# Placeholder macro written by tools/chip_assembly/macros.py
# kind: link; half of the 112G SerDes strip (die assembly 1.0 x 18.0 mm) at 1/4: the package-pair collective lanes, or the stage-hop lanes
VERSION 5.7 ;
BUSBITCHARS "[]" ;
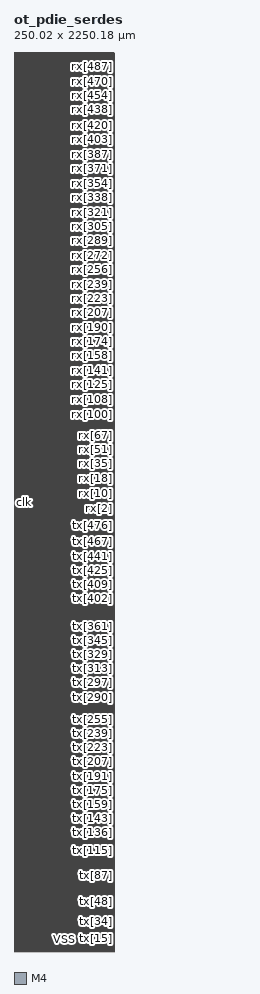
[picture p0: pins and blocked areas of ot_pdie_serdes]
MACRO ot_pdie_serdes
  FOREIGN ot_pdie_serdes 0 0 ;
  SYMMETRY X Y R90 ;
  SIZE 250.020 BY 2250.180 ;
  CLASS BLOCK ;
  PIN clk
    DIRECTION INPUT ;
    USE SIGNAL ;
    SHAPE ABUTMENT ;
    PORT
      LAYER M4 ;
      RECT 0.000 1125.072 0.192 1125.096 ;
    END
  END clk
  PIN tx[0]
    DIRECTION INPUT ;
    USE SIGNAL ;
    SHAPE ABUTMENT ;
    PORT
      LAYER M4 ;
      RECT 249.828 0.528 250.020 0.552 ;
    END
  END tx[0]
  PIN tx[1]
    DIRECTION INPUT ;
    USE SIGNAL ;
    SHAPE ABUTMENT ;
    PORT
      LAYER M4 ;
      RECT 249.828 2.688 250.020 2.712 ;
    END
  END tx[1]
  PIN tx[2]
    DIRECTION INPUT ;
    USE SIGNAL ;
    SHAPE ABUTMENT ;
    PORT
      LAYER M4 ;
      RECT 249.828 4.896 250.020 4.920 ;
    END
  END tx[2]
  PIN tx[3]
    DIRECTION INPUT ;
    USE SIGNAL ;
    SHAPE ABUTMENT ;
    PORT
      LAYER M4 ;
      RECT 249.828 7.104 250.020 7.128 ;
    END
  END tx[3]
  PIN tx[4]
    DIRECTION INPUT ;
    USE SIGNAL ;
    SHAPE ABUTMENT ;
    PORT
      LAYER M4 ;
      RECT 249.828 9.312 250.020 9.336 ;
    END
  END tx[4]
  PIN tx[5]
    DIRECTION INPUT ;
    USE SIGNAL ;
    SHAPE ABUTMENT ;
    PORT
      LAYER M4 ;
      RECT 249.828 11.472 250.020 11.496 ;
    END
  END tx[5]
  PIN tx[6]
    DIRECTION INPUT ;
    USE SIGNAL ;
    SHAPE ABUTMENT ;
    PORT
      LAYER M4 ;
      RECT 249.828 13.680 250.020 13.704 ;
    END
  END tx[6]
  PIN tx[7]
    DIRECTION INPUT ;
    USE SIGNAL ;
    SHAPE ABUTMENT ;
    PORT
      LAYER M4 ;
      RECT 249.828 15.888 250.020 15.912 ;
    END
  END tx[7]
  PIN tx[8]
    DIRECTION INPUT ;
    USE SIGNAL ;
    SHAPE ABUTMENT ;
    PORT
      LAYER M4 ;
      RECT 249.828 18.096 250.020 18.120 ;
    END
  END tx[8]
  PIN tx[9]
    DIRECTION INPUT ;
    USE SIGNAL ;
    SHAPE ABUTMENT ;
    PORT
      LAYER M4 ;
      RECT 249.828 20.256 250.020 20.280 ;
    END
  END tx[9]
  PIN tx[10]
    DIRECTION INPUT ;
    USE SIGNAL ;
    SHAPE ABUTMENT ;
    PORT
      LAYER M4 ;
      RECT 249.828 22.464 250.020 22.488 ;
    END
  END tx[10]
  PIN tx[11]
    DIRECTION INPUT ;
    USE SIGNAL ;
    SHAPE ABUTMENT ;
    PORT
      LAYER M4 ;
      RECT 249.828 24.672 250.020 24.696 ;
    END
  END tx[11]
  PIN tx[12]
    DIRECTION INPUT ;
    USE SIGNAL ;
    SHAPE ABUTMENT ;
    PORT
      LAYER M4 ;
      RECT 249.828 26.880 250.020 26.904 ;
    END
  END tx[12]
  PIN tx[13]
    DIRECTION INPUT ;
    USE SIGNAL ;
    SHAPE ABUTMENT ;
    PORT
      LAYER M4 ;
      RECT 249.828 29.040 250.020 29.064 ;
    END
  END tx[13]
  PIN tx[14]
    DIRECTION INPUT ;
    USE SIGNAL ;
    SHAPE ABUTMENT ;
    PORT
      LAYER M4 ;
      RECT 249.828 31.248 250.020 31.272 ;
    END
  END tx[14]
  PIN tx[15]
    DIRECTION INPUT ;
    USE SIGNAL ;
    SHAPE ABUTMENT ;
    PORT
      LAYER M4 ;
      RECT 249.828 33.456 250.020 33.480 ;
    END
  END tx[15]
  PIN tx[16]
    DIRECTION INPUT ;
    USE SIGNAL ;
    SHAPE ABUTMENT ;
    PORT
      LAYER M4 ;
      RECT 249.828 35.664 250.020 35.688 ;
    END
  END tx[16]
  PIN tx[17]
    DIRECTION INPUT ;
    USE SIGNAL ;
    SHAPE ABUTMENT ;
    PORT
      LAYER M4 ;
      RECT 249.828 37.824 250.020 37.848 ;
    END
  END tx[17]
  PIN tx[18]
    DIRECTION INPUT ;
    USE SIGNAL ;
    SHAPE ABUTMENT ;
    PORT
      LAYER M4 ;
      RECT 249.828 40.032 250.020 40.056 ;
    END
  END tx[18]
  PIN tx[19]
    DIRECTION INPUT ;
    USE SIGNAL ;
    SHAPE ABUTMENT ;
    PORT
      LAYER M4 ;
      RECT 249.828 42.240 250.020 42.264 ;
    END
  END tx[19]
  PIN tx[20]
    DIRECTION INPUT ;
    USE SIGNAL ;
    SHAPE ABUTMENT ;
    PORT
      LAYER M4 ;
      RECT 249.828 44.448 250.020 44.472 ;
    END
  END tx[20]
  PIN tx[21]
    DIRECTION INPUT ;
    USE SIGNAL ;
    SHAPE ABUTMENT ;
    PORT
      LAYER M4 ;
      RECT 249.828 46.608 250.020 46.632 ;
    END
  END tx[21]
  PIN tx[22]
    DIRECTION INPUT ;
    USE SIGNAL ;
    SHAPE ABUTMENT ;
    PORT
      LAYER M4 ;
      RECT 249.828 48.816 250.020 48.840 ;
    END
  END tx[22]
  PIN tx[23]
    DIRECTION INPUT ;
    USE SIGNAL ;
    SHAPE ABUTMENT ;
    PORT
      LAYER M4 ;
      RECT 249.828 51.024 250.020 51.048 ;
    END
  END tx[23]
  PIN tx[24]
    DIRECTION INPUT ;
    USE SIGNAL ;
    SHAPE ABUTMENT ;
    PORT
      LAYER M4 ;
      RECT 249.828 53.232 250.020 53.256 ;
    END
  END tx[24]
  PIN tx[25]
    DIRECTION INPUT ;
    USE SIGNAL ;
    SHAPE ABUTMENT ;
    PORT
      LAYER M4 ;
      RECT 249.828 55.392 250.020 55.416 ;
    END
  END tx[25]
  PIN tx[26]
    DIRECTION INPUT ;
    USE SIGNAL ;
    SHAPE ABUTMENT ;
    PORT
      LAYER M4 ;
      RECT 249.828 57.600 250.020 57.624 ;
    END
  END tx[26]
  PIN tx[27]
    DIRECTION INPUT ;
    USE SIGNAL ;
    SHAPE ABUTMENT ;
    PORT
      LAYER M4 ;
      RECT 249.828 59.808 250.020 59.832 ;
    END
  END tx[27]
  PIN tx[28]
    DIRECTION INPUT ;
    USE SIGNAL ;
    SHAPE ABUTMENT ;
    PORT
      LAYER M4 ;
      RECT 249.828 62.016 250.020 62.040 ;
    END
  END tx[28]
  PIN tx[29]
    DIRECTION INPUT ;
    USE SIGNAL ;
    SHAPE ABUTMENT ;
    PORT
      LAYER M4 ;
      RECT 249.828 64.224 250.020 64.248 ;
    END
  END tx[29]
  PIN tx[30]
    DIRECTION INPUT ;
    USE SIGNAL ;
    SHAPE ABUTMENT ;
    PORT
      LAYER M4 ;
      RECT 249.828 66.384 250.020 66.408 ;
    END
  END tx[30]
  PIN tx[31]
    DIRECTION INPUT ;
    USE SIGNAL ;
    SHAPE ABUTMENT ;
    PORT
      LAYER M4 ;
      RECT 249.828 68.592 250.020 68.616 ;
    END
  END tx[31]
  PIN tx[32]
    DIRECTION INPUT ;
    USE SIGNAL ;
    SHAPE ABUTMENT ;
    PORT
      LAYER M4 ;
      RECT 249.828 70.800 250.020 70.824 ;
    END
  END tx[32]
  PIN tx[33]
    DIRECTION INPUT ;
    USE SIGNAL ;
    SHAPE ABUTMENT ;
    PORT
      LAYER M4 ;
      RECT 249.828 73.008 250.020 73.032 ;
    END
  END tx[33]
  PIN tx[34]
    DIRECTION INPUT ;
    USE SIGNAL ;
    SHAPE ABUTMENT ;
    PORT
      LAYER M4 ;
      RECT 249.828 75.168 250.020 75.192 ;
    END
  END tx[34]
  PIN tx[35]
    DIRECTION INPUT ;
    USE SIGNAL ;
    SHAPE ABUTMENT ;
    PORT
      LAYER M4 ;
      RECT 249.828 77.376 250.020 77.400 ;
    END
  END tx[35]
  PIN tx[36]
    DIRECTION INPUT ;
    USE SIGNAL ;
    SHAPE ABUTMENT ;
    PORT
      LAYER M4 ;
      RECT 249.828 79.584 250.020 79.608 ;
    END
  END tx[36]
  PIN tx[37]
    DIRECTION INPUT ;
    USE SIGNAL ;
    SHAPE ABUTMENT ;
    PORT
      LAYER M4 ;
      RECT 249.828 81.792 250.020 81.816 ;
    END
  END tx[37]
  PIN tx[38]
    DIRECTION INPUT ;
    USE SIGNAL ;
    SHAPE ABUTMENT ;
    PORT
      LAYER M4 ;
      RECT 249.828 83.952 250.020 83.976 ;
    END
  END tx[38]
  PIN tx[39]
    DIRECTION INPUT ;
    USE SIGNAL ;
    SHAPE ABUTMENT ;
    PORT
      LAYER M4 ;
      RECT 249.828 86.160 250.020 86.184 ;
    END
  END tx[39]
  PIN tx[40]
    DIRECTION INPUT ;
    USE SIGNAL ;
    SHAPE ABUTMENT ;
    PORT
      LAYER M4 ;
      RECT 249.828 88.368 250.020 88.392 ;
    END
  END tx[40]
  PIN tx[41]
    DIRECTION INPUT ;
    USE SIGNAL ;
    SHAPE ABUTMENT ;
    PORT
      LAYER M4 ;
      RECT 249.828 90.576 250.020 90.600 ;
    END
  END tx[41]
  PIN tx[42]
    DIRECTION INPUT ;
    USE SIGNAL ;
    SHAPE ABUTMENT ;
    PORT
      LAYER M4 ;
      RECT 249.828 92.736 250.020 92.760 ;
    END
  END tx[42]
  PIN tx[43]
    DIRECTION INPUT ;
    USE SIGNAL ;
    SHAPE ABUTMENT ;
    PORT
      LAYER M4 ;
      RECT 249.828 94.944 250.020 94.968 ;
    END
  END tx[43]
  PIN tx[44]
    DIRECTION INPUT ;
    USE SIGNAL ;
    SHAPE ABUTMENT ;
    PORT
      LAYER M4 ;
      RECT 249.828 97.152 250.020 97.176 ;
    END
  END tx[44]
  PIN tx[45]
    DIRECTION INPUT ;
    USE SIGNAL ;
    SHAPE ABUTMENT ;
    PORT
      LAYER M4 ;
      RECT 249.828 99.360 250.020 99.384 ;
    END
  END tx[45]
  PIN tx[46]
    DIRECTION INPUT ;
    USE SIGNAL ;
    SHAPE ABUTMENT ;
    PORT
      LAYER M4 ;
      RECT 249.828 101.520 250.020 101.544 ;
    END
  END tx[46]
  PIN tx[47]
    DIRECTION INPUT ;
    USE SIGNAL ;
    SHAPE ABUTMENT ;
    PORT
      LAYER M4 ;
      RECT 249.828 103.728 250.020 103.752 ;
    END
  END tx[47]
  PIN tx[48]
    DIRECTION INPUT ;
    USE SIGNAL ;
    SHAPE ABUTMENT ;
    PORT
      LAYER M4 ;
      RECT 249.828 105.936 250.020 105.960 ;
    END
  END tx[48]
  PIN tx[49]
    DIRECTION INPUT ;
    USE SIGNAL ;
    SHAPE ABUTMENT ;
    PORT
      LAYER M4 ;
      RECT 249.828 108.144 250.020 108.168 ;
    END
  END tx[49]
  PIN tx[50]
    DIRECTION INPUT ;
    USE SIGNAL ;
    SHAPE ABUTMENT ;
    PORT
      LAYER M4 ;
      RECT 249.828 110.304 250.020 110.328 ;
    END
  END tx[50]
  PIN tx[51]
    DIRECTION INPUT ;
    USE SIGNAL ;
    SHAPE ABUTMENT ;
    PORT
      LAYER M4 ;
      RECT 249.828 112.512 250.020 112.536 ;
    END
  END tx[51]
  PIN tx[52]
    DIRECTION INPUT ;
    USE SIGNAL ;
    SHAPE ABUTMENT ;
    PORT
      LAYER M4 ;
      RECT 249.828 114.720 250.020 114.744 ;
    END
  END tx[52]
  PIN tx[53]
    DIRECTION INPUT ;
    USE SIGNAL ;
    SHAPE ABUTMENT ;
    PORT
      LAYER M4 ;
      RECT 249.828 116.928 250.020 116.952 ;
    END
  END tx[53]
  PIN tx[54]
    DIRECTION INPUT ;
    USE SIGNAL ;
    SHAPE ABUTMENT ;
    PORT
      LAYER M4 ;
      RECT 249.828 119.088 250.020 119.112 ;
    END
  END tx[54]
  PIN tx[55]
    DIRECTION INPUT ;
    USE SIGNAL ;
    SHAPE ABUTMENT ;
    PORT
      LAYER M4 ;
      RECT 249.828 121.296 250.020 121.320 ;
    END
  END tx[55]
  PIN tx[56]
    DIRECTION INPUT ;
    USE SIGNAL ;
    SHAPE ABUTMENT ;
    PORT
      LAYER M4 ;
      RECT 249.828 123.504 250.020 123.528 ;
    END
  END tx[56]
  PIN tx[57]
    DIRECTION INPUT ;
    USE SIGNAL ;
    SHAPE ABUTMENT ;
    PORT
      LAYER M4 ;
      RECT 249.828 125.712 250.020 125.736 ;
    END
  END tx[57]
  PIN tx[58]
    DIRECTION INPUT ;
    USE SIGNAL ;
    SHAPE ABUTMENT ;
    PORT
      LAYER M4 ;
      RECT 249.828 127.920 250.020 127.944 ;
    END
  END tx[58]
  PIN tx[59]
    DIRECTION INPUT ;
    USE SIGNAL ;
    SHAPE ABUTMENT ;
    PORT
      LAYER M4 ;
      RECT 249.828 130.080 250.020 130.104 ;
    END
  END tx[59]
  PIN tx[60]
    DIRECTION INPUT ;
    USE SIGNAL ;
    SHAPE ABUTMENT ;
    PORT
      LAYER M4 ;
      RECT 249.828 132.288 250.020 132.312 ;
    END
  END tx[60]
  PIN tx[61]
    DIRECTION INPUT ;
    USE SIGNAL ;
    SHAPE ABUTMENT ;
    PORT
      LAYER M4 ;
      RECT 249.828 134.496 250.020 134.520 ;
    END
  END tx[61]
  PIN tx[62]
    DIRECTION INPUT ;
    USE SIGNAL ;
    SHAPE ABUTMENT ;
    PORT
      LAYER M4 ;
      RECT 249.828 136.704 250.020 136.728 ;
    END
  END tx[62]
  PIN tx[63]
    DIRECTION INPUT ;
    USE SIGNAL ;
    SHAPE ABUTMENT ;
    PORT
      LAYER M4 ;
      RECT 249.828 138.864 250.020 138.888 ;
    END
  END tx[63]
  PIN tx[64]
    DIRECTION INPUT ;
    USE SIGNAL ;
    SHAPE ABUTMENT ;
    PORT
      LAYER M4 ;
      RECT 249.828 141.072 250.020 141.096 ;
    END
  END tx[64]
  PIN tx[65]
    DIRECTION INPUT ;
    USE SIGNAL ;
    SHAPE ABUTMENT ;
    PORT
      LAYER M4 ;
      RECT 249.828 143.280 250.020 143.304 ;
    END
  END tx[65]
  PIN tx[66]
    DIRECTION INPUT ;
    USE SIGNAL ;
    SHAPE ABUTMENT ;
    PORT
      LAYER M4 ;
      RECT 249.828 145.488 250.020 145.512 ;
    END
  END tx[66]
  PIN tx[67]
    DIRECTION INPUT ;
    USE SIGNAL ;
    SHAPE ABUTMENT ;
    PORT
      LAYER M4 ;
      RECT 249.828 147.648 250.020 147.672 ;
    END
  END tx[67]
  PIN tx[68]
    DIRECTION INPUT ;
    USE SIGNAL ;
    SHAPE ABUTMENT ;
    PORT
      LAYER M4 ;
      RECT 249.828 149.856 250.020 149.880 ;
    END
  END tx[68]
  PIN tx[69]
    DIRECTION INPUT ;
    USE SIGNAL ;
    SHAPE ABUTMENT ;
    PORT
      LAYER M4 ;
      RECT 249.828 152.064 250.020 152.088 ;
    END
  END tx[69]
  PIN tx[70]
    DIRECTION INPUT ;
    USE SIGNAL ;
    SHAPE ABUTMENT ;
    PORT
      LAYER M4 ;
      RECT 249.828 154.272 250.020 154.296 ;
    END
  END tx[70]
  PIN tx[71]
    DIRECTION INPUT ;
    USE SIGNAL ;
    SHAPE ABUTMENT ;
    PORT
      LAYER M4 ;
      RECT 249.828 156.432 250.020 156.456 ;
    END
  END tx[71]
  PIN tx[72]
    DIRECTION INPUT ;
    USE SIGNAL ;
    SHAPE ABUTMENT ;
    PORT
      LAYER M4 ;
      RECT 249.828 158.640 250.020 158.664 ;
    END
  END tx[72]
  PIN tx[73]
    DIRECTION INPUT ;
    USE SIGNAL ;
    SHAPE ABUTMENT ;
    PORT
      LAYER M4 ;
      RECT 249.828 160.848 250.020 160.872 ;
    END
  END tx[73]
  PIN tx[74]
    DIRECTION INPUT ;
    USE SIGNAL ;
    SHAPE ABUTMENT ;
    PORT
      LAYER M4 ;
      RECT 249.828 163.056 250.020 163.080 ;
    END
  END tx[74]
  PIN tx[75]
    DIRECTION INPUT ;
    USE SIGNAL ;
    SHAPE ABUTMENT ;
    PORT
      LAYER M4 ;
      RECT 249.828 165.216 250.020 165.240 ;
    END
  END tx[75]
  PIN tx[76]
    DIRECTION INPUT ;
    USE SIGNAL ;
    SHAPE ABUTMENT ;
    PORT
      LAYER M4 ;
      RECT 249.828 167.424 250.020 167.448 ;
    END
  END tx[76]
  PIN tx[77]
    DIRECTION INPUT ;
    USE SIGNAL ;
    SHAPE ABUTMENT ;
    PORT
      LAYER M4 ;
      RECT 249.828 169.632 250.020 169.656 ;
    END
  END tx[77]
  PIN tx[78]
    DIRECTION INPUT ;
    USE SIGNAL ;
    SHAPE ABUTMENT ;
    PORT
      LAYER M4 ;
      RECT 249.828 171.840 250.020 171.864 ;
    END
  END tx[78]
  PIN tx[79]
    DIRECTION INPUT ;
    USE SIGNAL ;
    SHAPE ABUTMENT ;
    PORT
      LAYER M4 ;
      RECT 249.828 174.000 250.020 174.024 ;
    END
  END tx[79]
  PIN tx[80]
    DIRECTION INPUT ;
    USE SIGNAL ;
    SHAPE ABUTMENT ;
    PORT
      LAYER M4 ;
      RECT 249.828 176.208 250.020 176.232 ;
    END
  END tx[80]
  PIN tx[81]
    DIRECTION INPUT ;
    USE SIGNAL ;
    SHAPE ABUTMENT ;
    PORT
      LAYER M4 ;
      RECT 249.828 178.416 250.020 178.440 ;
    END
  END tx[81]
  PIN tx[82]
    DIRECTION INPUT ;
    USE SIGNAL ;
    SHAPE ABUTMENT ;
    PORT
      LAYER M4 ;
      RECT 249.828 180.624 250.020 180.648 ;
    END
  END tx[82]
  PIN tx[83]
    DIRECTION INPUT ;
    USE SIGNAL ;
    SHAPE ABUTMENT ;
    PORT
      LAYER M4 ;
      RECT 249.828 182.784 250.020 182.808 ;
    END
  END tx[83]
  PIN tx[84]
    DIRECTION INPUT ;
    USE SIGNAL ;
    SHAPE ABUTMENT ;
    PORT
      LAYER M4 ;
      RECT 249.828 184.992 250.020 185.016 ;
    END
  END tx[84]
  PIN tx[85]
    DIRECTION INPUT ;
    USE SIGNAL ;
    SHAPE ABUTMENT ;
    PORT
      LAYER M4 ;
      RECT 249.828 187.200 250.020 187.224 ;
    END
  END tx[85]
  PIN tx[86]
    DIRECTION INPUT ;
    USE SIGNAL ;
    SHAPE ABUTMENT ;
    PORT
      LAYER M4 ;
      RECT 249.828 189.408 250.020 189.432 ;
    END
  END tx[86]
  PIN tx[87]
    DIRECTION INPUT ;
    USE SIGNAL ;
    SHAPE ABUTMENT ;
    PORT
      LAYER M4 ;
      RECT 249.828 191.616 250.020 191.640 ;
    END
  END tx[87]
  PIN tx[88]
    DIRECTION INPUT ;
    USE SIGNAL ;
    SHAPE ABUTMENT ;
    PORT
      LAYER M4 ;
      RECT 249.828 193.776 250.020 193.800 ;
    END
  END tx[88]
  PIN tx[89]
    DIRECTION INPUT ;
    USE SIGNAL ;
    SHAPE ABUTMENT ;
    PORT
      LAYER M4 ;
      RECT 249.828 195.984 250.020 196.008 ;
    END
  END tx[89]
  PIN tx[90]
    DIRECTION INPUT ;
    USE SIGNAL ;
    SHAPE ABUTMENT ;
    PORT
      LAYER M4 ;
      RECT 249.828 198.192 250.020 198.216 ;
    END
  END tx[90]
  PIN tx[91]
    DIRECTION INPUT ;
    USE SIGNAL ;
    SHAPE ABUTMENT ;
    PORT
      LAYER M4 ;
      RECT 249.828 200.400 250.020 200.424 ;
    END
  END tx[91]
  PIN tx[92]
    DIRECTION INPUT ;
    USE SIGNAL ;
    SHAPE ABUTMENT ;
    PORT
      LAYER M4 ;
      RECT 249.828 202.560 250.020 202.584 ;
    END
  END tx[92]
  PIN tx[93]
    DIRECTION INPUT ;
    USE SIGNAL ;
    SHAPE ABUTMENT ;
    PORT
      LAYER M4 ;
      RECT 249.828 204.768 250.020 204.792 ;
    END
  END tx[93]
  PIN tx[94]
    DIRECTION INPUT ;
    USE SIGNAL ;
    SHAPE ABUTMENT ;
    PORT
      LAYER M4 ;
      RECT 249.828 206.976 250.020 207.000 ;
    END
  END tx[94]
  PIN tx[95]
    DIRECTION INPUT ;
    USE SIGNAL ;
    SHAPE ABUTMENT ;
    PORT
      LAYER M4 ;
      RECT 249.828 209.184 250.020 209.208 ;
    END
  END tx[95]
  PIN tx[96]
    DIRECTION INPUT ;
    USE SIGNAL ;
    SHAPE ABUTMENT ;
    PORT
      LAYER M4 ;
      RECT 249.828 211.344 250.020 211.368 ;
    END
  END tx[96]
  PIN tx[97]
    DIRECTION INPUT ;
    USE SIGNAL ;
    SHAPE ABUTMENT ;
    PORT
      LAYER M4 ;
      RECT 249.828 213.552 250.020 213.576 ;
    END
  END tx[97]
  PIN tx[98]
    DIRECTION INPUT ;
    USE SIGNAL ;
    SHAPE ABUTMENT ;
    PORT
      LAYER M4 ;
      RECT 249.828 215.760 250.020 215.784 ;
    END
  END tx[98]
  PIN tx[99]
    DIRECTION INPUT ;
    USE SIGNAL ;
    SHAPE ABUTMENT ;
    PORT
      LAYER M4 ;
      RECT 249.828 217.968 250.020 217.992 ;
    END
  END tx[99]
  PIN tx[100]
    DIRECTION INPUT ;
    USE SIGNAL ;
    SHAPE ABUTMENT ;
    PORT
      LAYER M4 ;
      RECT 249.828 220.128 250.020 220.152 ;
    END
  END tx[100]
  PIN tx[101]
    DIRECTION INPUT ;
    USE SIGNAL ;
    SHAPE ABUTMENT ;
    PORT
      LAYER M4 ;
      RECT 249.828 222.336 250.020 222.360 ;
    END
  END tx[101]
  PIN tx[102]
    DIRECTION INPUT ;
    USE SIGNAL ;
    SHAPE ABUTMENT ;
    PORT
      LAYER M4 ;
      RECT 249.828 224.544 250.020 224.568 ;
    END
  END tx[102]
  PIN tx[103]
    DIRECTION INPUT ;
    USE SIGNAL ;
    SHAPE ABUTMENT ;
    PORT
      LAYER M4 ;
      RECT 249.828 226.752 250.020 226.776 ;
    END
  END tx[103]
  PIN tx[104]
    DIRECTION INPUT ;
    USE SIGNAL ;
    SHAPE ABUTMENT ;
    PORT
      LAYER M4 ;
      RECT 249.828 228.912 250.020 228.936 ;
    END
  END tx[104]
  PIN tx[105]
    DIRECTION INPUT ;
    USE SIGNAL ;
    SHAPE ABUTMENT ;
    PORT
      LAYER M4 ;
      RECT 249.828 231.120 250.020 231.144 ;
    END
  END tx[105]
  PIN tx[106]
    DIRECTION INPUT ;
    USE SIGNAL ;
    SHAPE ABUTMENT ;
    PORT
      LAYER M4 ;
      RECT 249.828 233.328 250.020 233.352 ;
    END
  END tx[106]
  PIN tx[107]
    DIRECTION INPUT ;
    USE SIGNAL ;
    SHAPE ABUTMENT ;
    PORT
      LAYER M4 ;
      RECT 249.828 235.536 250.020 235.560 ;
    END
  END tx[107]
  PIN tx[108]
    DIRECTION INPUT ;
    USE SIGNAL ;
    SHAPE ABUTMENT ;
    PORT
      LAYER M4 ;
      RECT 249.828 237.696 250.020 237.720 ;
    END
  END tx[108]
  PIN tx[109]
    DIRECTION INPUT ;
    USE SIGNAL ;
    SHAPE ABUTMENT ;
    PORT
      LAYER M4 ;
      RECT 249.828 239.904 250.020 239.928 ;
    END
  END tx[109]
  PIN tx[110]
    DIRECTION INPUT ;
    USE SIGNAL ;
    SHAPE ABUTMENT ;
    PORT
      LAYER M4 ;
      RECT 249.828 242.112 250.020 242.136 ;
    END
  END tx[110]
  PIN tx[111]
    DIRECTION INPUT ;
    USE SIGNAL ;
    SHAPE ABUTMENT ;
    PORT
      LAYER M4 ;
      RECT 249.828 244.320 250.020 244.344 ;
    END
  END tx[111]
  PIN tx[112]
    DIRECTION INPUT ;
    USE SIGNAL ;
    SHAPE ABUTMENT ;
    PORT
      LAYER M4 ;
      RECT 249.828 246.480 250.020 246.504 ;
    END
  END tx[112]
  PIN tx[113]
    DIRECTION INPUT ;
    USE SIGNAL ;
    SHAPE ABUTMENT ;
    PORT
      LAYER M4 ;
      RECT 249.828 248.688 250.020 248.712 ;
    END
  END tx[113]
  PIN tx[114]
    DIRECTION INPUT ;
    USE SIGNAL ;
    SHAPE ABUTMENT ;
    PORT
      LAYER M4 ;
      RECT 249.828 250.896 250.020 250.920 ;
    END
  END tx[114]
  PIN tx[115]
    DIRECTION INPUT ;
    USE SIGNAL ;
    SHAPE ABUTMENT ;
    PORT
      LAYER M4 ;
      RECT 249.828 253.104 250.020 253.128 ;
    END
  END tx[115]
  PIN tx[116]
    DIRECTION INPUT ;
    USE SIGNAL ;
    SHAPE ABUTMENT ;
    PORT
      LAYER M4 ;
      RECT 249.828 255.312 250.020 255.336 ;
    END
  END tx[116]
  PIN tx[117]
    DIRECTION INPUT ;
    USE SIGNAL ;
    SHAPE ABUTMENT ;
    PORT
      LAYER M4 ;
      RECT 249.828 257.472 250.020 257.496 ;
    END
  END tx[117]
  PIN tx[118]
    DIRECTION INPUT ;
    USE SIGNAL ;
    SHAPE ABUTMENT ;
    PORT
      LAYER M4 ;
      RECT 249.828 259.680 250.020 259.704 ;
    END
  END tx[118]
  PIN tx[119]
    DIRECTION INPUT ;
    USE SIGNAL ;
    SHAPE ABUTMENT ;
    PORT
      LAYER M4 ;
      RECT 249.828 261.888 250.020 261.912 ;
    END
  END tx[119]
  PIN tx[120]
    DIRECTION INPUT ;
    USE SIGNAL ;
    SHAPE ABUTMENT ;
    PORT
      LAYER M4 ;
      RECT 249.828 264.096 250.020 264.120 ;
    END
  END tx[120]
  PIN tx[121]
    DIRECTION INPUT ;
    USE SIGNAL ;
    SHAPE ABUTMENT ;
    PORT
      LAYER M4 ;
      RECT 249.828 266.256 250.020 266.280 ;
    END
  END tx[121]
  PIN tx[122]
    DIRECTION INPUT ;
    USE SIGNAL ;
    SHAPE ABUTMENT ;
    PORT
      LAYER M4 ;
      RECT 249.828 268.464 250.020 268.488 ;
    END
  END tx[122]
  PIN tx[123]
    DIRECTION INPUT ;
    USE SIGNAL ;
    SHAPE ABUTMENT ;
    PORT
      LAYER M4 ;
      RECT 249.828 270.672 250.020 270.696 ;
    END
  END tx[123]
  PIN tx[124]
    DIRECTION INPUT ;
    USE SIGNAL ;
    SHAPE ABUTMENT ;
    PORT
      LAYER M4 ;
      RECT 249.828 272.880 250.020 272.904 ;
    END
  END tx[124]
  PIN tx[125]
    DIRECTION INPUT ;
    USE SIGNAL ;
    SHAPE ABUTMENT ;
    PORT
      LAYER M4 ;
      RECT 249.828 275.040 250.020 275.064 ;
    END
  END tx[125]
  PIN tx[126]
    DIRECTION INPUT ;
    USE SIGNAL ;
    SHAPE ABUTMENT ;
    PORT
      LAYER M4 ;
      RECT 249.828 277.248 250.020 277.272 ;
    END
  END tx[126]
  PIN tx[127]
    DIRECTION INPUT ;
    USE SIGNAL ;
    SHAPE ABUTMENT ;
    PORT
      LAYER M4 ;
      RECT 249.828 279.456 250.020 279.480 ;
    END
  END tx[127]
  PIN tx[128]
    DIRECTION INPUT ;
    USE SIGNAL ;
    SHAPE ABUTMENT ;
    PORT
      LAYER M4 ;
      RECT 249.828 281.664 250.020 281.688 ;
    END
  END tx[128]
  PIN tx[129]
    DIRECTION INPUT ;
    USE SIGNAL ;
    SHAPE ABUTMENT ;
    PORT
      LAYER M4 ;
      RECT 249.828 283.824 250.020 283.848 ;
    END
  END tx[129]
  PIN tx[130]
    DIRECTION INPUT ;
    USE SIGNAL ;
    SHAPE ABUTMENT ;
    PORT
      LAYER M4 ;
      RECT 249.828 286.032 250.020 286.056 ;
    END
  END tx[130]
  PIN tx[131]
    DIRECTION INPUT ;
    USE SIGNAL ;
    SHAPE ABUTMENT ;
    PORT
      LAYER M4 ;
      RECT 249.828 288.240 250.020 288.264 ;
    END
  END tx[131]
  PIN tx[132]
    DIRECTION INPUT ;
    USE SIGNAL ;
    SHAPE ABUTMENT ;
    PORT
      LAYER M4 ;
      RECT 249.828 290.448 250.020 290.472 ;
    END
  END tx[132]
  PIN tx[133]
    DIRECTION INPUT ;
    USE SIGNAL ;
    SHAPE ABUTMENT ;
    PORT
      LAYER M4 ;
      RECT 249.828 292.608 250.020 292.632 ;
    END
  END tx[133]
  PIN tx[134]
    DIRECTION INPUT ;
    USE SIGNAL ;
    SHAPE ABUTMENT ;
    PORT
      LAYER M4 ;
      RECT 249.828 294.816 250.020 294.840 ;
    END
  END tx[134]
  PIN tx[135]
    DIRECTION INPUT ;
    USE SIGNAL ;
    SHAPE ABUTMENT ;
    PORT
      LAYER M4 ;
      RECT 249.828 297.024 250.020 297.048 ;
    END
  END tx[135]
  PIN tx[136]
    DIRECTION INPUT ;
    USE SIGNAL ;
    SHAPE ABUTMENT ;
    PORT
      LAYER M4 ;
      RECT 249.828 299.232 250.020 299.256 ;
    END
  END tx[136]
  PIN tx[137]
    DIRECTION INPUT ;
    USE SIGNAL ;
    SHAPE ABUTMENT ;
    PORT
      LAYER M4 ;
      RECT 249.828 301.392 250.020 301.416 ;
    END
  END tx[137]
  PIN tx[138]
    DIRECTION INPUT ;
    USE SIGNAL ;
    SHAPE ABUTMENT ;
    PORT
      LAYER M4 ;
      RECT 249.828 303.600 250.020 303.624 ;
    END
  END tx[138]
  PIN tx[139]
    DIRECTION INPUT ;
    USE SIGNAL ;
    SHAPE ABUTMENT ;
    PORT
      LAYER M4 ;
      RECT 249.828 305.808 250.020 305.832 ;
    END
  END tx[139]
  PIN tx[140]
    DIRECTION INPUT ;
    USE SIGNAL ;
    SHAPE ABUTMENT ;
    PORT
      LAYER M4 ;
      RECT 249.828 308.016 250.020 308.040 ;
    END
  END tx[140]
  PIN tx[141]
    DIRECTION INPUT ;
    USE SIGNAL ;
    SHAPE ABUTMENT ;
    PORT
      LAYER M4 ;
      RECT 249.828 310.176 250.020 310.200 ;
    END
  END tx[141]
  PIN tx[142]
    DIRECTION INPUT ;
    USE SIGNAL ;
    SHAPE ABUTMENT ;
    PORT
      LAYER M4 ;
      RECT 249.828 312.384 250.020 312.408 ;
    END
  END tx[142]
  PIN tx[143]
    DIRECTION INPUT ;
    USE SIGNAL ;
    SHAPE ABUTMENT ;
    PORT
      LAYER M4 ;
      RECT 249.828 314.592 250.020 314.616 ;
    END
  END tx[143]
  PIN tx[144]
    DIRECTION INPUT ;
    USE SIGNAL ;
    SHAPE ABUTMENT ;
    PORT
      LAYER M4 ;
      RECT 249.828 316.800 250.020 316.824 ;
    END
  END tx[144]
  PIN tx[145]
    DIRECTION INPUT ;
    USE SIGNAL ;
    SHAPE ABUTMENT ;
    PORT
      LAYER M4 ;
      RECT 249.828 319.008 250.020 319.032 ;
    END
  END tx[145]
  PIN tx[146]
    DIRECTION INPUT ;
    USE SIGNAL ;
    SHAPE ABUTMENT ;
    PORT
      LAYER M4 ;
      RECT 249.828 321.168 250.020 321.192 ;
    END
  END tx[146]
  PIN tx[147]
    DIRECTION INPUT ;
    USE SIGNAL ;
    SHAPE ABUTMENT ;
    PORT
      LAYER M4 ;
      RECT 249.828 323.376 250.020 323.400 ;
    END
  END tx[147]
  PIN tx[148]
    DIRECTION INPUT ;
    USE SIGNAL ;
    SHAPE ABUTMENT ;
    PORT
      LAYER M4 ;
      RECT 249.828 325.584 250.020 325.608 ;
    END
  END tx[148]
  PIN tx[149]
    DIRECTION INPUT ;
    USE SIGNAL ;
    SHAPE ABUTMENT ;
    PORT
      LAYER M4 ;
      RECT 249.828 327.792 250.020 327.816 ;
    END
  END tx[149]
  PIN tx[150]
    DIRECTION INPUT ;
    USE SIGNAL ;
    SHAPE ABUTMENT ;
    PORT
      LAYER M4 ;
      RECT 249.828 329.952 250.020 329.976 ;
    END
  END tx[150]
  PIN tx[151]
    DIRECTION INPUT ;
    USE SIGNAL ;
    SHAPE ABUTMENT ;
    PORT
      LAYER M4 ;
      RECT 249.828 332.160 250.020 332.184 ;
    END
  END tx[151]
  PIN tx[152]
    DIRECTION INPUT ;
    USE SIGNAL ;
    SHAPE ABUTMENT ;
    PORT
      LAYER M4 ;
      RECT 249.828 334.368 250.020 334.392 ;
    END
  END tx[152]
  PIN tx[153]
    DIRECTION INPUT ;
    USE SIGNAL ;
    SHAPE ABUTMENT ;
    PORT
      LAYER M4 ;
      RECT 249.828 336.576 250.020 336.600 ;
    END
  END tx[153]
  PIN tx[154]
    DIRECTION INPUT ;
    USE SIGNAL ;
    SHAPE ABUTMENT ;
    PORT
      LAYER M4 ;
      RECT 249.828 338.736 250.020 338.760 ;
    END
  END tx[154]
  PIN tx[155]
    DIRECTION INPUT ;
    USE SIGNAL ;
    SHAPE ABUTMENT ;
    PORT
      LAYER M4 ;
      RECT 249.828 340.944 250.020 340.968 ;
    END
  END tx[155]
  PIN tx[156]
    DIRECTION INPUT ;
    USE SIGNAL ;
    SHAPE ABUTMENT ;
    PORT
      LAYER M4 ;
      RECT 249.828 343.152 250.020 343.176 ;
    END
  END tx[156]
  PIN tx[157]
    DIRECTION INPUT ;
    USE SIGNAL ;
    SHAPE ABUTMENT ;
    PORT
      LAYER M4 ;
      RECT 249.828 345.360 250.020 345.384 ;
    END
  END tx[157]
  PIN tx[158]
    DIRECTION INPUT ;
    USE SIGNAL ;
    SHAPE ABUTMENT ;
    PORT
      LAYER M4 ;
      RECT 249.828 347.520 250.020 347.544 ;
    END
  END tx[158]
  PIN tx[159]
    DIRECTION INPUT ;
    USE SIGNAL ;
    SHAPE ABUTMENT ;
    PORT
      LAYER M4 ;
      RECT 249.828 349.728 250.020 349.752 ;
    END
  END tx[159]
  PIN tx[160]
    DIRECTION INPUT ;
    USE SIGNAL ;
    SHAPE ABUTMENT ;
    PORT
      LAYER M4 ;
      RECT 249.828 351.936 250.020 351.960 ;
    END
  END tx[160]
  PIN tx[161]
    DIRECTION INPUT ;
    USE SIGNAL ;
    SHAPE ABUTMENT ;
    PORT
      LAYER M4 ;
      RECT 249.828 354.144 250.020 354.168 ;
    END
  END tx[161]
  PIN tx[162]
    DIRECTION INPUT ;
    USE SIGNAL ;
    SHAPE ABUTMENT ;
    PORT
      LAYER M4 ;
      RECT 249.828 356.304 250.020 356.328 ;
    END
  END tx[162]
  PIN tx[163]
    DIRECTION INPUT ;
    USE SIGNAL ;
    SHAPE ABUTMENT ;
    PORT
      LAYER M4 ;
      RECT 249.828 358.512 250.020 358.536 ;
    END
  END tx[163]
  PIN tx[164]
    DIRECTION INPUT ;
    USE SIGNAL ;
    SHAPE ABUTMENT ;
    PORT
      LAYER M4 ;
      RECT 249.828 360.720 250.020 360.744 ;
    END
  END tx[164]
  PIN tx[165]
    DIRECTION INPUT ;
    USE SIGNAL ;
    SHAPE ABUTMENT ;
    PORT
      LAYER M4 ;
      RECT 249.828 362.928 250.020 362.952 ;
    END
  END tx[165]
  PIN tx[166]
    DIRECTION INPUT ;
    USE SIGNAL ;
    SHAPE ABUTMENT ;
    PORT
      LAYER M4 ;
      RECT 249.828 365.088 250.020 365.112 ;
    END
  END tx[166]
  PIN tx[167]
    DIRECTION INPUT ;
    USE SIGNAL ;
    SHAPE ABUTMENT ;
    PORT
      LAYER M4 ;
      RECT 249.828 367.296 250.020 367.320 ;
    END
  END tx[167]
  PIN tx[168]
    DIRECTION INPUT ;
    USE SIGNAL ;
    SHAPE ABUTMENT ;
    PORT
      LAYER M4 ;
      RECT 249.828 369.504 250.020 369.528 ;
    END
  END tx[168]
  PIN tx[169]
    DIRECTION INPUT ;
    USE SIGNAL ;
    SHAPE ABUTMENT ;
    PORT
      LAYER M4 ;
      RECT 249.828 371.712 250.020 371.736 ;
    END
  END tx[169]
  PIN tx[170]
    DIRECTION INPUT ;
    USE SIGNAL ;
    SHAPE ABUTMENT ;
    PORT
      LAYER M4 ;
      RECT 249.828 373.872 250.020 373.896 ;
    END
  END tx[170]
  PIN tx[171]
    DIRECTION INPUT ;
    USE SIGNAL ;
    SHAPE ABUTMENT ;
    PORT
      LAYER M4 ;
      RECT 249.828 376.080 250.020 376.104 ;
    END
  END tx[171]
  PIN tx[172]
    DIRECTION INPUT ;
    USE SIGNAL ;
    SHAPE ABUTMENT ;
    PORT
      LAYER M4 ;
      RECT 249.828 378.288 250.020 378.312 ;
    END
  END tx[172]
  PIN tx[173]
    DIRECTION INPUT ;
    USE SIGNAL ;
    SHAPE ABUTMENT ;
    PORT
      LAYER M4 ;
      RECT 249.828 380.496 250.020 380.520 ;
    END
  END tx[173]
  PIN tx[174]
    DIRECTION INPUT ;
    USE SIGNAL ;
    SHAPE ABUTMENT ;
    PORT
      LAYER M4 ;
      RECT 249.828 382.704 250.020 382.728 ;
    END
  END tx[174]
  PIN tx[175]
    DIRECTION INPUT ;
    USE SIGNAL ;
    SHAPE ABUTMENT ;
    PORT
      LAYER M4 ;
      RECT 249.828 384.864 250.020 384.888 ;
    END
  END tx[175]
  PIN tx[176]
    DIRECTION INPUT ;
    USE SIGNAL ;
    SHAPE ABUTMENT ;
    PORT
      LAYER M4 ;
      RECT 249.828 387.072 250.020 387.096 ;
    END
  END tx[176]
  PIN tx[177]
    DIRECTION INPUT ;
    USE SIGNAL ;
    SHAPE ABUTMENT ;
    PORT
      LAYER M4 ;
      RECT 249.828 389.280 250.020 389.304 ;
    END
  END tx[177]
  PIN tx[178]
    DIRECTION INPUT ;
    USE SIGNAL ;
    SHAPE ABUTMENT ;
    PORT
      LAYER M4 ;
      RECT 249.828 391.488 250.020 391.512 ;
    END
  END tx[178]
  PIN tx[179]
    DIRECTION INPUT ;
    USE SIGNAL ;
    SHAPE ABUTMENT ;
    PORT
      LAYER M4 ;
      RECT 249.828 393.648 250.020 393.672 ;
    END
  END tx[179]
  PIN tx[180]
    DIRECTION INPUT ;
    USE SIGNAL ;
    SHAPE ABUTMENT ;
    PORT
      LAYER M4 ;
      RECT 249.828 395.856 250.020 395.880 ;
    END
  END tx[180]
  PIN tx[181]
    DIRECTION INPUT ;
    USE SIGNAL ;
    SHAPE ABUTMENT ;
    PORT
      LAYER M4 ;
      RECT 249.828 398.064 250.020 398.088 ;
    END
  END tx[181]
  PIN tx[182]
    DIRECTION INPUT ;
    USE SIGNAL ;
    SHAPE ABUTMENT ;
    PORT
      LAYER M4 ;
      RECT 249.828 400.272 250.020 400.296 ;
    END
  END tx[182]
  PIN tx[183]
    DIRECTION INPUT ;
    USE SIGNAL ;
    SHAPE ABUTMENT ;
    PORT
      LAYER M4 ;
      RECT 249.828 402.432 250.020 402.456 ;
    END
  END tx[183]
  PIN tx[184]
    DIRECTION INPUT ;
    USE SIGNAL ;
    SHAPE ABUTMENT ;
    PORT
      LAYER M4 ;
      RECT 249.828 404.640 250.020 404.664 ;
    END
  END tx[184]
  PIN tx[185]
    DIRECTION INPUT ;
    USE SIGNAL ;
    SHAPE ABUTMENT ;
    PORT
      LAYER M4 ;
      RECT 249.828 406.848 250.020 406.872 ;
    END
  END tx[185]
  PIN tx[186]
    DIRECTION INPUT ;
    USE SIGNAL ;
    SHAPE ABUTMENT ;
    PORT
      LAYER M4 ;
      RECT 249.828 409.056 250.020 409.080 ;
    END
  END tx[186]
  PIN tx[187]
    DIRECTION INPUT ;
    USE SIGNAL ;
    SHAPE ABUTMENT ;
    PORT
      LAYER M4 ;
      RECT 249.828 411.216 250.020 411.240 ;
    END
  END tx[187]
  PIN tx[188]
    DIRECTION INPUT ;
    USE SIGNAL ;
    SHAPE ABUTMENT ;
    PORT
      LAYER M4 ;
      RECT 249.828 413.424 250.020 413.448 ;
    END
  END tx[188]
  PIN tx[189]
    DIRECTION INPUT ;
    USE SIGNAL ;
    SHAPE ABUTMENT ;
    PORT
      LAYER M4 ;
      RECT 249.828 415.632 250.020 415.656 ;
    END
  END tx[189]
  PIN tx[190]
    DIRECTION INPUT ;
    USE SIGNAL ;
    SHAPE ABUTMENT ;
    PORT
      LAYER M4 ;
      RECT 249.828 417.840 250.020 417.864 ;
    END
  END tx[190]
  PIN tx[191]
    DIRECTION INPUT ;
    USE SIGNAL ;
    SHAPE ABUTMENT ;
    PORT
      LAYER M4 ;
      RECT 249.828 420.000 250.020 420.024 ;
    END
  END tx[191]
  PIN tx[192]
    DIRECTION INPUT ;
    USE SIGNAL ;
    SHAPE ABUTMENT ;
    PORT
      LAYER M4 ;
      RECT 249.828 422.208 250.020 422.232 ;
    END
  END tx[192]
  PIN tx[193]
    DIRECTION INPUT ;
    USE SIGNAL ;
    SHAPE ABUTMENT ;
    PORT
      LAYER M4 ;
      RECT 249.828 424.416 250.020 424.440 ;
    END
  END tx[193]
  PIN tx[194]
    DIRECTION INPUT ;
    USE SIGNAL ;
    SHAPE ABUTMENT ;
    PORT
      LAYER M4 ;
      RECT 249.828 426.624 250.020 426.648 ;
    END
  END tx[194]
  PIN tx[195]
    DIRECTION INPUT ;
    USE SIGNAL ;
    SHAPE ABUTMENT ;
    PORT
      LAYER M4 ;
      RECT 249.828 428.784 250.020 428.808 ;
    END
  END tx[195]
  PIN tx[196]
    DIRECTION INPUT ;
    USE SIGNAL ;
    SHAPE ABUTMENT ;
    PORT
      LAYER M4 ;
      RECT 249.828 430.992 250.020 431.016 ;
    END
  END tx[196]
  PIN tx[197]
    DIRECTION INPUT ;
    USE SIGNAL ;
    SHAPE ABUTMENT ;
    PORT
      LAYER M4 ;
      RECT 249.828 433.200 250.020 433.224 ;
    END
  END tx[197]
  PIN tx[198]
    DIRECTION INPUT ;
    USE SIGNAL ;
    SHAPE ABUTMENT ;
    PORT
      LAYER M4 ;
      RECT 249.828 435.408 250.020 435.432 ;
    END
  END tx[198]
  PIN tx[199]
    DIRECTION INPUT ;
    USE SIGNAL ;
    SHAPE ABUTMENT ;
    PORT
      LAYER M4 ;
      RECT 249.828 437.568 250.020 437.592 ;
    END
  END tx[199]
  PIN tx[200]
    DIRECTION INPUT ;
    USE SIGNAL ;
    SHAPE ABUTMENT ;
    PORT
      LAYER M4 ;
      RECT 249.828 439.776 250.020 439.800 ;
    END
  END tx[200]
  PIN tx[201]
    DIRECTION INPUT ;
    USE SIGNAL ;
    SHAPE ABUTMENT ;
    PORT
      LAYER M4 ;
      RECT 249.828 441.984 250.020 442.008 ;
    END
  END tx[201]
  PIN tx[202]
    DIRECTION INPUT ;
    USE SIGNAL ;
    SHAPE ABUTMENT ;
    PORT
      LAYER M4 ;
      RECT 249.828 444.192 250.020 444.216 ;
    END
  END tx[202]
  PIN tx[203]
    DIRECTION INPUT ;
    USE SIGNAL ;
    SHAPE ABUTMENT ;
    PORT
      LAYER M4 ;
      RECT 249.828 446.400 250.020 446.424 ;
    END
  END tx[203]
  PIN tx[204]
    DIRECTION INPUT ;
    USE SIGNAL ;
    SHAPE ABUTMENT ;
    PORT
      LAYER M4 ;
      RECT 249.828 448.560 250.020 448.584 ;
    END
  END tx[204]
  PIN tx[205]
    DIRECTION INPUT ;
    USE SIGNAL ;
    SHAPE ABUTMENT ;
    PORT
      LAYER M4 ;
      RECT 249.828 450.768 250.020 450.792 ;
    END
  END tx[205]
  PIN tx[206]
    DIRECTION INPUT ;
    USE SIGNAL ;
    SHAPE ABUTMENT ;
    PORT
      LAYER M4 ;
      RECT 249.828 452.976 250.020 453.000 ;
    END
  END tx[206]
  PIN tx[207]
    DIRECTION INPUT ;
    USE SIGNAL ;
    SHAPE ABUTMENT ;
    PORT
      LAYER M4 ;
      RECT 249.828 455.184 250.020 455.208 ;
    END
  END tx[207]
  PIN tx[208]
    DIRECTION INPUT ;
    USE SIGNAL ;
    SHAPE ABUTMENT ;
    PORT
      LAYER M4 ;
      RECT 249.828 457.344 250.020 457.368 ;
    END
  END tx[208]
  PIN tx[209]
    DIRECTION INPUT ;
    USE SIGNAL ;
    SHAPE ABUTMENT ;
    PORT
      LAYER M4 ;
      RECT 249.828 459.552 250.020 459.576 ;
    END
  END tx[209]
  PIN tx[210]
    DIRECTION INPUT ;
    USE SIGNAL ;
    SHAPE ABUTMENT ;
    PORT
      LAYER M4 ;
      RECT 249.828 461.760 250.020 461.784 ;
    END
  END tx[210]
  PIN tx[211]
    DIRECTION INPUT ;
    USE SIGNAL ;
    SHAPE ABUTMENT ;
    PORT
      LAYER M4 ;
      RECT 249.828 463.968 250.020 463.992 ;
    END
  END tx[211]
  PIN tx[212]
    DIRECTION INPUT ;
    USE SIGNAL ;
    SHAPE ABUTMENT ;
    PORT
      LAYER M4 ;
      RECT 249.828 466.128 250.020 466.152 ;
    END
  END tx[212]
  PIN tx[213]
    DIRECTION INPUT ;
    USE SIGNAL ;
    SHAPE ABUTMENT ;
    PORT
      LAYER M4 ;
      RECT 249.828 468.336 250.020 468.360 ;
    END
  END tx[213]
  PIN tx[214]
    DIRECTION INPUT ;
    USE SIGNAL ;
    SHAPE ABUTMENT ;
    PORT
      LAYER M4 ;
      RECT 249.828 470.544 250.020 470.568 ;
    END
  END tx[214]
  PIN tx[215]
    DIRECTION INPUT ;
    USE SIGNAL ;
    SHAPE ABUTMENT ;
    PORT
      LAYER M4 ;
      RECT 249.828 472.752 250.020 472.776 ;
    END
  END tx[215]
  PIN tx[216]
    DIRECTION INPUT ;
    USE SIGNAL ;
    SHAPE ABUTMENT ;
    PORT
      LAYER M4 ;
      RECT 249.828 474.912 250.020 474.936 ;
    END
  END tx[216]
  PIN tx[217]
    DIRECTION INPUT ;
    USE SIGNAL ;
    SHAPE ABUTMENT ;
    PORT
      LAYER M4 ;
      RECT 249.828 477.120 250.020 477.144 ;
    END
  END tx[217]
  PIN tx[218]
    DIRECTION INPUT ;
    USE SIGNAL ;
    SHAPE ABUTMENT ;
    PORT
      LAYER M4 ;
      RECT 249.828 479.328 250.020 479.352 ;
    END
  END tx[218]
  PIN tx[219]
    DIRECTION INPUT ;
    USE SIGNAL ;
    SHAPE ABUTMENT ;
    PORT
      LAYER M4 ;
      RECT 249.828 481.536 250.020 481.560 ;
    END
  END tx[219]
  PIN tx[220]
    DIRECTION INPUT ;
    USE SIGNAL ;
    SHAPE ABUTMENT ;
    PORT
      LAYER M4 ;
      RECT 249.828 483.696 250.020 483.720 ;
    END
  END tx[220]
  PIN tx[221]
    DIRECTION INPUT ;
    USE SIGNAL ;
    SHAPE ABUTMENT ;
    PORT
      LAYER M4 ;
      RECT 249.828 485.904 250.020 485.928 ;
    END
  END tx[221]
  PIN tx[222]
    DIRECTION INPUT ;
    USE SIGNAL ;
    SHAPE ABUTMENT ;
    PORT
      LAYER M4 ;
      RECT 249.828 488.112 250.020 488.136 ;
    END
  END tx[222]
  PIN tx[223]
    DIRECTION INPUT ;
    USE SIGNAL ;
    SHAPE ABUTMENT ;
    PORT
      LAYER M4 ;
      RECT 249.828 490.320 250.020 490.344 ;
    END
  END tx[223]
  PIN tx[224]
    DIRECTION INPUT ;
    USE SIGNAL ;
    SHAPE ABUTMENT ;
    PORT
      LAYER M4 ;
      RECT 249.828 492.480 250.020 492.504 ;
    END
  END tx[224]
  PIN tx[225]
    DIRECTION INPUT ;
    USE SIGNAL ;
    SHAPE ABUTMENT ;
    PORT
      LAYER M4 ;
      RECT 249.828 494.688 250.020 494.712 ;
    END
  END tx[225]
  PIN tx[226]
    DIRECTION INPUT ;
    USE SIGNAL ;
    SHAPE ABUTMENT ;
    PORT
      LAYER M4 ;
      RECT 249.828 496.896 250.020 496.920 ;
    END
  END tx[226]
  PIN tx[227]
    DIRECTION INPUT ;
    USE SIGNAL ;
    SHAPE ABUTMENT ;
    PORT
      LAYER M4 ;
      RECT 249.828 499.104 250.020 499.128 ;
    END
  END tx[227]
  PIN tx[228]
    DIRECTION INPUT ;
    USE SIGNAL ;
    SHAPE ABUTMENT ;
    PORT
      LAYER M4 ;
      RECT 249.828 501.312 250.020 501.336 ;
    END
  END tx[228]
  PIN tx[229]
    DIRECTION INPUT ;
    USE SIGNAL ;
    SHAPE ABUTMENT ;
    PORT
      LAYER M4 ;
      RECT 249.828 503.472 250.020 503.496 ;
    END
  END tx[229]
  PIN tx[230]
    DIRECTION INPUT ;
    USE SIGNAL ;
    SHAPE ABUTMENT ;
    PORT
      LAYER M4 ;
      RECT 249.828 505.680 250.020 505.704 ;
    END
  END tx[230]
  PIN tx[231]
    DIRECTION INPUT ;
    USE SIGNAL ;
    SHAPE ABUTMENT ;
    PORT
      LAYER M4 ;
      RECT 249.828 507.888 250.020 507.912 ;
    END
  END tx[231]
  PIN tx[232]
    DIRECTION INPUT ;
    USE SIGNAL ;
    SHAPE ABUTMENT ;
    PORT
      LAYER M4 ;
      RECT 249.828 510.096 250.020 510.120 ;
    END
  END tx[232]
  PIN tx[233]
    DIRECTION INPUT ;
    USE SIGNAL ;
    SHAPE ABUTMENT ;
    PORT
      LAYER M4 ;
      RECT 249.828 512.256 250.020 512.280 ;
    END
  END tx[233]
  PIN tx[234]
    DIRECTION INPUT ;
    USE SIGNAL ;
    SHAPE ABUTMENT ;
    PORT
      LAYER M4 ;
      RECT 249.828 514.464 250.020 514.488 ;
    END
  END tx[234]
  PIN tx[235]
    DIRECTION INPUT ;
    USE SIGNAL ;
    SHAPE ABUTMENT ;
    PORT
      LAYER M4 ;
      RECT 249.828 516.672 250.020 516.696 ;
    END
  END tx[235]
  PIN tx[236]
    DIRECTION INPUT ;
    USE SIGNAL ;
    SHAPE ABUTMENT ;
    PORT
      LAYER M4 ;
      RECT 249.828 518.880 250.020 518.904 ;
    END
  END tx[236]
  PIN tx[237]
    DIRECTION INPUT ;
    USE SIGNAL ;
    SHAPE ABUTMENT ;
    PORT
      LAYER M4 ;
      RECT 249.828 521.040 250.020 521.064 ;
    END
  END tx[237]
  PIN tx[238]
    DIRECTION INPUT ;
    USE SIGNAL ;
    SHAPE ABUTMENT ;
    PORT
      LAYER M4 ;
      RECT 249.828 523.248 250.020 523.272 ;
    END
  END tx[238]
  PIN tx[239]
    DIRECTION INPUT ;
    USE SIGNAL ;
    SHAPE ABUTMENT ;
    PORT
      LAYER M4 ;
      RECT 249.828 525.456 250.020 525.480 ;
    END
  END tx[239]
  PIN tx[240]
    DIRECTION INPUT ;
    USE SIGNAL ;
    SHAPE ABUTMENT ;
    PORT
      LAYER M4 ;
      RECT 249.828 527.664 250.020 527.688 ;
    END
  END tx[240]
  PIN tx[241]
    DIRECTION INPUT ;
    USE SIGNAL ;
    SHAPE ABUTMENT ;
    PORT
      LAYER M4 ;
      RECT 249.828 529.824 250.020 529.848 ;
    END
  END tx[241]
  PIN tx[242]
    DIRECTION INPUT ;
    USE SIGNAL ;
    SHAPE ABUTMENT ;
    PORT
      LAYER M4 ;
      RECT 249.828 532.032 250.020 532.056 ;
    END
  END tx[242]
  PIN tx[243]
    DIRECTION INPUT ;
    USE SIGNAL ;
    SHAPE ABUTMENT ;
    PORT
      LAYER M4 ;
      RECT 249.828 534.240 250.020 534.264 ;
    END
  END tx[243]
  PIN tx[244]
    DIRECTION INPUT ;
    USE SIGNAL ;
    SHAPE ABUTMENT ;
    PORT
      LAYER M4 ;
      RECT 249.828 536.448 250.020 536.472 ;
    END
  END tx[244]
  PIN tx[245]
    DIRECTION INPUT ;
    USE SIGNAL ;
    SHAPE ABUTMENT ;
    PORT
      LAYER M4 ;
      RECT 249.828 538.608 250.020 538.632 ;
    END
  END tx[245]
  PIN tx[246]
    DIRECTION INPUT ;
    USE SIGNAL ;
    SHAPE ABUTMENT ;
    PORT
      LAYER M4 ;
      RECT 249.828 540.816 250.020 540.840 ;
    END
  END tx[246]
  PIN tx[247]
    DIRECTION INPUT ;
    USE SIGNAL ;
    SHAPE ABUTMENT ;
    PORT
      LAYER M4 ;
      RECT 249.828 543.024 250.020 543.048 ;
    END
  END tx[247]
  PIN tx[248]
    DIRECTION INPUT ;
    USE SIGNAL ;
    SHAPE ABUTMENT ;
    PORT
      LAYER M4 ;
      RECT 249.828 545.232 250.020 545.256 ;
    END
  END tx[248]
  PIN tx[249]
    DIRECTION INPUT ;
    USE SIGNAL ;
    SHAPE ABUTMENT ;
    PORT
      LAYER M4 ;
      RECT 249.828 547.392 250.020 547.416 ;
    END
  END tx[249]
  PIN tx[250]
    DIRECTION INPUT ;
    USE SIGNAL ;
    SHAPE ABUTMENT ;
    PORT
      LAYER M4 ;
      RECT 249.828 549.600 250.020 549.624 ;
    END
  END tx[250]
  PIN tx[251]
    DIRECTION INPUT ;
    USE SIGNAL ;
    SHAPE ABUTMENT ;
    PORT
      LAYER M4 ;
      RECT 249.828 551.808 250.020 551.832 ;
    END
  END tx[251]
  PIN tx[252]
    DIRECTION INPUT ;
    USE SIGNAL ;
    SHAPE ABUTMENT ;
    PORT
      LAYER M4 ;
      RECT 249.828 554.016 250.020 554.040 ;
    END
  END tx[252]
  PIN tx[253]
    DIRECTION INPUT ;
    USE SIGNAL ;
    SHAPE ABUTMENT ;
    PORT
      LAYER M4 ;
      RECT 249.828 556.176 250.020 556.200 ;
    END
  END tx[253]
  PIN tx[254]
    DIRECTION INPUT ;
    USE SIGNAL ;
    SHAPE ABUTMENT ;
    PORT
      LAYER M4 ;
      RECT 249.828 558.384 250.020 558.408 ;
    END
  END tx[254]
  PIN tx[255]
    DIRECTION INPUT ;
    USE SIGNAL ;
    SHAPE ABUTMENT ;
    PORT
      LAYER M4 ;
      RECT 249.828 560.592 250.020 560.616 ;
    END
  END tx[255]
  PIN tx[256]
    DIRECTION INPUT ;
    USE SIGNAL ;
    SHAPE ABUTMENT ;
    PORT
      LAYER M4 ;
      RECT 249.828 562.800 250.020 562.824 ;
    END
  END tx[256]
  PIN tx[257]
    DIRECTION INPUT ;
    USE SIGNAL ;
    SHAPE ABUTMENT ;
    PORT
      LAYER M4 ;
      RECT 249.828 565.008 250.020 565.032 ;
    END
  END tx[257]
  PIN tx[258]
    DIRECTION INPUT ;
    USE SIGNAL ;
    SHAPE ABUTMENT ;
    PORT
      LAYER M4 ;
      RECT 249.828 567.168 250.020 567.192 ;
    END
  END tx[258]
  PIN tx[259]
    DIRECTION INPUT ;
    USE SIGNAL ;
    SHAPE ABUTMENT ;
    PORT
      LAYER M4 ;
      RECT 249.828 569.376 250.020 569.400 ;
    END
  END tx[259]
  PIN tx[260]
    DIRECTION INPUT ;
    USE SIGNAL ;
    SHAPE ABUTMENT ;
    PORT
      LAYER M4 ;
      RECT 249.828 571.584 250.020 571.608 ;
    END
  END tx[260]
  PIN tx[261]
    DIRECTION INPUT ;
    USE SIGNAL ;
    SHAPE ABUTMENT ;
    PORT
      LAYER M4 ;
      RECT 249.828 573.792 250.020 573.816 ;
    END
  END tx[261]
  PIN tx[262]
    DIRECTION INPUT ;
    USE SIGNAL ;
    SHAPE ABUTMENT ;
    PORT
      LAYER M4 ;
      RECT 249.828 575.952 250.020 575.976 ;
    END
  END tx[262]
  PIN tx[263]
    DIRECTION INPUT ;
    USE SIGNAL ;
    SHAPE ABUTMENT ;
    PORT
      LAYER M4 ;
      RECT 249.828 578.160 250.020 578.184 ;
    END
  END tx[263]
  PIN tx[264]
    DIRECTION INPUT ;
    USE SIGNAL ;
    SHAPE ABUTMENT ;
    PORT
      LAYER M4 ;
      RECT 249.828 580.368 250.020 580.392 ;
    END
  END tx[264]
  PIN tx[265]
    DIRECTION INPUT ;
    USE SIGNAL ;
    SHAPE ABUTMENT ;
    PORT
      LAYER M4 ;
      RECT 249.828 582.576 250.020 582.600 ;
    END
  END tx[265]
  PIN tx[266]
    DIRECTION INPUT ;
    USE SIGNAL ;
    SHAPE ABUTMENT ;
    PORT
      LAYER M4 ;
      RECT 249.828 584.736 250.020 584.760 ;
    END
  END tx[266]
  PIN tx[267]
    DIRECTION INPUT ;
    USE SIGNAL ;
    SHAPE ABUTMENT ;
    PORT
      LAYER M4 ;
      RECT 249.828 586.944 250.020 586.968 ;
    END
  END tx[267]
  PIN tx[268]
    DIRECTION INPUT ;
    USE SIGNAL ;
    SHAPE ABUTMENT ;
    PORT
      LAYER M4 ;
      RECT 249.828 589.152 250.020 589.176 ;
    END
  END tx[268]
  PIN tx[269]
    DIRECTION INPUT ;
    USE SIGNAL ;
    SHAPE ABUTMENT ;
    PORT
      LAYER M4 ;
      RECT 249.828 591.360 250.020 591.384 ;
    END
  END tx[269]
  PIN tx[270]
    DIRECTION INPUT ;
    USE SIGNAL ;
    SHAPE ABUTMENT ;
    PORT
      LAYER M4 ;
      RECT 249.828 593.520 250.020 593.544 ;
    END
  END tx[270]
  PIN tx[271]
    DIRECTION INPUT ;
    USE SIGNAL ;
    SHAPE ABUTMENT ;
    PORT
      LAYER M4 ;
      RECT 249.828 595.728 250.020 595.752 ;
    END
  END tx[271]
  PIN tx[272]
    DIRECTION INPUT ;
    USE SIGNAL ;
    SHAPE ABUTMENT ;
    PORT
      LAYER M4 ;
      RECT 249.828 597.936 250.020 597.960 ;
    END
  END tx[272]
  PIN tx[273]
    DIRECTION INPUT ;
    USE SIGNAL ;
    SHAPE ABUTMENT ;
    PORT
      LAYER M4 ;
      RECT 249.828 600.144 250.020 600.168 ;
    END
  END tx[273]
  PIN tx[274]
    DIRECTION INPUT ;
    USE SIGNAL ;
    SHAPE ABUTMENT ;
    PORT
      LAYER M4 ;
      RECT 249.828 602.304 250.020 602.328 ;
    END
  END tx[274]
  PIN tx[275]
    DIRECTION INPUT ;
    USE SIGNAL ;
    SHAPE ABUTMENT ;
    PORT
      LAYER M4 ;
      RECT 249.828 604.512 250.020 604.536 ;
    END
  END tx[275]
  PIN tx[276]
    DIRECTION INPUT ;
    USE SIGNAL ;
    SHAPE ABUTMENT ;
    PORT
      LAYER M4 ;
      RECT 249.828 606.720 250.020 606.744 ;
    END
  END tx[276]
  PIN tx[277]
    DIRECTION INPUT ;
    USE SIGNAL ;
    SHAPE ABUTMENT ;
    PORT
      LAYER M4 ;
      RECT 249.828 608.928 250.020 608.952 ;
    END
  END tx[277]
  PIN tx[278]
    DIRECTION INPUT ;
    USE SIGNAL ;
    SHAPE ABUTMENT ;
    PORT
      LAYER M4 ;
      RECT 249.828 611.088 250.020 611.112 ;
    END
  END tx[278]
  PIN tx[279]
    DIRECTION INPUT ;
    USE SIGNAL ;
    SHAPE ABUTMENT ;
    PORT
      LAYER M4 ;
      RECT 249.828 613.296 250.020 613.320 ;
    END
  END tx[279]
  PIN tx[280]
    DIRECTION INPUT ;
    USE SIGNAL ;
    SHAPE ABUTMENT ;
    PORT
      LAYER M4 ;
      RECT 249.828 615.504 250.020 615.528 ;
    END
  END tx[280]
  PIN tx[281]
    DIRECTION INPUT ;
    USE SIGNAL ;
    SHAPE ABUTMENT ;
    PORT
      LAYER M4 ;
      RECT 249.828 617.712 250.020 617.736 ;
    END
  END tx[281]
  PIN tx[282]
    DIRECTION INPUT ;
    USE SIGNAL ;
    SHAPE ABUTMENT ;
    PORT
      LAYER M4 ;
      RECT 249.828 619.872 250.020 619.896 ;
    END
  END tx[282]
  PIN tx[283]
    DIRECTION INPUT ;
    USE SIGNAL ;
    SHAPE ABUTMENT ;
    PORT
      LAYER M4 ;
      RECT 249.828 622.080 250.020 622.104 ;
    END
  END tx[283]
  PIN tx[284]
    DIRECTION INPUT ;
    USE SIGNAL ;
    SHAPE ABUTMENT ;
    PORT
      LAYER M4 ;
      RECT 249.828 624.288 250.020 624.312 ;
    END
  END tx[284]
  PIN tx[285]
    DIRECTION INPUT ;
    USE SIGNAL ;
    SHAPE ABUTMENT ;
    PORT
      LAYER M4 ;
      RECT 249.828 626.496 250.020 626.520 ;
    END
  END tx[285]
  PIN tx[286]
    DIRECTION INPUT ;
    USE SIGNAL ;
    SHAPE ABUTMENT ;
    PORT
      LAYER M4 ;
      RECT 249.828 628.704 250.020 628.728 ;
    END
  END tx[286]
  PIN tx[287]
    DIRECTION INPUT ;
    USE SIGNAL ;
    SHAPE ABUTMENT ;
    PORT
      LAYER M4 ;
      RECT 249.828 630.864 250.020 630.888 ;
    END
  END tx[287]
  PIN tx[288]
    DIRECTION INPUT ;
    USE SIGNAL ;
    SHAPE ABUTMENT ;
    PORT
      LAYER M4 ;
      RECT 249.828 633.072 250.020 633.096 ;
    END
  END tx[288]
  PIN tx[289]
    DIRECTION INPUT ;
    USE SIGNAL ;
    SHAPE ABUTMENT ;
    PORT
      LAYER M4 ;
      RECT 249.828 635.280 250.020 635.304 ;
    END
  END tx[289]
  PIN tx[290]
    DIRECTION INPUT ;
    USE SIGNAL ;
    SHAPE ABUTMENT ;
    PORT
      LAYER M4 ;
      RECT 249.828 637.488 250.020 637.512 ;
    END
  END tx[290]
  PIN tx[291]
    DIRECTION INPUT ;
    USE SIGNAL ;
    SHAPE ABUTMENT ;
    PORT
      LAYER M4 ;
      RECT 249.828 639.648 250.020 639.672 ;
    END
  END tx[291]
  PIN tx[292]
    DIRECTION INPUT ;
    USE SIGNAL ;
    SHAPE ABUTMENT ;
    PORT
      LAYER M4 ;
      RECT 249.828 641.856 250.020 641.880 ;
    END
  END tx[292]
  PIN tx[293]
    DIRECTION INPUT ;
    USE SIGNAL ;
    SHAPE ABUTMENT ;
    PORT
      LAYER M4 ;
      RECT 249.828 644.064 250.020 644.088 ;
    END
  END tx[293]
  PIN tx[294]
    DIRECTION INPUT ;
    USE SIGNAL ;
    SHAPE ABUTMENT ;
    PORT
      LAYER M4 ;
      RECT 249.828 646.272 250.020 646.296 ;
    END
  END tx[294]
  PIN tx[295]
    DIRECTION INPUT ;
    USE SIGNAL ;
    SHAPE ABUTMENT ;
    PORT
      LAYER M4 ;
      RECT 249.828 648.432 250.020 648.456 ;
    END
  END tx[295]
  PIN tx[296]
    DIRECTION INPUT ;
    USE SIGNAL ;
    SHAPE ABUTMENT ;
    PORT
      LAYER M4 ;
      RECT 249.828 650.640 250.020 650.664 ;
    END
  END tx[296]
  PIN tx[297]
    DIRECTION INPUT ;
    USE SIGNAL ;
    SHAPE ABUTMENT ;
    PORT
      LAYER M4 ;
      RECT 249.828 652.848 250.020 652.872 ;
    END
  END tx[297]
  PIN tx[298]
    DIRECTION INPUT ;
    USE SIGNAL ;
    SHAPE ABUTMENT ;
    PORT
      LAYER M4 ;
      RECT 249.828 655.056 250.020 655.080 ;
    END
  END tx[298]
  PIN tx[299]
    DIRECTION INPUT ;
    USE SIGNAL ;
    SHAPE ABUTMENT ;
    PORT
      LAYER M4 ;
      RECT 249.828 657.216 250.020 657.240 ;
    END
  END tx[299]
  PIN tx[300]
    DIRECTION INPUT ;
    USE SIGNAL ;
    SHAPE ABUTMENT ;
    PORT
      LAYER M4 ;
      RECT 249.828 659.424 250.020 659.448 ;
    END
  END tx[300]
  PIN tx[301]
    DIRECTION INPUT ;
    USE SIGNAL ;
    SHAPE ABUTMENT ;
    PORT
      LAYER M4 ;
      RECT 249.828 661.632 250.020 661.656 ;
    END
  END tx[301]
  PIN tx[302]
    DIRECTION INPUT ;
    USE SIGNAL ;
    SHAPE ABUTMENT ;
    PORT
      LAYER M4 ;
      RECT 249.828 663.840 250.020 663.864 ;
    END
  END tx[302]
  PIN tx[303]
    DIRECTION INPUT ;
    USE SIGNAL ;
    SHAPE ABUTMENT ;
    PORT
      LAYER M4 ;
      RECT 249.828 666.000 250.020 666.024 ;
    END
  END tx[303]
  PIN tx[304]
    DIRECTION INPUT ;
    USE SIGNAL ;
    SHAPE ABUTMENT ;
    PORT
      LAYER M4 ;
      RECT 249.828 668.208 250.020 668.232 ;
    END
  END tx[304]
  PIN tx[305]
    DIRECTION INPUT ;
    USE SIGNAL ;
    SHAPE ABUTMENT ;
    PORT
      LAYER M4 ;
      RECT 249.828 670.416 250.020 670.440 ;
    END
  END tx[305]
  PIN tx[306]
    DIRECTION INPUT ;
    USE SIGNAL ;
    SHAPE ABUTMENT ;
    PORT
      LAYER M4 ;
      RECT 249.828 672.624 250.020 672.648 ;
    END
  END tx[306]
  PIN tx[307]
    DIRECTION INPUT ;
    USE SIGNAL ;
    SHAPE ABUTMENT ;
    PORT
      LAYER M4 ;
      RECT 249.828 674.784 250.020 674.808 ;
    END
  END tx[307]
  PIN tx[308]
    DIRECTION INPUT ;
    USE SIGNAL ;
    SHAPE ABUTMENT ;
    PORT
      LAYER M4 ;
      RECT 249.828 676.992 250.020 677.016 ;
    END
  END tx[308]
  PIN tx[309]
    DIRECTION INPUT ;
    USE SIGNAL ;
    SHAPE ABUTMENT ;
    PORT
      LAYER M4 ;
      RECT 249.828 679.200 250.020 679.224 ;
    END
  END tx[309]
  PIN tx[310]
    DIRECTION INPUT ;
    USE SIGNAL ;
    SHAPE ABUTMENT ;
    PORT
      LAYER M4 ;
      RECT 249.828 681.408 250.020 681.432 ;
    END
  END tx[310]
  PIN tx[311]
    DIRECTION INPUT ;
    USE SIGNAL ;
    SHAPE ABUTMENT ;
    PORT
      LAYER M4 ;
      RECT 249.828 683.568 250.020 683.592 ;
    END
  END tx[311]
  PIN tx[312]
    DIRECTION INPUT ;
    USE SIGNAL ;
    SHAPE ABUTMENT ;
    PORT
      LAYER M4 ;
      RECT 249.828 685.776 250.020 685.800 ;
    END
  END tx[312]
  PIN tx[313]
    DIRECTION INPUT ;
    USE SIGNAL ;
    SHAPE ABUTMENT ;
    PORT
      LAYER M4 ;
      RECT 249.828 687.984 250.020 688.008 ;
    END
  END tx[313]
  PIN tx[314]
    DIRECTION INPUT ;
    USE SIGNAL ;
    SHAPE ABUTMENT ;
    PORT
      LAYER M4 ;
      RECT 249.828 690.192 250.020 690.216 ;
    END
  END tx[314]
  PIN tx[315]
    DIRECTION INPUT ;
    USE SIGNAL ;
    SHAPE ABUTMENT ;
    PORT
      LAYER M4 ;
      RECT 249.828 692.400 250.020 692.424 ;
    END
  END tx[315]
  PIN tx[316]
    DIRECTION INPUT ;
    USE SIGNAL ;
    SHAPE ABUTMENT ;
    PORT
      LAYER M4 ;
      RECT 249.828 694.560 250.020 694.584 ;
    END
  END tx[316]
  PIN tx[317]
    DIRECTION INPUT ;
    USE SIGNAL ;
    SHAPE ABUTMENT ;
    PORT
      LAYER M4 ;
      RECT 249.828 696.768 250.020 696.792 ;
    END
  END tx[317]
  PIN tx[318]
    DIRECTION INPUT ;
    USE SIGNAL ;
    SHAPE ABUTMENT ;
    PORT
      LAYER M4 ;
      RECT 249.828 698.976 250.020 699.000 ;
    END
  END tx[318]
  PIN tx[319]
    DIRECTION INPUT ;
    USE SIGNAL ;
    SHAPE ABUTMENT ;
    PORT
      LAYER M4 ;
      RECT 249.828 701.184 250.020 701.208 ;
    END
  END tx[319]
  PIN tx[320]
    DIRECTION INPUT ;
    USE SIGNAL ;
    SHAPE ABUTMENT ;
    PORT
      LAYER M4 ;
      RECT 249.828 703.344 250.020 703.368 ;
    END
  END tx[320]
  PIN tx[321]
    DIRECTION INPUT ;
    USE SIGNAL ;
    SHAPE ABUTMENT ;
    PORT
      LAYER M4 ;
      RECT 249.828 705.552 250.020 705.576 ;
    END
  END tx[321]
  PIN tx[322]
    DIRECTION INPUT ;
    USE SIGNAL ;
    SHAPE ABUTMENT ;
    PORT
      LAYER M4 ;
      RECT 249.828 707.760 250.020 707.784 ;
    END
  END tx[322]
  PIN tx[323]
    DIRECTION INPUT ;
    USE SIGNAL ;
    SHAPE ABUTMENT ;
    PORT
      LAYER M4 ;
      RECT 249.828 709.968 250.020 709.992 ;
    END
  END tx[323]
  PIN tx[324]
    DIRECTION INPUT ;
    USE SIGNAL ;
    SHAPE ABUTMENT ;
    PORT
      LAYER M4 ;
      RECT 249.828 712.128 250.020 712.152 ;
    END
  END tx[324]
  PIN tx[325]
    DIRECTION INPUT ;
    USE SIGNAL ;
    SHAPE ABUTMENT ;
    PORT
      LAYER M4 ;
      RECT 249.828 714.336 250.020 714.360 ;
    END
  END tx[325]
  PIN tx[326]
    DIRECTION INPUT ;
    USE SIGNAL ;
    SHAPE ABUTMENT ;
    PORT
      LAYER M4 ;
      RECT 249.828 716.544 250.020 716.568 ;
    END
  END tx[326]
  PIN tx[327]
    DIRECTION INPUT ;
    USE SIGNAL ;
    SHAPE ABUTMENT ;
    PORT
      LAYER M4 ;
      RECT 249.828 718.752 250.020 718.776 ;
    END
  END tx[327]
  PIN tx[328]
    DIRECTION INPUT ;
    USE SIGNAL ;
    SHAPE ABUTMENT ;
    PORT
      LAYER M4 ;
      RECT 249.828 720.912 250.020 720.936 ;
    END
  END tx[328]
  PIN tx[329]
    DIRECTION INPUT ;
    USE SIGNAL ;
    SHAPE ABUTMENT ;
    PORT
      LAYER M4 ;
      RECT 249.828 723.120 250.020 723.144 ;
    END
  END tx[329]
  PIN tx[330]
    DIRECTION INPUT ;
    USE SIGNAL ;
    SHAPE ABUTMENT ;
    PORT
      LAYER M4 ;
      RECT 249.828 725.328 250.020 725.352 ;
    END
  END tx[330]
  PIN tx[331]
    DIRECTION INPUT ;
    USE SIGNAL ;
    SHAPE ABUTMENT ;
    PORT
      LAYER M4 ;
      RECT 249.828 727.536 250.020 727.560 ;
    END
  END tx[331]
  PIN tx[332]
    DIRECTION INPUT ;
    USE SIGNAL ;
    SHAPE ABUTMENT ;
    PORT
      LAYER M4 ;
      RECT 249.828 729.696 250.020 729.720 ;
    END
  END tx[332]
  PIN tx[333]
    DIRECTION INPUT ;
    USE SIGNAL ;
    SHAPE ABUTMENT ;
    PORT
      LAYER M4 ;
      RECT 249.828 731.904 250.020 731.928 ;
    END
  END tx[333]
  PIN tx[334]
    DIRECTION INPUT ;
    USE SIGNAL ;
    SHAPE ABUTMENT ;
    PORT
      LAYER M4 ;
      RECT 249.828 734.112 250.020 734.136 ;
    END
  END tx[334]
  PIN tx[335]
    DIRECTION INPUT ;
    USE SIGNAL ;
    SHAPE ABUTMENT ;
    PORT
      LAYER M4 ;
      RECT 249.828 736.320 250.020 736.344 ;
    END
  END tx[335]
  PIN tx[336]
    DIRECTION INPUT ;
    USE SIGNAL ;
    SHAPE ABUTMENT ;
    PORT
      LAYER M4 ;
      RECT 249.828 738.480 250.020 738.504 ;
    END
  END tx[336]
  PIN tx[337]
    DIRECTION INPUT ;
    USE SIGNAL ;
    SHAPE ABUTMENT ;
    PORT
      LAYER M4 ;
      RECT 249.828 740.688 250.020 740.712 ;
    END
  END tx[337]
  PIN tx[338]
    DIRECTION INPUT ;
    USE SIGNAL ;
    SHAPE ABUTMENT ;
    PORT
      LAYER M4 ;
      RECT 249.828 742.896 250.020 742.920 ;
    END
  END tx[338]
  PIN tx[339]
    DIRECTION INPUT ;
    USE SIGNAL ;
    SHAPE ABUTMENT ;
    PORT
      LAYER M4 ;
      RECT 249.828 745.104 250.020 745.128 ;
    END
  END tx[339]
  PIN tx[340]
    DIRECTION INPUT ;
    USE SIGNAL ;
    SHAPE ABUTMENT ;
    PORT
      LAYER M4 ;
      RECT 249.828 747.264 250.020 747.288 ;
    END
  END tx[340]
  PIN tx[341]
    DIRECTION INPUT ;
    USE SIGNAL ;
    SHAPE ABUTMENT ;
    PORT
      LAYER M4 ;
      RECT 249.828 749.472 250.020 749.496 ;
    END
  END tx[341]
  PIN tx[342]
    DIRECTION INPUT ;
    USE SIGNAL ;
    SHAPE ABUTMENT ;
    PORT
      LAYER M4 ;
      RECT 249.828 751.680 250.020 751.704 ;
    END
  END tx[342]
  PIN tx[343]
    DIRECTION INPUT ;
    USE SIGNAL ;
    SHAPE ABUTMENT ;
    PORT
      LAYER M4 ;
      RECT 249.828 753.888 250.020 753.912 ;
    END
  END tx[343]
  PIN tx[344]
    DIRECTION INPUT ;
    USE SIGNAL ;
    SHAPE ABUTMENT ;
    PORT
      LAYER M4 ;
      RECT 249.828 756.096 250.020 756.120 ;
    END
  END tx[344]
  PIN tx[345]
    DIRECTION INPUT ;
    USE SIGNAL ;
    SHAPE ABUTMENT ;
    PORT
      LAYER M4 ;
      RECT 249.828 758.256 250.020 758.280 ;
    END
  END tx[345]
  PIN tx[346]
    DIRECTION INPUT ;
    USE SIGNAL ;
    SHAPE ABUTMENT ;
    PORT
      LAYER M4 ;
      RECT 249.828 760.464 250.020 760.488 ;
    END
  END tx[346]
  PIN tx[347]
    DIRECTION INPUT ;
    USE SIGNAL ;
    SHAPE ABUTMENT ;
    PORT
      LAYER M4 ;
      RECT 249.828 762.672 250.020 762.696 ;
    END
  END tx[347]
  PIN tx[348]
    DIRECTION INPUT ;
    USE SIGNAL ;
    SHAPE ABUTMENT ;
    PORT
      LAYER M4 ;
      RECT 249.828 764.880 250.020 764.904 ;
    END
  END tx[348]
  PIN tx[349]
    DIRECTION INPUT ;
    USE SIGNAL ;
    SHAPE ABUTMENT ;
    PORT
      LAYER M4 ;
      RECT 249.828 767.040 250.020 767.064 ;
    END
  END tx[349]
  PIN tx[350]
    DIRECTION INPUT ;
    USE SIGNAL ;
    SHAPE ABUTMENT ;
    PORT
      LAYER M4 ;
      RECT 249.828 769.248 250.020 769.272 ;
    END
  END tx[350]
  PIN tx[351]
    DIRECTION INPUT ;
    USE SIGNAL ;
    SHAPE ABUTMENT ;
    PORT
      LAYER M4 ;
      RECT 249.828 771.456 250.020 771.480 ;
    END
  END tx[351]
  PIN tx[352]
    DIRECTION INPUT ;
    USE SIGNAL ;
    SHAPE ABUTMENT ;
    PORT
      LAYER M4 ;
      RECT 249.828 773.664 250.020 773.688 ;
    END
  END tx[352]
  PIN tx[353]
    DIRECTION INPUT ;
    USE SIGNAL ;
    SHAPE ABUTMENT ;
    PORT
      LAYER M4 ;
      RECT 249.828 775.824 250.020 775.848 ;
    END
  END tx[353]
  PIN tx[354]
    DIRECTION INPUT ;
    USE SIGNAL ;
    SHAPE ABUTMENT ;
    PORT
      LAYER M4 ;
      RECT 249.828 778.032 250.020 778.056 ;
    END
  END tx[354]
  PIN tx[355]
    DIRECTION INPUT ;
    USE SIGNAL ;
    SHAPE ABUTMENT ;
    PORT
      LAYER M4 ;
      RECT 249.828 780.240 250.020 780.264 ;
    END
  END tx[355]
  PIN tx[356]
    DIRECTION INPUT ;
    USE SIGNAL ;
    SHAPE ABUTMENT ;
    PORT
      LAYER M4 ;
      RECT 249.828 782.448 250.020 782.472 ;
    END
  END tx[356]
  PIN tx[357]
    DIRECTION INPUT ;
    USE SIGNAL ;
    SHAPE ABUTMENT ;
    PORT
      LAYER M4 ;
      RECT 249.828 784.608 250.020 784.632 ;
    END
  END tx[357]
  PIN tx[358]
    DIRECTION INPUT ;
    USE SIGNAL ;
    SHAPE ABUTMENT ;
    PORT
      LAYER M4 ;
      RECT 249.828 786.816 250.020 786.840 ;
    END
  END tx[358]
  PIN tx[359]
    DIRECTION INPUT ;
    USE SIGNAL ;
    SHAPE ABUTMENT ;
    PORT
      LAYER M4 ;
      RECT 249.828 789.024 250.020 789.048 ;
    END
  END tx[359]
  PIN tx[360]
    DIRECTION INPUT ;
    USE SIGNAL ;
    SHAPE ABUTMENT ;
    PORT
      LAYER M4 ;
      RECT 249.828 791.232 250.020 791.256 ;
    END
  END tx[360]
  PIN tx[361]
    DIRECTION INPUT ;
    USE SIGNAL ;
    SHAPE ABUTMENT ;
    PORT
      LAYER M4 ;
      RECT 249.828 793.392 250.020 793.416 ;
    END
  END tx[361]
  PIN tx[362]
    DIRECTION INPUT ;
    USE SIGNAL ;
    SHAPE ABUTMENT ;
    PORT
      LAYER M4 ;
      RECT 249.828 795.600 250.020 795.624 ;
    END
  END tx[362]
  PIN tx[363]
    DIRECTION INPUT ;
    USE SIGNAL ;
    SHAPE ABUTMENT ;
    PORT
      LAYER M4 ;
      RECT 249.828 797.808 250.020 797.832 ;
    END
  END tx[363]
  PIN tx[364]
    DIRECTION INPUT ;
    USE SIGNAL ;
    SHAPE ABUTMENT ;
    PORT
      LAYER M4 ;
      RECT 249.828 800.016 250.020 800.040 ;
    END
  END tx[364]
  PIN tx[365]
    DIRECTION INPUT ;
    USE SIGNAL ;
    SHAPE ABUTMENT ;
    PORT
      LAYER M4 ;
      RECT 249.828 802.176 250.020 802.200 ;
    END
  END tx[365]
  PIN tx[366]
    DIRECTION INPUT ;
    USE SIGNAL ;
    SHAPE ABUTMENT ;
    PORT
      LAYER M4 ;
      RECT 249.828 804.384 250.020 804.408 ;
    END
  END tx[366]
  PIN tx[367]
    DIRECTION INPUT ;
    USE SIGNAL ;
    SHAPE ABUTMENT ;
    PORT
      LAYER M4 ;
      RECT 249.828 806.592 250.020 806.616 ;
    END
  END tx[367]
  PIN tx[368]
    DIRECTION INPUT ;
    USE SIGNAL ;
    SHAPE ABUTMENT ;
    PORT
      LAYER M4 ;
      RECT 249.828 808.800 250.020 808.824 ;
    END
  END tx[368]
  PIN tx[369]
    DIRECTION INPUT ;
    USE SIGNAL ;
    SHAPE ABUTMENT ;
    PORT
      LAYER M4 ;
      RECT 249.828 810.960 250.020 810.984 ;
    END
  END tx[369]
  PIN tx[370]
    DIRECTION INPUT ;
    USE SIGNAL ;
    SHAPE ABUTMENT ;
    PORT
      LAYER M4 ;
      RECT 249.828 813.168 250.020 813.192 ;
    END
  END tx[370]
  PIN tx[371]
    DIRECTION INPUT ;
    USE SIGNAL ;
    SHAPE ABUTMENT ;
    PORT
      LAYER M4 ;
      RECT 249.828 815.376 250.020 815.400 ;
    END
  END tx[371]
  PIN tx[372]
    DIRECTION INPUT ;
    USE SIGNAL ;
    SHAPE ABUTMENT ;
    PORT
      LAYER M4 ;
      RECT 249.828 817.584 250.020 817.608 ;
    END
  END tx[372]
  PIN tx[373]
    DIRECTION INPUT ;
    USE SIGNAL ;
    SHAPE ABUTMENT ;
    PORT
      LAYER M4 ;
      RECT 249.828 819.792 250.020 819.816 ;
    END
  END tx[373]
  PIN tx[374]
    DIRECTION INPUT ;
    USE SIGNAL ;
    SHAPE ABUTMENT ;
    PORT
      LAYER M4 ;
      RECT 249.828 821.952 250.020 821.976 ;
    END
  END tx[374]
  PIN tx[375]
    DIRECTION INPUT ;
    USE SIGNAL ;
    SHAPE ABUTMENT ;
    PORT
      LAYER M4 ;
      RECT 249.828 824.160 250.020 824.184 ;
    END
  END tx[375]
  PIN tx[376]
    DIRECTION INPUT ;
    USE SIGNAL ;
    SHAPE ABUTMENT ;
    PORT
      LAYER M4 ;
      RECT 249.828 826.368 250.020 826.392 ;
    END
  END tx[376]
  PIN tx[377]
    DIRECTION INPUT ;
    USE SIGNAL ;
    SHAPE ABUTMENT ;
    PORT
      LAYER M4 ;
      RECT 249.828 828.576 250.020 828.600 ;
    END
  END tx[377]
  PIN tx[378]
    DIRECTION INPUT ;
    USE SIGNAL ;
    SHAPE ABUTMENT ;
    PORT
      LAYER M4 ;
      RECT 249.828 830.736 250.020 830.760 ;
    END
  END tx[378]
  PIN tx[379]
    DIRECTION INPUT ;
    USE SIGNAL ;
    SHAPE ABUTMENT ;
    PORT
      LAYER M4 ;
      RECT 249.828 832.944 250.020 832.968 ;
    END
  END tx[379]
  PIN tx[380]
    DIRECTION INPUT ;
    USE SIGNAL ;
    SHAPE ABUTMENT ;
    PORT
      LAYER M4 ;
      RECT 249.828 835.152 250.020 835.176 ;
    END
  END tx[380]
  PIN tx[381]
    DIRECTION INPUT ;
    USE SIGNAL ;
    SHAPE ABUTMENT ;
    PORT
      LAYER M4 ;
      RECT 249.828 837.360 250.020 837.384 ;
    END
  END tx[381]
  PIN tx[382]
    DIRECTION INPUT ;
    USE SIGNAL ;
    SHAPE ABUTMENT ;
    PORT
      LAYER M4 ;
      RECT 249.828 839.520 250.020 839.544 ;
    END
  END tx[382]
  PIN tx[383]
    DIRECTION INPUT ;
    USE SIGNAL ;
    SHAPE ABUTMENT ;
    PORT
      LAYER M4 ;
      RECT 249.828 841.728 250.020 841.752 ;
    END
  END tx[383]
  PIN tx[384]
    DIRECTION INPUT ;
    USE SIGNAL ;
    SHAPE ABUTMENT ;
    PORT
      LAYER M4 ;
      RECT 249.828 843.936 250.020 843.960 ;
    END
  END tx[384]
  PIN tx[385]
    DIRECTION INPUT ;
    USE SIGNAL ;
    SHAPE ABUTMENT ;
    PORT
      LAYER M4 ;
      RECT 249.828 846.144 250.020 846.168 ;
    END
  END tx[385]
  PIN tx[386]
    DIRECTION INPUT ;
    USE SIGNAL ;
    SHAPE ABUTMENT ;
    PORT
      LAYER M4 ;
      RECT 249.828 848.304 250.020 848.328 ;
    END
  END tx[386]
  PIN tx[387]
    DIRECTION INPUT ;
    USE SIGNAL ;
    SHAPE ABUTMENT ;
    PORT
      LAYER M4 ;
      RECT 249.828 850.512 250.020 850.536 ;
    END
  END tx[387]
  PIN tx[388]
    DIRECTION INPUT ;
    USE SIGNAL ;
    SHAPE ABUTMENT ;
    PORT
      LAYER M4 ;
      RECT 249.828 852.720 250.020 852.744 ;
    END
  END tx[388]
  PIN tx[389]
    DIRECTION INPUT ;
    USE SIGNAL ;
    SHAPE ABUTMENT ;
    PORT
      LAYER M4 ;
      RECT 249.828 854.928 250.020 854.952 ;
    END
  END tx[389]
  PIN tx[390]
    DIRECTION INPUT ;
    USE SIGNAL ;
    SHAPE ABUTMENT ;
    PORT
      LAYER M4 ;
      RECT 249.828 857.088 250.020 857.112 ;
    END
  END tx[390]
  PIN tx[391]
    DIRECTION INPUT ;
    USE SIGNAL ;
    SHAPE ABUTMENT ;
    PORT
      LAYER M4 ;
      RECT 249.828 859.296 250.020 859.320 ;
    END
  END tx[391]
  PIN tx[392]
    DIRECTION INPUT ;
    USE SIGNAL ;
    SHAPE ABUTMENT ;
    PORT
      LAYER M4 ;
      RECT 249.828 861.504 250.020 861.528 ;
    END
  END tx[392]
  PIN tx[393]
    DIRECTION INPUT ;
    USE SIGNAL ;
    SHAPE ABUTMENT ;
    PORT
      LAYER M4 ;
      RECT 249.828 863.712 250.020 863.736 ;
    END
  END tx[393]
  PIN tx[394]
    DIRECTION INPUT ;
    USE SIGNAL ;
    SHAPE ABUTMENT ;
    PORT
      LAYER M4 ;
      RECT 249.828 865.872 250.020 865.896 ;
    END
  END tx[394]
  PIN tx[395]
    DIRECTION INPUT ;
    USE SIGNAL ;
    SHAPE ABUTMENT ;
    PORT
      LAYER M4 ;
      RECT 249.828 868.080 250.020 868.104 ;
    END
  END tx[395]
  PIN tx[396]
    DIRECTION INPUT ;
    USE SIGNAL ;
    SHAPE ABUTMENT ;
    PORT
      LAYER M4 ;
      RECT 249.828 870.288 250.020 870.312 ;
    END
  END tx[396]
  PIN tx[397]
    DIRECTION INPUT ;
    USE SIGNAL ;
    SHAPE ABUTMENT ;
    PORT
      LAYER M4 ;
      RECT 249.828 872.496 250.020 872.520 ;
    END
  END tx[397]
  PIN tx[398]
    DIRECTION INPUT ;
    USE SIGNAL ;
    SHAPE ABUTMENT ;
    PORT
      LAYER M4 ;
      RECT 249.828 874.656 250.020 874.680 ;
    END
  END tx[398]
  PIN tx[399]
    DIRECTION INPUT ;
    USE SIGNAL ;
    SHAPE ABUTMENT ;
    PORT
      LAYER M4 ;
      RECT 249.828 876.864 250.020 876.888 ;
    END
  END tx[399]
  PIN tx[400]
    DIRECTION INPUT ;
    USE SIGNAL ;
    SHAPE ABUTMENT ;
    PORT
      LAYER M4 ;
      RECT 249.828 879.072 250.020 879.096 ;
    END
  END tx[400]
  PIN tx[401]
    DIRECTION INPUT ;
    USE SIGNAL ;
    SHAPE ABUTMENT ;
    PORT
      LAYER M4 ;
      RECT 249.828 881.280 250.020 881.304 ;
    END
  END tx[401]
  PIN tx[402]
    DIRECTION INPUT ;
    USE SIGNAL ;
    SHAPE ABUTMENT ;
    PORT
      LAYER M4 ;
      RECT 249.828 883.488 250.020 883.512 ;
    END
  END tx[402]
  PIN tx[403]
    DIRECTION INPUT ;
    USE SIGNAL ;
    SHAPE ABUTMENT ;
    PORT
      LAYER M4 ;
      RECT 249.828 885.648 250.020 885.672 ;
    END
  END tx[403]
  PIN tx[404]
    DIRECTION INPUT ;
    USE SIGNAL ;
    SHAPE ABUTMENT ;
    PORT
      LAYER M4 ;
      RECT 249.828 887.856 250.020 887.880 ;
    END
  END tx[404]
  PIN tx[405]
    DIRECTION INPUT ;
    USE SIGNAL ;
    SHAPE ABUTMENT ;
    PORT
      LAYER M4 ;
      RECT 249.828 890.064 250.020 890.088 ;
    END
  END tx[405]
  PIN tx[406]
    DIRECTION INPUT ;
    USE SIGNAL ;
    SHAPE ABUTMENT ;
    PORT
      LAYER M4 ;
      RECT 249.828 892.272 250.020 892.296 ;
    END
  END tx[406]
  PIN tx[407]
    DIRECTION INPUT ;
    USE SIGNAL ;
    SHAPE ABUTMENT ;
    PORT
      LAYER M4 ;
      RECT 249.828 894.432 250.020 894.456 ;
    END
  END tx[407]
  PIN tx[408]
    DIRECTION INPUT ;
    USE SIGNAL ;
    SHAPE ABUTMENT ;
    PORT
      LAYER M4 ;
      RECT 249.828 896.640 250.020 896.664 ;
    END
  END tx[408]
  PIN tx[409]
    DIRECTION INPUT ;
    USE SIGNAL ;
    SHAPE ABUTMENT ;
    PORT
      LAYER M4 ;
      RECT 249.828 898.848 250.020 898.872 ;
    END
  END tx[409]
  PIN tx[410]
    DIRECTION INPUT ;
    USE SIGNAL ;
    SHAPE ABUTMENT ;
    PORT
      LAYER M4 ;
      RECT 249.828 901.056 250.020 901.080 ;
    END
  END tx[410]
  PIN tx[411]
    DIRECTION INPUT ;
    USE SIGNAL ;
    SHAPE ABUTMENT ;
    PORT
      LAYER M4 ;
      RECT 249.828 903.216 250.020 903.240 ;
    END
  END tx[411]
  PIN tx[412]
    DIRECTION INPUT ;
    USE SIGNAL ;
    SHAPE ABUTMENT ;
    PORT
      LAYER M4 ;
      RECT 249.828 905.424 250.020 905.448 ;
    END
  END tx[412]
  PIN tx[413]
    DIRECTION INPUT ;
    USE SIGNAL ;
    SHAPE ABUTMENT ;
    PORT
      LAYER M4 ;
      RECT 249.828 907.632 250.020 907.656 ;
    END
  END tx[413]
  PIN tx[414]
    DIRECTION INPUT ;
    USE SIGNAL ;
    SHAPE ABUTMENT ;
    PORT
      LAYER M4 ;
      RECT 249.828 909.840 250.020 909.864 ;
    END
  END tx[414]
  PIN tx[415]
    DIRECTION INPUT ;
    USE SIGNAL ;
    SHAPE ABUTMENT ;
    PORT
      LAYER M4 ;
      RECT 249.828 912.000 250.020 912.024 ;
    END
  END tx[415]
  PIN tx[416]
    DIRECTION INPUT ;
    USE SIGNAL ;
    SHAPE ABUTMENT ;
    PORT
      LAYER M4 ;
      RECT 249.828 914.208 250.020 914.232 ;
    END
  END tx[416]
  PIN tx[417]
    DIRECTION INPUT ;
    USE SIGNAL ;
    SHAPE ABUTMENT ;
    PORT
      LAYER M4 ;
      RECT 249.828 916.416 250.020 916.440 ;
    END
  END tx[417]
  PIN tx[418]
    DIRECTION INPUT ;
    USE SIGNAL ;
    SHAPE ABUTMENT ;
    PORT
      LAYER M4 ;
      RECT 249.828 918.624 250.020 918.648 ;
    END
  END tx[418]
  PIN tx[419]
    DIRECTION INPUT ;
    USE SIGNAL ;
    SHAPE ABUTMENT ;
    PORT
      LAYER M4 ;
      RECT 249.828 920.784 250.020 920.808 ;
    END
  END tx[419]
  PIN tx[420]
    DIRECTION INPUT ;
    USE SIGNAL ;
    SHAPE ABUTMENT ;
    PORT
      LAYER M4 ;
      RECT 249.828 922.992 250.020 923.016 ;
    END
  END tx[420]
  PIN tx[421]
    DIRECTION INPUT ;
    USE SIGNAL ;
    SHAPE ABUTMENT ;
    PORT
      LAYER M4 ;
      RECT 249.828 925.200 250.020 925.224 ;
    END
  END tx[421]
  PIN tx[422]
    DIRECTION INPUT ;
    USE SIGNAL ;
    SHAPE ABUTMENT ;
    PORT
      LAYER M4 ;
      RECT 249.828 927.408 250.020 927.432 ;
    END
  END tx[422]
  PIN tx[423]
    DIRECTION INPUT ;
    USE SIGNAL ;
    SHAPE ABUTMENT ;
    PORT
      LAYER M4 ;
      RECT 249.828 929.568 250.020 929.592 ;
    END
  END tx[423]
  PIN tx[424]
    DIRECTION INPUT ;
    USE SIGNAL ;
    SHAPE ABUTMENT ;
    PORT
      LAYER M4 ;
      RECT 249.828 931.776 250.020 931.800 ;
    END
  END tx[424]
  PIN tx[425]
    DIRECTION INPUT ;
    USE SIGNAL ;
    SHAPE ABUTMENT ;
    PORT
      LAYER M4 ;
      RECT 249.828 933.984 250.020 934.008 ;
    END
  END tx[425]
  PIN tx[426]
    DIRECTION INPUT ;
    USE SIGNAL ;
    SHAPE ABUTMENT ;
    PORT
      LAYER M4 ;
      RECT 249.828 936.192 250.020 936.216 ;
    END
  END tx[426]
  PIN tx[427]
    DIRECTION INPUT ;
    USE SIGNAL ;
    SHAPE ABUTMENT ;
    PORT
      LAYER M4 ;
      RECT 249.828 938.400 250.020 938.424 ;
    END
  END tx[427]
  PIN tx[428]
    DIRECTION INPUT ;
    USE SIGNAL ;
    SHAPE ABUTMENT ;
    PORT
      LAYER M4 ;
      RECT 249.828 940.560 250.020 940.584 ;
    END
  END tx[428]
  PIN tx[429]
    DIRECTION INPUT ;
    USE SIGNAL ;
    SHAPE ABUTMENT ;
    PORT
      LAYER M4 ;
      RECT 249.828 942.768 250.020 942.792 ;
    END
  END tx[429]
  PIN tx[430]
    DIRECTION INPUT ;
    USE SIGNAL ;
    SHAPE ABUTMENT ;
    PORT
      LAYER M4 ;
      RECT 249.828 944.976 250.020 945.000 ;
    END
  END tx[430]
  PIN tx[431]
    DIRECTION INPUT ;
    USE SIGNAL ;
    SHAPE ABUTMENT ;
    PORT
      LAYER M4 ;
      RECT 249.828 947.184 250.020 947.208 ;
    END
  END tx[431]
  PIN tx[432]
    DIRECTION INPUT ;
    USE SIGNAL ;
    SHAPE ABUTMENT ;
    PORT
      LAYER M4 ;
      RECT 249.828 949.344 250.020 949.368 ;
    END
  END tx[432]
  PIN tx[433]
    DIRECTION INPUT ;
    USE SIGNAL ;
    SHAPE ABUTMENT ;
    PORT
      LAYER M4 ;
      RECT 249.828 951.552 250.020 951.576 ;
    END
  END tx[433]
  PIN tx[434]
    DIRECTION INPUT ;
    USE SIGNAL ;
    SHAPE ABUTMENT ;
    PORT
      LAYER M4 ;
      RECT 249.828 953.760 250.020 953.784 ;
    END
  END tx[434]
  PIN tx[435]
    DIRECTION INPUT ;
    USE SIGNAL ;
    SHAPE ABUTMENT ;
    PORT
      LAYER M4 ;
      RECT 249.828 955.968 250.020 955.992 ;
    END
  END tx[435]
  PIN tx[436]
    DIRECTION INPUT ;
    USE SIGNAL ;
    SHAPE ABUTMENT ;
    PORT
      LAYER M4 ;
      RECT 249.828 958.128 250.020 958.152 ;
    END
  END tx[436]
  PIN tx[437]
    DIRECTION INPUT ;
    USE SIGNAL ;
    SHAPE ABUTMENT ;
    PORT
      LAYER M4 ;
      RECT 249.828 960.336 250.020 960.360 ;
    END
  END tx[437]
  PIN tx[438]
    DIRECTION INPUT ;
    USE SIGNAL ;
    SHAPE ABUTMENT ;
    PORT
      LAYER M4 ;
      RECT 249.828 962.544 250.020 962.568 ;
    END
  END tx[438]
  PIN tx[439]
    DIRECTION INPUT ;
    USE SIGNAL ;
    SHAPE ABUTMENT ;
    PORT
      LAYER M4 ;
      RECT 249.828 964.752 250.020 964.776 ;
    END
  END tx[439]
  PIN tx[440]
    DIRECTION INPUT ;
    USE SIGNAL ;
    SHAPE ABUTMENT ;
    PORT
      LAYER M4 ;
      RECT 249.828 966.912 250.020 966.936 ;
    END
  END tx[440]
  PIN tx[441]
    DIRECTION INPUT ;
    USE SIGNAL ;
    SHAPE ABUTMENT ;
    PORT
      LAYER M4 ;
      RECT 249.828 969.120 250.020 969.144 ;
    END
  END tx[441]
  PIN tx[442]
    DIRECTION INPUT ;
    USE SIGNAL ;
    SHAPE ABUTMENT ;
    PORT
      LAYER M4 ;
      RECT 249.828 971.328 250.020 971.352 ;
    END
  END tx[442]
  PIN tx[443]
    DIRECTION INPUT ;
    USE SIGNAL ;
    SHAPE ABUTMENT ;
    PORT
      LAYER M4 ;
      RECT 249.828 973.536 250.020 973.560 ;
    END
  END tx[443]
  PIN tx[444]
    DIRECTION INPUT ;
    USE SIGNAL ;
    SHAPE ABUTMENT ;
    PORT
      LAYER M4 ;
      RECT 249.828 975.696 250.020 975.720 ;
    END
  END tx[444]
  PIN tx[445]
    DIRECTION INPUT ;
    USE SIGNAL ;
    SHAPE ABUTMENT ;
    PORT
      LAYER M4 ;
      RECT 249.828 977.904 250.020 977.928 ;
    END
  END tx[445]
  PIN tx[446]
    DIRECTION INPUT ;
    USE SIGNAL ;
    SHAPE ABUTMENT ;
    PORT
      LAYER M4 ;
      RECT 249.828 980.112 250.020 980.136 ;
    END
  END tx[446]
  PIN tx[447]
    DIRECTION INPUT ;
    USE SIGNAL ;
    SHAPE ABUTMENT ;
    PORT
      LAYER M4 ;
      RECT 249.828 982.320 250.020 982.344 ;
    END
  END tx[447]
  PIN tx[448]
    DIRECTION INPUT ;
    USE SIGNAL ;
    SHAPE ABUTMENT ;
    PORT
      LAYER M4 ;
      RECT 249.828 984.480 250.020 984.504 ;
    END
  END tx[448]
  PIN tx[449]
    DIRECTION INPUT ;
    USE SIGNAL ;
    SHAPE ABUTMENT ;
    PORT
      LAYER M4 ;
      RECT 249.828 986.688 250.020 986.712 ;
    END
  END tx[449]
  PIN tx[450]
    DIRECTION INPUT ;
    USE SIGNAL ;
    SHAPE ABUTMENT ;
    PORT
      LAYER M4 ;
      RECT 249.828 988.896 250.020 988.920 ;
    END
  END tx[450]
  PIN tx[451]
    DIRECTION INPUT ;
    USE SIGNAL ;
    SHAPE ABUTMENT ;
    PORT
      LAYER M4 ;
      RECT 249.828 991.104 250.020 991.128 ;
    END
  END tx[451]
  PIN tx[452]
    DIRECTION INPUT ;
    USE SIGNAL ;
    SHAPE ABUTMENT ;
    PORT
      LAYER M4 ;
      RECT 249.828 993.264 250.020 993.288 ;
    END
  END tx[452]
  PIN tx[453]
    DIRECTION INPUT ;
    USE SIGNAL ;
    SHAPE ABUTMENT ;
    PORT
      LAYER M4 ;
      RECT 249.828 995.472 250.020 995.496 ;
    END
  END tx[453]
  PIN tx[454]
    DIRECTION INPUT ;
    USE SIGNAL ;
    SHAPE ABUTMENT ;
    PORT
      LAYER M4 ;
      RECT 249.828 997.680 250.020 997.704 ;
    END
  END tx[454]
  PIN tx[455]
    DIRECTION INPUT ;
    USE SIGNAL ;
    SHAPE ABUTMENT ;
    PORT
      LAYER M4 ;
      RECT 249.828 999.888 250.020 999.912 ;
    END
  END tx[455]
  PIN tx[456]
    DIRECTION INPUT ;
    USE SIGNAL ;
    SHAPE ABUTMENT ;
    PORT
      LAYER M4 ;
      RECT 249.828 1002.096 250.020 1002.120 ;
    END
  END tx[456]
  PIN tx[457]
    DIRECTION INPUT ;
    USE SIGNAL ;
    SHAPE ABUTMENT ;
    PORT
      LAYER M4 ;
      RECT 249.828 1004.256 250.020 1004.280 ;
    END
  END tx[457]
  PIN tx[458]
    DIRECTION INPUT ;
    USE SIGNAL ;
    SHAPE ABUTMENT ;
    PORT
      LAYER M4 ;
      RECT 249.828 1006.464 250.020 1006.488 ;
    END
  END tx[458]
  PIN tx[459]
    DIRECTION INPUT ;
    USE SIGNAL ;
    SHAPE ABUTMENT ;
    PORT
      LAYER M4 ;
      RECT 249.828 1008.672 250.020 1008.696 ;
    END
  END tx[459]
  PIN tx[460]
    DIRECTION INPUT ;
    USE SIGNAL ;
    SHAPE ABUTMENT ;
    PORT
      LAYER M4 ;
      RECT 249.828 1010.880 250.020 1010.904 ;
    END
  END tx[460]
  PIN tx[461]
    DIRECTION INPUT ;
    USE SIGNAL ;
    SHAPE ABUTMENT ;
    PORT
      LAYER M4 ;
      RECT 249.828 1013.040 250.020 1013.064 ;
    END
  END tx[461]
  PIN tx[462]
    DIRECTION INPUT ;
    USE SIGNAL ;
    SHAPE ABUTMENT ;
    PORT
      LAYER M4 ;
      RECT 249.828 1015.248 250.020 1015.272 ;
    END
  END tx[462]
  PIN tx[463]
    DIRECTION INPUT ;
    USE SIGNAL ;
    SHAPE ABUTMENT ;
    PORT
      LAYER M4 ;
      RECT 249.828 1017.456 250.020 1017.480 ;
    END
  END tx[463]
  PIN tx[464]
    DIRECTION INPUT ;
    USE SIGNAL ;
    SHAPE ABUTMENT ;
    PORT
      LAYER M4 ;
      RECT 249.828 1019.664 250.020 1019.688 ;
    END
  END tx[464]
  PIN tx[465]
    DIRECTION INPUT ;
    USE SIGNAL ;
    SHAPE ABUTMENT ;
    PORT
      LAYER M4 ;
      RECT 249.828 1021.824 250.020 1021.848 ;
    END
  END tx[465]
  PIN tx[466]
    DIRECTION INPUT ;
    USE SIGNAL ;
    SHAPE ABUTMENT ;
    PORT
      LAYER M4 ;
      RECT 249.828 1024.032 250.020 1024.056 ;
    END
  END tx[466]
  PIN tx[467]
    DIRECTION INPUT ;
    USE SIGNAL ;
    SHAPE ABUTMENT ;
    PORT
      LAYER M4 ;
      RECT 249.828 1026.240 250.020 1026.264 ;
    END
  END tx[467]
  PIN tx[468]
    DIRECTION INPUT ;
    USE SIGNAL ;
    SHAPE ABUTMENT ;
    PORT
      LAYER M4 ;
      RECT 249.828 1028.448 250.020 1028.472 ;
    END
  END tx[468]
  PIN tx[469]
    DIRECTION INPUT ;
    USE SIGNAL ;
    SHAPE ABUTMENT ;
    PORT
      LAYER M4 ;
      RECT 249.828 1030.608 250.020 1030.632 ;
    END
  END tx[469]
  PIN tx[470]
    DIRECTION INPUT ;
    USE SIGNAL ;
    SHAPE ABUTMENT ;
    PORT
      LAYER M4 ;
      RECT 249.828 1032.816 250.020 1032.840 ;
    END
  END tx[470]
  PIN tx[471]
    DIRECTION INPUT ;
    USE SIGNAL ;
    SHAPE ABUTMENT ;
    PORT
      LAYER M4 ;
      RECT 249.828 1035.024 250.020 1035.048 ;
    END
  END tx[471]
  PIN tx[472]
    DIRECTION INPUT ;
    USE SIGNAL ;
    SHAPE ABUTMENT ;
    PORT
      LAYER M4 ;
      RECT 249.828 1037.232 250.020 1037.256 ;
    END
  END tx[472]
  PIN tx[473]
    DIRECTION INPUT ;
    USE SIGNAL ;
    SHAPE ABUTMENT ;
    PORT
      LAYER M4 ;
      RECT 249.828 1039.392 250.020 1039.416 ;
    END
  END tx[473]
  PIN tx[474]
    DIRECTION INPUT ;
    USE SIGNAL ;
    SHAPE ABUTMENT ;
    PORT
      LAYER M4 ;
      RECT 249.828 1041.600 250.020 1041.624 ;
    END
  END tx[474]
  PIN tx[475]
    DIRECTION INPUT ;
    USE SIGNAL ;
    SHAPE ABUTMENT ;
    PORT
      LAYER M4 ;
      RECT 249.828 1043.808 250.020 1043.832 ;
    END
  END tx[475]
  PIN tx[476]
    DIRECTION INPUT ;
    USE SIGNAL ;
    SHAPE ABUTMENT ;
    PORT
      LAYER M4 ;
      RECT 249.828 1046.016 250.020 1046.040 ;
    END
  END tx[476]
  PIN tx[477]
    DIRECTION INPUT ;
    USE SIGNAL ;
    SHAPE ABUTMENT ;
    PORT
      LAYER M4 ;
      RECT 249.828 1048.176 250.020 1048.200 ;
    END
  END tx[477]
  PIN tx[478]
    DIRECTION INPUT ;
    USE SIGNAL ;
    SHAPE ABUTMENT ;
    PORT
      LAYER M4 ;
      RECT 249.828 1050.384 250.020 1050.408 ;
    END
  END tx[478]
  PIN tx[479]
    DIRECTION INPUT ;
    USE SIGNAL ;
    SHAPE ABUTMENT ;
    PORT
      LAYER M4 ;
      RECT 249.828 1052.592 250.020 1052.616 ;
    END
  END tx[479]
  PIN tx[480]
    DIRECTION INPUT ;
    USE SIGNAL ;
    SHAPE ABUTMENT ;
    PORT
      LAYER M4 ;
      RECT 249.828 1054.800 250.020 1054.824 ;
    END
  END tx[480]
  PIN tx[481]
    DIRECTION INPUT ;
    USE SIGNAL ;
    SHAPE ABUTMENT ;
    PORT
      LAYER M4 ;
      RECT 249.828 1056.960 250.020 1056.984 ;
    END
  END tx[481]
  PIN tx[482]
    DIRECTION INPUT ;
    USE SIGNAL ;
    SHAPE ABUTMENT ;
    PORT
      LAYER M4 ;
      RECT 249.828 1059.168 250.020 1059.192 ;
    END
  END tx[482]
  PIN tx[483]
    DIRECTION INPUT ;
    USE SIGNAL ;
    SHAPE ABUTMENT ;
    PORT
      LAYER M4 ;
      RECT 249.828 1061.376 250.020 1061.400 ;
    END
  END tx[483]
  PIN tx[484]
    DIRECTION INPUT ;
    USE SIGNAL ;
    SHAPE ABUTMENT ;
    PORT
      LAYER M4 ;
      RECT 249.828 1063.584 250.020 1063.608 ;
    END
  END tx[484]
  PIN tx[485]
    DIRECTION INPUT ;
    USE SIGNAL ;
    SHAPE ABUTMENT ;
    PORT
      LAYER M4 ;
      RECT 249.828 1065.792 250.020 1065.816 ;
    END
  END tx[485]
  PIN tx[486]
    DIRECTION INPUT ;
    USE SIGNAL ;
    SHAPE ABUTMENT ;
    PORT
      LAYER M4 ;
      RECT 249.828 1067.952 250.020 1067.976 ;
    END
  END tx[486]
  PIN tx[487]
    DIRECTION INPUT ;
    USE SIGNAL ;
    SHAPE ABUTMENT ;
    PORT
      LAYER M4 ;
      RECT 249.828 1070.160 250.020 1070.184 ;
    END
  END tx[487]
  PIN tx[488]
    DIRECTION INPUT ;
    USE SIGNAL ;
    SHAPE ABUTMENT ;
    PORT
      LAYER M4 ;
      RECT 249.828 1072.368 250.020 1072.392 ;
    END
  END tx[488]
  PIN tx[489]
    DIRECTION INPUT ;
    USE SIGNAL ;
    SHAPE ABUTMENT ;
    PORT
      LAYER M4 ;
      RECT 249.828 1074.576 250.020 1074.600 ;
    END
  END tx[489]
  PIN tx[490]
    DIRECTION INPUT ;
    USE SIGNAL ;
    SHAPE ABUTMENT ;
    PORT
      LAYER M4 ;
      RECT 249.828 1076.736 250.020 1076.760 ;
    END
  END tx[490]
  PIN tx[491]
    DIRECTION INPUT ;
    USE SIGNAL ;
    SHAPE ABUTMENT ;
    PORT
      LAYER M4 ;
      RECT 249.828 1078.944 250.020 1078.968 ;
    END
  END tx[491]
  PIN tx[492]
    DIRECTION INPUT ;
    USE SIGNAL ;
    SHAPE ABUTMENT ;
    PORT
      LAYER M4 ;
      RECT 249.828 1081.152 250.020 1081.176 ;
    END
  END tx[492]
  PIN tx[493]
    DIRECTION INPUT ;
    USE SIGNAL ;
    SHAPE ABUTMENT ;
    PORT
      LAYER M4 ;
      RECT 249.828 1083.360 250.020 1083.384 ;
    END
  END tx[493]
  PIN tx[494]
    DIRECTION INPUT ;
    USE SIGNAL ;
    SHAPE ABUTMENT ;
    PORT
      LAYER M4 ;
      RECT 249.828 1085.520 250.020 1085.544 ;
    END
  END tx[494]
  PIN tx[495]
    DIRECTION INPUT ;
    USE SIGNAL ;
    SHAPE ABUTMENT ;
    PORT
      LAYER M4 ;
      RECT 249.828 1087.728 250.020 1087.752 ;
    END
  END tx[495]
  PIN tx[496]
    DIRECTION INPUT ;
    USE SIGNAL ;
    SHAPE ABUTMENT ;
    PORT
      LAYER M4 ;
      RECT 249.828 1089.936 250.020 1089.960 ;
    END
  END tx[496]
  PIN tx[497]
    DIRECTION INPUT ;
    USE SIGNAL ;
    SHAPE ABUTMENT ;
    PORT
      LAYER M4 ;
      RECT 249.828 1092.144 250.020 1092.168 ;
    END
  END tx[497]
  PIN tx[498]
    DIRECTION INPUT ;
    USE SIGNAL ;
    SHAPE ABUTMENT ;
    PORT
      LAYER M4 ;
      RECT 249.828 1094.304 250.020 1094.328 ;
    END
  END tx[498]
  PIN tx[499]
    DIRECTION INPUT ;
    USE SIGNAL ;
    SHAPE ABUTMENT ;
    PORT
      LAYER M4 ;
      RECT 249.828 1096.512 250.020 1096.536 ;
    END
  END tx[499]
  PIN tx[500]
    DIRECTION INPUT ;
    USE SIGNAL ;
    SHAPE ABUTMENT ;
    PORT
      LAYER M4 ;
      RECT 249.828 1098.720 250.020 1098.744 ;
    END
  END tx[500]
  PIN tx[501]
    DIRECTION INPUT ;
    USE SIGNAL ;
    SHAPE ABUTMENT ;
    PORT
      LAYER M4 ;
      RECT 249.828 1100.928 250.020 1100.952 ;
    END
  END tx[501]
  PIN tx[502]
    DIRECTION INPUT ;
    USE SIGNAL ;
    SHAPE ABUTMENT ;
    PORT
      LAYER M4 ;
      RECT 249.828 1103.088 250.020 1103.112 ;
    END
  END tx[502]
  PIN tx[503]
    DIRECTION INPUT ;
    USE SIGNAL ;
    SHAPE ABUTMENT ;
    PORT
      LAYER M4 ;
      RECT 249.828 1105.296 250.020 1105.320 ;
    END
  END tx[503]
  PIN tx[504]
    DIRECTION INPUT ;
    USE SIGNAL ;
    SHAPE ABUTMENT ;
    PORT
      LAYER M4 ;
      RECT 249.828 1107.504 250.020 1107.528 ;
    END
  END tx[504]
  PIN tx[505]
    DIRECTION INPUT ;
    USE SIGNAL ;
    SHAPE ABUTMENT ;
    PORT
      LAYER M4 ;
      RECT 249.828 1109.712 250.020 1109.736 ;
    END
  END tx[505]
  PIN tx[506]
    DIRECTION INPUT ;
    USE SIGNAL ;
    SHAPE ABUTMENT ;
    PORT
      LAYER M4 ;
      RECT 249.828 1111.872 250.020 1111.896 ;
    END
  END tx[506]
  PIN tx[507]
    DIRECTION INPUT ;
    USE SIGNAL ;
    SHAPE ABUTMENT ;
    PORT
      LAYER M4 ;
      RECT 249.828 1114.080 250.020 1114.104 ;
    END
  END tx[507]
  PIN tx[508]
    DIRECTION INPUT ;
    USE SIGNAL ;
    SHAPE ABUTMENT ;
    PORT
      LAYER M4 ;
      RECT 249.828 1116.288 250.020 1116.312 ;
    END
  END tx[508]
  PIN tx[509]
    DIRECTION INPUT ;
    USE SIGNAL ;
    SHAPE ABUTMENT ;
    PORT
      LAYER M4 ;
      RECT 249.828 1118.496 250.020 1118.520 ;
    END
  END tx[509]
  PIN tx[510]
    DIRECTION INPUT ;
    USE SIGNAL ;
    SHAPE ABUTMENT ;
    PORT
      LAYER M4 ;
      RECT 249.828 1120.656 250.020 1120.680 ;
    END
  END tx[510]
  PIN tx[511]
    DIRECTION INPUT ;
    USE SIGNAL ;
    SHAPE ABUTMENT ;
    PORT
      LAYER M4 ;
      RECT 249.828 1122.864 250.020 1122.888 ;
    END
  END tx[511]
  PIN rx[0]
    DIRECTION OUTPUT ;
    USE SIGNAL ;
    SHAPE ABUTMENT ;
    PORT
      LAYER M4 ;
      RECT 249.828 1125.072 250.020 1125.096 ;
    END
  END rx[0]
  PIN rx[1]
    DIRECTION OUTPUT ;
    USE SIGNAL ;
    SHAPE ABUTMENT ;
    PORT
      LAYER M4 ;
      RECT 249.828 1127.280 250.020 1127.304 ;
    END
  END rx[1]
  PIN rx[2]
    DIRECTION OUTPUT ;
    USE SIGNAL ;
    SHAPE ABUTMENT ;
    PORT
      LAYER M4 ;
      RECT 249.828 1129.488 250.020 1129.512 ;
    END
  END rx[2]
  PIN rx[3]
    DIRECTION OUTPUT ;
    USE SIGNAL ;
    SHAPE ABUTMENT ;
    PORT
      LAYER M4 ;
      RECT 249.828 1131.648 250.020 1131.672 ;
    END
  END rx[3]
  PIN rx[4]
    DIRECTION OUTPUT ;
    USE SIGNAL ;
    SHAPE ABUTMENT ;
    PORT
      LAYER M4 ;
      RECT 249.828 1133.856 250.020 1133.880 ;
    END
  END rx[4]
  PIN rx[5]
    DIRECTION OUTPUT ;
    USE SIGNAL ;
    SHAPE ABUTMENT ;
    PORT
      LAYER M4 ;
      RECT 249.828 1136.064 250.020 1136.088 ;
    END
  END rx[5]
  PIN rx[6]
    DIRECTION OUTPUT ;
    USE SIGNAL ;
    SHAPE ABUTMENT ;
    PORT
      LAYER M4 ;
      RECT 249.828 1138.272 250.020 1138.296 ;
    END
  END rx[6]
  PIN rx[7]
    DIRECTION OUTPUT ;
    USE SIGNAL ;
    SHAPE ABUTMENT ;
    PORT
      LAYER M4 ;
      RECT 249.828 1140.432 250.020 1140.456 ;
    END
  END rx[7]
  PIN rx[8]
    DIRECTION OUTPUT ;
    USE SIGNAL ;
    SHAPE ABUTMENT ;
    PORT
      LAYER M4 ;
      RECT 249.828 1142.640 250.020 1142.664 ;
    END
  END rx[8]
  PIN rx[9]
    DIRECTION OUTPUT ;
    USE SIGNAL ;
    SHAPE ABUTMENT ;
    PORT
      LAYER M4 ;
      RECT 249.828 1144.848 250.020 1144.872 ;
    END
  END rx[9]
  PIN rx[10]
    DIRECTION OUTPUT ;
    USE SIGNAL ;
    SHAPE ABUTMENT ;
    PORT
      LAYER M4 ;
      RECT 249.828 1147.056 250.020 1147.080 ;
    END
  END rx[10]
  PIN rx[11]
    DIRECTION OUTPUT ;
    USE SIGNAL ;
    SHAPE ABUTMENT ;
    PORT
      LAYER M4 ;
      RECT 249.828 1149.216 250.020 1149.240 ;
    END
  END rx[11]
  PIN rx[12]
    DIRECTION OUTPUT ;
    USE SIGNAL ;
    SHAPE ABUTMENT ;
    PORT
      LAYER M4 ;
      RECT 249.828 1151.424 250.020 1151.448 ;
    END
  END rx[12]
  PIN rx[13]
    DIRECTION OUTPUT ;
    USE SIGNAL ;
    SHAPE ABUTMENT ;
    PORT
      LAYER M4 ;
      RECT 249.828 1153.632 250.020 1153.656 ;
    END
  END rx[13]
  PIN rx[14]
    DIRECTION OUTPUT ;
    USE SIGNAL ;
    SHAPE ABUTMENT ;
    PORT
      LAYER M4 ;
      RECT 249.828 1155.840 250.020 1155.864 ;
    END
  END rx[14]
  PIN rx[15]
    DIRECTION OUTPUT ;
    USE SIGNAL ;
    SHAPE ABUTMENT ;
    PORT
      LAYER M4 ;
      RECT 249.828 1158.000 250.020 1158.024 ;
    END
  END rx[15]
  PIN rx[16]
    DIRECTION OUTPUT ;
    USE SIGNAL ;
    SHAPE ABUTMENT ;
    PORT
      LAYER M4 ;
      RECT 249.828 1160.208 250.020 1160.232 ;
    END
  END rx[16]
  PIN rx[17]
    DIRECTION OUTPUT ;
    USE SIGNAL ;
    SHAPE ABUTMENT ;
    PORT
      LAYER M4 ;
      RECT 249.828 1162.416 250.020 1162.440 ;
    END
  END rx[17]
  PIN rx[18]
    DIRECTION OUTPUT ;
    USE SIGNAL ;
    SHAPE ABUTMENT ;
    PORT
      LAYER M4 ;
      RECT 249.828 1164.624 250.020 1164.648 ;
    END
  END rx[18]
  PIN rx[19]
    DIRECTION OUTPUT ;
    USE SIGNAL ;
    SHAPE ABUTMENT ;
    PORT
      LAYER M4 ;
      RECT 249.828 1166.784 250.020 1166.808 ;
    END
  END rx[19]
  PIN rx[20]
    DIRECTION OUTPUT ;
    USE SIGNAL ;
    SHAPE ABUTMENT ;
    PORT
      LAYER M4 ;
      RECT 249.828 1168.992 250.020 1169.016 ;
    END
  END rx[20]
  PIN rx[21]
    DIRECTION OUTPUT ;
    USE SIGNAL ;
    SHAPE ABUTMENT ;
    PORT
      LAYER M4 ;
      RECT 249.828 1171.200 250.020 1171.224 ;
    END
  END rx[21]
  PIN rx[22]
    DIRECTION OUTPUT ;
    USE SIGNAL ;
    SHAPE ABUTMENT ;
    PORT
      LAYER M4 ;
      RECT 249.828 1173.408 250.020 1173.432 ;
    END
  END rx[22]
  PIN rx[23]
    DIRECTION OUTPUT ;
    USE SIGNAL ;
    SHAPE ABUTMENT ;
    PORT
      LAYER M4 ;
      RECT 249.828 1175.568 250.020 1175.592 ;
    END
  END rx[23]
  PIN rx[24]
    DIRECTION OUTPUT ;
    USE SIGNAL ;
    SHAPE ABUTMENT ;
    PORT
      LAYER M4 ;
      RECT 249.828 1177.776 250.020 1177.800 ;
    END
  END rx[24]
  PIN rx[25]
    DIRECTION OUTPUT ;
    USE SIGNAL ;
    SHAPE ABUTMENT ;
    PORT
      LAYER M4 ;
      RECT 249.828 1179.984 250.020 1180.008 ;
    END
  END rx[25]
  PIN rx[26]
    DIRECTION OUTPUT ;
    USE SIGNAL ;
    SHAPE ABUTMENT ;
    PORT
      LAYER M4 ;
      RECT 249.828 1182.192 250.020 1182.216 ;
    END
  END rx[26]
  PIN rx[27]
    DIRECTION OUTPUT ;
    USE SIGNAL ;
    SHAPE ABUTMENT ;
    PORT
      LAYER M4 ;
      RECT 249.828 1184.352 250.020 1184.376 ;
    END
  END rx[27]
  PIN rx[28]
    DIRECTION OUTPUT ;
    USE SIGNAL ;
    SHAPE ABUTMENT ;
    PORT
      LAYER M4 ;
      RECT 249.828 1186.560 250.020 1186.584 ;
    END
  END rx[28]
  PIN rx[29]
    DIRECTION OUTPUT ;
    USE SIGNAL ;
    SHAPE ABUTMENT ;
    PORT
      LAYER M4 ;
      RECT 249.828 1188.768 250.020 1188.792 ;
    END
  END rx[29]
  PIN rx[30]
    DIRECTION OUTPUT ;
    USE SIGNAL ;
    SHAPE ABUTMENT ;
    PORT
      LAYER M4 ;
      RECT 249.828 1190.976 250.020 1191.000 ;
    END
  END rx[30]
  PIN rx[31]
    DIRECTION OUTPUT ;
    USE SIGNAL ;
    SHAPE ABUTMENT ;
    PORT
      LAYER M4 ;
      RECT 249.828 1193.184 250.020 1193.208 ;
    END
  END rx[31]
  PIN rx[32]
    DIRECTION OUTPUT ;
    USE SIGNAL ;
    SHAPE ABUTMENT ;
    PORT
      LAYER M4 ;
      RECT 249.828 1195.344 250.020 1195.368 ;
    END
  END rx[32]
  PIN rx[33]
    DIRECTION OUTPUT ;
    USE SIGNAL ;
    SHAPE ABUTMENT ;
    PORT
      LAYER M4 ;
      RECT 249.828 1197.552 250.020 1197.576 ;
    END
  END rx[33]
  PIN rx[34]
    DIRECTION OUTPUT ;
    USE SIGNAL ;
    SHAPE ABUTMENT ;
    PORT
      LAYER M4 ;
      RECT 249.828 1199.760 250.020 1199.784 ;
    END
  END rx[34]
  PIN rx[35]
    DIRECTION OUTPUT ;
    USE SIGNAL ;
    SHAPE ABUTMENT ;
    PORT
      LAYER M4 ;
      RECT 249.828 1201.968 250.020 1201.992 ;
    END
  END rx[35]
  PIN rx[36]
    DIRECTION OUTPUT ;
    USE SIGNAL ;
    SHAPE ABUTMENT ;
    PORT
      LAYER M4 ;
      RECT 249.828 1204.128 250.020 1204.152 ;
    END
  END rx[36]
  PIN rx[37]
    DIRECTION OUTPUT ;
    USE SIGNAL ;
    SHAPE ABUTMENT ;
    PORT
      LAYER M4 ;
      RECT 249.828 1206.336 250.020 1206.360 ;
    END
  END rx[37]
  PIN rx[38]
    DIRECTION OUTPUT ;
    USE SIGNAL ;
    SHAPE ABUTMENT ;
    PORT
      LAYER M4 ;
      RECT 249.828 1208.544 250.020 1208.568 ;
    END
  END rx[38]
  PIN rx[39]
    DIRECTION OUTPUT ;
    USE SIGNAL ;
    SHAPE ABUTMENT ;
    PORT
      LAYER M4 ;
      RECT 249.828 1210.752 250.020 1210.776 ;
    END
  END rx[39]
  PIN rx[40]
    DIRECTION OUTPUT ;
    USE SIGNAL ;
    SHAPE ABUTMENT ;
    PORT
      LAYER M4 ;
      RECT 249.828 1212.912 250.020 1212.936 ;
    END
  END rx[40]
  PIN rx[41]
    DIRECTION OUTPUT ;
    USE SIGNAL ;
    SHAPE ABUTMENT ;
    PORT
      LAYER M4 ;
      RECT 249.828 1215.120 250.020 1215.144 ;
    END
  END rx[41]
  PIN rx[42]
    DIRECTION OUTPUT ;
    USE SIGNAL ;
    SHAPE ABUTMENT ;
    PORT
      LAYER M4 ;
      RECT 249.828 1217.328 250.020 1217.352 ;
    END
  END rx[42]
  PIN rx[43]
    DIRECTION OUTPUT ;
    USE SIGNAL ;
    SHAPE ABUTMENT ;
    PORT
      LAYER M4 ;
      RECT 249.828 1219.536 250.020 1219.560 ;
    END
  END rx[43]
  PIN rx[44]
    DIRECTION OUTPUT ;
    USE SIGNAL ;
    SHAPE ABUTMENT ;
    PORT
      LAYER M4 ;
      RECT 249.828 1221.696 250.020 1221.720 ;
    END
  END rx[44]
  PIN rx[45]
    DIRECTION OUTPUT ;
    USE SIGNAL ;
    SHAPE ABUTMENT ;
    PORT
      LAYER M4 ;
      RECT 249.828 1223.904 250.020 1223.928 ;
    END
  END rx[45]
  PIN rx[46]
    DIRECTION OUTPUT ;
    USE SIGNAL ;
    SHAPE ABUTMENT ;
    PORT
      LAYER M4 ;
      RECT 249.828 1226.112 250.020 1226.136 ;
    END
  END rx[46]
  PIN rx[47]
    DIRECTION OUTPUT ;
    USE SIGNAL ;
    SHAPE ABUTMENT ;
    PORT
      LAYER M4 ;
      RECT 249.828 1228.320 250.020 1228.344 ;
    END
  END rx[47]
  PIN rx[48]
    DIRECTION OUTPUT ;
    USE SIGNAL ;
    SHAPE ABUTMENT ;
    PORT
      LAYER M4 ;
      RECT 249.828 1230.480 250.020 1230.504 ;
    END
  END rx[48]
  PIN rx[49]
    DIRECTION OUTPUT ;
    USE SIGNAL ;
    SHAPE ABUTMENT ;
    PORT
      LAYER M4 ;
      RECT 249.828 1232.688 250.020 1232.712 ;
    END
  END rx[49]
  PIN rx[50]
    DIRECTION OUTPUT ;
    USE SIGNAL ;
    SHAPE ABUTMENT ;
    PORT
      LAYER M4 ;
      RECT 249.828 1234.896 250.020 1234.920 ;
    END
  END rx[50]
  PIN rx[51]
    DIRECTION OUTPUT ;
    USE SIGNAL ;
    SHAPE ABUTMENT ;
    PORT
      LAYER M4 ;
      RECT 249.828 1237.104 250.020 1237.128 ;
    END
  END rx[51]
  PIN rx[52]
    DIRECTION OUTPUT ;
    USE SIGNAL ;
    SHAPE ABUTMENT ;
    PORT
      LAYER M4 ;
      RECT 249.828 1239.264 250.020 1239.288 ;
    END
  END rx[52]
  PIN rx[53]
    DIRECTION OUTPUT ;
    USE SIGNAL ;
    SHAPE ABUTMENT ;
    PORT
      LAYER M4 ;
      RECT 249.828 1241.472 250.020 1241.496 ;
    END
  END rx[53]
  PIN rx[54]
    DIRECTION OUTPUT ;
    USE SIGNAL ;
    SHAPE ABUTMENT ;
    PORT
      LAYER M4 ;
      RECT 249.828 1243.680 250.020 1243.704 ;
    END
  END rx[54]
  PIN rx[55]
    DIRECTION OUTPUT ;
    USE SIGNAL ;
    SHAPE ABUTMENT ;
    PORT
      LAYER M4 ;
      RECT 249.828 1245.888 250.020 1245.912 ;
    END
  END rx[55]
  PIN rx[56]
    DIRECTION OUTPUT ;
    USE SIGNAL ;
    SHAPE ABUTMENT ;
    PORT
      LAYER M4 ;
      RECT 249.828 1248.048 250.020 1248.072 ;
    END
  END rx[56]
  PIN rx[57]
    DIRECTION OUTPUT ;
    USE SIGNAL ;
    SHAPE ABUTMENT ;
    PORT
      LAYER M4 ;
      RECT 249.828 1250.256 250.020 1250.280 ;
    END
  END rx[57]
  PIN rx[58]
    DIRECTION OUTPUT ;
    USE SIGNAL ;
    SHAPE ABUTMENT ;
    PORT
      LAYER M4 ;
      RECT 249.828 1252.464 250.020 1252.488 ;
    END
  END rx[58]
  PIN rx[59]
    DIRECTION OUTPUT ;
    USE SIGNAL ;
    SHAPE ABUTMENT ;
    PORT
      LAYER M4 ;
      RECT 249.828 1254.672 250.020 1254.696 ;
    END
  END rx[59]
  PIN rx[60]
    DIRECTION OUTPUT ;
    USE SIGNAL ;
    SHAPE ABUTMENT ;
    PORT
      LAYER M4 ;
      RECT 249.828 1256.880 250.020 1256.904 ;
    END
  END rx[60]
  PIN rx[61]
    DIRECTION OUTPUT ;
    USE SIGNAL ;
    SHAPE ABUTMENT ;
    PORT
      LAYER M4 ;
      RECT 249.828 1259.040 250.020 1259.064 ;
    END
  END rx[61]
  PIN rx[62]
    DIRECTION OUTPUT ;
    USE SIGNAL ;
    SHAPE ABUTMENT ;
    PORT
      LAYER M4 ;
      RECT 249.828 1261.248 250.020 1261.272 ;
    END
  END rx[62]
  PIN rx[63]
    DIRECTION OUTPUT ;
    USE SIGNAL ;
    SHAPE ABUTMENT ;
    PORT
      LAYER M4 ;
      RECT 249.828 1263.456 250.020 1263.480 ;
    END
  END rx[63]
  PIN rx[64]
    DIRECTION OUTPUT ;
    USE SIGNAL ;
    SHAPE ABUTMENT ;
    PORT
      LAYER M4 ;
      RECT 249.828 1265.664 250.020 1265.688 ;
    END
  END rx[64]
  PIN rx[65]
    DIRECTION OUTPUT ;
    USE SIGNAL ;
    SHAPE ABUTMENT ;
    PORT
      LAYER M4 ;
      RECT 249.828 1267.824 250.020 1267.848 ;
    END
  END rx[65]
  PIN rx[66]
    DIRECTION OUTPUT ;
    USE SIGNAL ;
    SHAPE ABUTMENT ;
    PORT
      LAYER M4 ;
      RECT 249.828 1270.032 250.020 1270.056 ;
    END
  END rx[66]
  PIN rx[67]
    DIRECTION OUTPUT ;
    USE SIGNAL ;
    SHAPE ABUTMENT ;
    PORT
      LAYER M4 ;
      RECT 249.828 1272.240 250.020 1272.264 ;
    END
  END rx[67]
  PIN rx[68]
    DIRECTION OUTPUT ;
    USE SIGNAL ;
    SHAPE ABUTMENT ;
    PORT
      LAYER M4 ;
      RECT 249.828 1274.448 250.020 1274.472 ;
    END
  END rx[68]
  PIN rx[69]
    DIRECTION OUTPUT ;
    USE SIGNAL ;
    SHAPE ABUTMENT ;
    PORT
      LAYER M4 ;
      RECT 249.828 1276.608 250.020 1276.632 ;
    END
  END rx[69]
  PIN rx[70]
    DIRECTION OUTPUT ;
    USE SIGNAL ;
    SHAPE ABUTMENT ;
    PORT
      LAYER M4 ;
      RECT 249.828 1278.816 250.020 1278.840 ;
    END
  END rx[70]
  PIN rx[71]
    DIRECTION OUTPUT ;
    USE SIGNAL ;
    SHAPE ABUTMENT ;
    PORT
      LAYER M4 ;
      RECT 249.828 1281.024 250.020 1281.048 ;
    END
  END rx[71]
  PIN rx[72]
    DIRECTION OUTPUT ;
    USE SIGNAL ;
    SHAPE ABUTMENT ;
    PORT
      LAYER M4 ;
      RECT 249.828 1283.232 250.020 1283.256 ;
    END
  END rx[72]
  PIN rx[73]
    DIRECTION OUTPUT ;
    USE SIGNAL ;
    SHAPE ABUTMENT ;
    PORT
      LAYER M4 ;
      RECT 249.828 1285.392 250.020 1285.416 ;
    END
  END rx[73]
  PIN rx[74]
    DIRECTION OUTPUT ;
    USE SIGNAL ;
    SHAPE ABUTMENT ;
    PORT
      LAYER M4 ;
      RECT 249.828 1287.600 250.020 1287.624 ;
    END
  END rx[74]
  PIN rx[75]
    DIRECTION OUTPUT ;
    USE SIGNAL ;
    SHAPE ABUTMENT ;
    PORT
      LAYER M4 ;
      RECT 249.828 1289.808 250.020 1289.832 ;
    END
  END rx[75]
  PIN rx[76]
    DIRECTION OUTPUT ;
    USE SIGNAL ;
    SHAPE ABUTMENT ;
    PORT
      LAYER M4 ;
      RECT 249.828 1292.016 250.020 1292.040 ;
    END
  END rx[76]
  PIN rx[77]
    DIRECTION OUTPUT ;
    USE SIGNAL ;
    SHAPE ABUTMENT ;
    PORT
      LAYER M4 ;
      RECT 249.828 1294.176 250.020 1294.200 ;
    END
  END rx[77]
  PIN rx[78]
    DIRECTION OUTPUT ;
    USE SIGNAL ;
    SHAPE ABUTMENT ;
    PORT
      LAYER M4 ;
      RECT 249.828 1296.384 250.020 1296.408 ;
    END
  END rx[78]
  PIN rx[79]
    DIRECTION OUTPUT ;
    USE SIGNAL ;
    SHAPE ABUTMENT ;
    PORT
      LAYER M4 ;
      RECT 249.828 1298.592 250.020 1298.616 ;
    END
  END rx[79]
  PIN rx[80]
    DIRECTION OUTPUT ;
    USE SIGNAL ;
    SHAPE ABUTMENT ;
    PORT
      LAYER M4 ;
      RECT 249.828 1300.800 250.020 1300.824 ;
    END
  END rx[80]
  PIN rx[81]
    DIRECTION OUTPUT ;
    USE SIGNAL ;
    SHAPE ABUTMENT ;
    PORT
      LAYER M4 ;
      RECT 249.828 1302.960 250.020 1302.984 ;
    END
  END rx[81]
  PIN rx[82]
    DIRECTION OUTPUT ;
    USE SIGNAL ;
    SHAPE ABUTMENT ;
    PORT
      LAYER M4 ;
      RECT 249.828 1305.168 250.020 1305.192 ;
    END
  END rx[82]
  PIN rx[83]
    DIRECTION OUTPUT ;
    USE SIGNAL ;
    SHAPE ABUTMENT ;
    PORT
      LAYER M4 ;
      RECT 249.828 1307.376 250.020 1307.400 ;
    END
  END rx[83]
  PIN rx[84]
    DIRECTION OUTPUT ;
    USE SIGNAL ;
    SHAPE ABUTMENT ;
    PORT
      LAYER M4 ;
      RECT 249.828 1309.584 250.020 1309.608 ;
    END
  END rx[84]
  PIN rx[85]
    DIRECTION OUTPUT ;
    USE SIGNAL ;
    SHAPE ABUTMENT ;
    PORT
      LAYER M4 ;
      RECT 249.828 1311.744 250.020 1311.768 ;
    END
  END rx[85]
  PIN rx[86]
    DIRECTION OUTPUT ;
    USE SIGNAL ;
    SHAPE ABUTMENT ;
    PORT
      LAYER M4 ;
      RECT 249.828 1313.952 250.020 1313.976 ;
    END
  END rx[86]
  PIN rx[87]
    DIRECTION OUTPUT ;
    USE SIGNAL ;
    SHAPE ABUTMENT ;
    PORT
      LAYER M4 ;
      RECT 249.828 1316.160 250.020 1316.184 ;
    END
  END rx[87]
  PIN rx[88]
    DIRECTION OUTPUT ;
    USE SIGNAL ;
    SHAPE ABUTMENT ;
    PORT
      LAYER M4 ;
      RECT 249.828 1318.368 250.020 1318.392 ;
    END
  END rx[88]
  PIN rx[89]
    DIRECTION OUTPUT ;
    USE SIGNAL ;
    SHAPE ABUTMENT ;
    PORT
      LAYER M4 ;
      RECT 249.828 1320.576 250.020 1320.600 ;
    END
  END rx[89]
  PIN rx[90]
    DIRECTION OUTPUT ;
    USE SIGNAL ;
    SHAPE ABUTMENT ;
    PORT
      LAYER M4 ;
      RECT 249.828 1322.736 250.020 1322.760 ;
    END
  END rx[90]
  PIN rx[91]
    DIRECTION OUTPUT ;
    USE SIGNAL ;
    SHAPE ABUTMENT ;
    PORT
      LAYER M4 ;
      RECT 249.828 1324.944 250.020 1324.968 ;
    END
  END rx[91]
  PIN rx[92]
    DIRECTION OUTPUT ;
    USE SIGNAL ;
    SHAPE ABUTMENT ;
    PORT
      LAYER M4 ;
      RECT 249.828 1327.152 250.020 1327.176 ;
    END
  END rx[92]
  PIN rx[93]
    DIRECTION OUTPUT ;
    USE SIGNAL ;
    SHAPE ABUTMENT ;
    PORT
      LAYER M4 ;
      RECT 249.828 1329.360 250.020 1329.384 ;
    END
  END rx[93]
  PIN rx[94]
    DIRECTION OUTPUT ;
    USE SIGNAL ;
    SHAPE ABUTMENT ;
    PORT
      LAYER M4 ;
      RECT 249.828 1331.520 250.020 1331.544 ;
    END
  END rx[94]
  PIN rx[95]
    DIRECTION OUTPUT ;
    USE SIGNAL ;
    SHAPE ABUTMENT ;
    PORT
      LAYER M4 ;
      RECT 249.828 1333.728 250.020 1333.752 ;
    END
  END rx[95]
  PIN rx[96]
    DIRECTION OUTPUT ;
    USE SIGNAL ;
    SHAPE ABUTMENT ;
    PORT
      LAYER M4 ;
      RECT 249.828 1335.936 250.020 1335.960 ;
    END
  END rx[96]
  PIN rx[97]
    DIRECTION OUTPUT ;
    USE SIGNAL ;
    SHAPE ABUTMENT ;
    PORT
      LAYER M4 ;
      RECT 249.828 1338.144 250.020 1338.168 ;
    END
  END rx[97]
  PIN rx[98]
    DIRECTION OUTPUT ;
    USE SIGNAL ;
    SHAPE ABUTMENT ;
    PORT
      LAYER M4 ;
      RECT 249.828 1340.304 250.020 1340.328 ;
    END
  END rx[98]
  PIN rx[99]
    DIRECTION OUTPUT ;
    USE SIGNAL ;
    SHAPE ABUTMENT ;
    PORT
      LAYER M4 ;
      RECT 249.828 1342.512 250.020 1342.536 ;
    END
  END rx[99]
  PIN rx[100]
    DIRECTION OUTPUT ;
    USE SIGNAL ;
    SHAPE ABUTMENT ;
    PORT
      LAYER M4 ;
      RECT 249.828 1344.720 250.020 1344.744 ;
    END
  END rx[100]
  PIN rx[101]
    DIRECTION OUTPUT ;
    USE SIGNAL ;
    SHAPE ABUTMENT ;
    PORT
      LAYER M4 ;
      RECT 249.828 1346.928 250.020 1346.952 ;
    END
  END rx[101]
  PIN rx[102]
    DIRECTION OUTPUT ;
    USE SIGNAL ;
    SHAPE ABUTMENT ;
    PORT
      LAYER M4 ;
      RECT 249.828 1349.088 250.020 1349.112 ;
    END
  END rx[102]
  PIN rx[103]
    DIRECTION OUTPUT ;
    USE SIGNAL ;
    SHAPE ABUTMENT ;
    PORT
      LAYER M4 ;
      RECT 249.828 1351.296 250.020 1351.320 ;
    END
  END rx[103]
  PIN rx[104]
    DIRECTION OUTPUT ;
    USE SIGNAL ;
    SHAPE ABUTMENT ;
    PORT
      LAYER M4 ;
      RECT 249.828 1353.504 250.020 1353.528 ;
    END
  END rx[104]
  PIN rx[105]
    DIRECTION OUTPUT ;
    USE SIGNAL ;
    SHAPE ABUTMENT ;
    PORT
      LAYER M4 ;
      RECT 249.828 1355.712 250.020 1355.736 ;
    END
  END rx[105]
  PIN rx[106]
    DIRECTION OUTPUT ;
    USE SIGNAL ;
    SHAPE ABUTMENT ;
    PORT
      LAYER M4 ;
      RECT 249.828 1357.872 250.020 1357.896 ;
    END
  END rx[106]
  PIN rx[107]
    DIRECTION OUTPUT ;
    USE SIGNAL ;
    SHAPE ABUTMENT ;
    PORT
      LAYER M4 ;
      RECT 249.828 1360.080 250.020 1360.104 ;
    END
  END rx[107]
  PIN rx[108]
    DIRECTION OUTPUT ;
    USE SIGNAL ;
    SHAPE ABUTMENT ;
    PORT
      LAYER M4 ;
      RECT 249.828 1362.288 250.020 1362.312 ;
    END
  END rx[108]
  PIN rx[109]
    DIRECTION OUTPUT ;
    USE SIGNAL ;
    SHAPE ABUTMENT ;
    PORT
      LAYER M4 ;
      RECT 249.828 1364.496 250.020 1364.520 ;
    END
  END rx[109]
  PIN rx[110]
    DIRECTION OUTPUT ;
    USE SIGNAL ;
    SHAPE ABUTMENT ;
    PORT
      LAYER M4 ;
      RECT 249.828 1366.656 250.020 1366.680 ;
    END
  END rx[110]
  PIN rx[111]
    DIRECTION OUTPUT ;
    USE SIGNAL ;
    SHAPE ABUTMENT ;
    PORT
      LAYER M4 ;
      RECT 249.828 1368.864 250.020 1368.888 ;
    END
  END rx[111]
  PIN rx[112]
    DIRECTION OUTPUT ;
    USE SIGNAL ;
    SHAPE ABUTMENT ;
    PORT
      LAYER M4 ;
      RECT 249.828 1371.072 250.020 1371.096 ;
    END
  END rx[112]
  PIN rx[113]
    DIRECTION OUTPUT ;
    USE SIGNAL ;
    SHAPE ABUTMENT ;
    PORT
      LAYER M4 ;
      RECT 249.828 1373.280 250.020 1373.304 ;
    END
  END rx[113]
  PIN rx[114]
    DIRECTION OUTPUT ;
    USE SIGNAL ;
    SHAPE ABUTMENT ;
    PORT
      LAYER M4 ;
      RECT 249.828 1375.488 250.020 1375.512 ;
    END
  END rx[114]
  PIN rx[115]
    DIRECTION OUTPUT ;
    USE SIGNAL ;
    SHAPE ABUTMENT ;
    PORT
      LAYER M4 ;
      RECT 249.828 1377.648 250.020 1377.672 ;
    END
  END rx[115]
  PIN rx[116]
    DIRECTION OUTPUT ;
    USE SIGNAL ;
    SHAPE ABUTMENT ;
    PORT
      LAYER M4 ;
      RECT 249.828 1379.856 250.020 1379.880 ;
    END
  END rx[116]
  PIN rx[117]
    DIRECTION OUTPUT ;
    USE SIGNAL ;
    SHAPE ABUTMENT ;
    PORT
      LAYER M4 ;
      RECT 249.828 1382.064 250.020 1382.088 ;
    END
  END rx[117]
  PIN rx[118]
    DIRECTION OUTPUT ;
    USE SIGNAL ;
    SHAPE ABUTMENT ;
    PORT
      LAYER M4 ;
      RECT 249.828 1384.272 250.020 1384.296 ;
    END
  END rx[118]
  PIN rx[119]
    DIRECTION OUTPUT ;
    USE SIGNAL ;
    SHAPE ABUTMENT ;
    PORT
      LAYER M4 ;
      RECT 249.828 1386.432 250.020 1386.456 ;
    END
  END rx[119]
  PIN rx[120]
    DIRECTION OUTPUT ;
    USE SIGNAL ;
    SHAPE ABUTMENT ;
    PORT
      LAYER M4 ;
      RECT 249.828 1388.640 250.020 1388.664 ;
    END
  END rx[120]
  PIN rx[121]
    DIRECTION OUTPUT ;
    USE SIGNAL ;
    SHAPE ABUTMENT ;
    PORT
      LAYER M4 ;
      RECT 249.828 1390.848 250.020 1390.872 ;
    END
  END rx[121]
  PIN rx[122]
    DIRECTION OUTPUT ;
    USE SIGNAL ;
    SHAPE ABUTMENT ;
    PORT
      LAYER M4 ;
      RECT 249.828 1393.056 250.020 1393.080 ;
    END
  END rx[122]
  PIN rx[123]
    DIRECTION OUTPUT ;
    USE SIGNAL ;
    SHAPE ABUTMENT ;
    PORT
      LAYER M4 ;
      RECT 249.828 1395.216 250.020 1395.240 ;
    END
  END rx[123]
  PIN rx[124]
    DIRECTION OUTPUT ;
    USE SIGNAL ;
    SHAPE ABUTMENT ;
    PORT
      LAYER M4 ;
      RECT 249.828 1397.424 250.020 1397.448 ;
    END
  END rx[124]
  PIN rx[125]
    DIRECTION OUTPUT ;
    USE SIGNAL ;
    SHAPE ABUTMENT ;
    PORT
      LAYER M4 ;
      RECT 249.828 1399.632 250.020 1399.656 ;
    END
  END rx[125]
  PIN rx[126]
    DIRECTION OUTPUT ;
    USE SIGNAL ;
    SHAPE ABUTMENT ;
    PORT
      LAYER M4 ;
      RECT 249.828 1401.840 250.020 1401.864 ;
    END
  END rx[126]
  PIN rx[127]
    DIRECTION OUTPUT ;
    USE SIGNAL ;
    SHAPE ABUTMENT ;
    PORT
      LAYER M4 ;
      RECT 249.828 1404.000 250.020 1404.024 ;
    END
  END rx[127]
  PIN rx[128]
    DIRECTION OUTPUT ;
    USE SIGNAL ;
    SHAPE ABUTMENT ;
    PORT
      LAYER M4 ;
      RECT 249.828 1406.208 250.020 1406.232 ;
    END
  END rx[128]
  PIN rx[129]
    DIRECTION OUTPUT ;
    USE SIGNAL ;
    SHAPE ABUTMENT ;
    PORT
      LAYER M4 ;
      RECT 249.828 1408.416 250.020 1408.440 ;
    END
  END rx[129]
  PIN rx[130]
    DIRECTION OUTPUT ;
    USE SIGNAL ;
    SHAPE ABUTMENT ;
    PORT
      LAYER M4 ;
      RECT 249.828 1410.624 250.020 1410.648 ;
    END
  END rx[130]
  PIN rx[131]
    DIRECTION OUTPUT ;
    USE SIGNAL ;
    SHAPE ABUTMENT ;
    PORT
      LAYER M4 ;
      RECT 249.828 1412.784 250.020 1412.808 ;
    END
  END rx[131]
  PIN rx[132]
    DIRECTION OUTPUT ;
    USE SIGNAL ;
    SHAPE ABUTMENT ;
    PORT
      LAYER M4 ;
      RECT 249.828 1414.992 250.020 1415.016 ;
    END
  END rx[132]
  PIN rx[133]
    DIRECTION OUTPUT ;
    USE SIGNAL ;
    SHAPE ABUTMENT ;
    PORT
      LAYER M4 ;
      RECT 249.828 1417.200 250.020 1417.224 ;
    END
  END rx[133]
  PIN rx[134]
    DIRECTION OUTPUT ;
    USE SIGNAL ;
    SHAPE ABUTMENT ;
    PORT
      LAYER M4 ;
      RECT 249.828 1419.408 250.020 1419.432 ;
    END
  END rx[134]
  PIN rx[135]
    DIRECTION OUTPUT ;
    USE SIGNAL ;
    SHAPE ABUTMENT ;
    PORT
      LAYER M4 ;
      RECT 249.828 1421.568 250.020 1421.592 ;
    END
  END rx[135]
  PIN rx[136]
    DIRECTION OUTPUT ;
    USE SIGNAL ;
    SHAPE ABUTMENT ;
    PORT
      LAYER M4 ;
      RECT 249.828 1423.776 250.020 1423.800 ;
    END
  END rx[136]
  PIN rx[137]
    DIRECTION OUTPUT ;
    USE SIGNAL ;
    SHAPE ABUTMENT ;
    PORT
      LAYER M4 ;
      RECT 249.828 1425.984 250.020 1426.008 ;
    END
  END rx[137]
  PIN rx[138]
    DIRECTION OUTPUT ;
    USE SIGNAL ;
    SHAPE ABUTMENT ;
    PORT
      LAYER M4 ;
      RECT 249.828 1428.192 250.020 1428.216 ;
    END
  END rx[138]
  PIN rx[139]
    DIRECTION OUTPUT ;
    USE SIGNAL ;
    SHAPE ABUTMENT ;
    PORT
      LAYER M4 ;
      RECT 249.828 1430.352 250.020 1430.376 ;
    END
  END rx[139]
  PIN rx[140]
    DIRECTION OUTPUT ;
    USE SIGNAL ;
    SHAPE ABUTMENT ;
    PORT
      LAYER M4 ;
      RECT 249.828 1432.560 250.020 1432.584 ;
    END
  END rx[140]
  PIN rx[141]
    DIRECTION OUTPUT ;
    USE SIGNAL ;
    SHAPE ABUTMENT ;
    PORT
      LAYER M4 ;
      RECT 249.828 1434.768 250.020 1434.792 ;
    END
  END rx[141]
  PIN rx[142]
    DIRECTION OUTPUT ;
    USE SIGNAL ;
    SHAPE ABUTMENT ;
    PORT
      LAYER M4 ;
      RECT 249.828 1436.976 250.020 1437.000 ;
    END
  END rx[142]
  PIN rx[143]
    DIRECTION OUTPUT ;
    USE SIGNAL ;
    SHAPE ABUTMENT ;
    PORT
      LAYER M4 ;
      RECT 249.828 1439.184 250.020 1439.208 ;
    END
  END rx[143]
  PIN rx[144]
    DIRECTION OUTPUT ;
    USE SIGNAL ;
    SHAPE ABUTMENT ;
    PORT
      LAYER M4 ;
      RECT 249.828 1441.344 250.020 1441.368 ;
    END
  END rx[144]
  PIN rx[145]
    DIRECTION OUTPUT ;
    USE SIGNAL ;
    SHAPE ABUTMENT ;
    PORT
      LAYER M4 ;
      RECT 249.828 1443.552 250.020 1443.576 ;
    END
  END rx[145]
  PIN rx[146]
    DIRECTION OUTPUT ;
    USE SIGNAL ;
    SHAPE ABUTMENT ;
    PORT
      LAYER M4 ;
      RECT 249.828 1445.760 250.020 1445.784 ;
    END
  END rx[146]
  PIN rx[147]
    DIRECTION OUTPUT ;
    USE SIGNAL ;
    SHAPE ABUTMENT ;
    PORT
      LAYER M4 ;
      RECT 249.828 1447.968 250.020 1447.992 ;
    END
  END rx[147]
  PIN rx[148]
    DIRECTION OUTPUT ;
    USE SIGNAL ;
    SHAPE ABUTMENT ;
    PORT
      LAYER M4 ;
      RECT 249.828 1450.128 250.020 1450.152 ;
    END
  END rx[148]
  PIN rx[149]
    DIRECTION OUTPUT ;
    USE SIGNAL ;
    SHAPE ABUTMENT ;
    PORT
      LAYER M4 ;
      RECT 249.828 1452.336 250.020 1452.360 ;
    END
  END rx[149]
  PIN rx[150]
    DIRECTION OUTPUT ;
    USE SIGNAL ;
    SHAPE ABUTMENT ;
    PORT
      LAYER M4 ;
      RECT 249.828 1454.544 250.020 1454.568 ;
    END
  END rx[150]
  PIN rx[151]
    DIRECTION OUTPUT ;
    USE SIGNAL ;
    SHAPE ABUTMENT ;
    PORT
      LAYER M4 ;
      RECT 249.828 1456.752 250.020 1456.776 ;
    END
  END rx[151]
  PIN rx[152]
    DIRECTION OUTPUT ;
    USE SIGNAL ;
    SHAPE ABUTMENT ;
    PORT
      LAYER M4 ;
      RECT 249.828 1458.912 250.020 1458.936 ;
    END
  END rx[152]
  PIN rx[153]
    DIRECTION OUTPUT ;
    USE SIGNAL ;
    SHAPE ABUTMENT ;
    PORT
      LAYER M4 ;
      RECT 249.828 1461.120 250.020 1461.144 ;
    END
  END rx[153]
  PIN rx[154]
    DIRECTION OUTPUT ;
    USE SIGNAL ;
    SHAPE ABUTMENT ;
    PORT
      LAYER M4 ;
      RECT 249.828 1463.328 250.020 1463.352 ;
    END
  END rx[154]
  PIN rx[155]
    DIRECTION OUTPUT ;
    USE SIGNAL ;
    SHAPE ABUTMENT ;
    PORT
      LAYER M4 ;
      RECT 249.828 1465.536 250.020 1465.560 ;
    END
  END rx[155]
  PIN rx[156]
    DIRECTION OUTPUT ;
    USE SIGNAL ;
    SHAPE ABUTMENT ;
    PORT
      LAYER M4 ;
      RECT 249.828 1467.696 250.020 1467.720 ;
    END
  END rx[156]
  PIN rx[157]
    DIRECTION OUTPUT ;
    USE SIGNAL ;
    SHAPE ABUTMENT ;
    PORT
      LAYER M4 ;
      RECT 249.828 1469.904 250.020 1469.928 ;
    END
  END rx[157]
  PIN rx[158]
    DIRECTION OUTPUT ;
    USE SIGNAL ;
    SHAPE ABUTMENT ;
    PORT
      LAYER M4 ;
      RECT 249.828 1472.112 250.020 1472.136 ;
    END
  END rx[158]
  PIN rx[159]
    DIRECTION OUTPUT ;
    USE SIGNAL ;
    SHAPE ABUTMENT ;
    PORT
      LAYER M4 ;
      RECT 249.828 1474.320 250.020 1474.344 ;
    END
  END rx[159]
  PIN rx[160]
    DIRECTION OUTPUT ;
    USE SIGNAL ;
    SHAPE ABUTMENT ;
    PORT
      LAYER M4 ;
      RECT 249.828 1476.480 250.020 1476.504 ;
    END
  END rx[160]
  PIN rx[161]
    DIRECTION OUTPUT ;
    USE SIGNAL ;
    SHAPE ABUTMENT ;
    PORT
      LAYER M4 ;
      RECT 249.828 1478.688 250.020 1478.712 ;
    END
  END rx[161]
  PIN rx[162]
    DIRECTION OUTPUT ;
    USE SIGNAL ;
    SHAPE ABUTMENT ;
    PORT
      LAYER M4 ;
      RECT 249.828 1480.896 250.020 1480.920 ;
    END
  END rx[162]
  PIN rx[163]
    DIRECTION OUTPUT ;
    USE SIGNAL ;
    SHAPE ABUTMENT ;
    PORT
      LAYER M4 ;
      RECT 249.828 1483.104 250.020 1483.128 ;
    END
  END rx[163]
  PIN rx[164]
    DIRECTION OUTPUT ;
    USE SIGNAL ;
    SHAPE ABUTMENT ;
    PORT
      LAYER M4 ;
      RECT 249.828 1485.264 250.020 1485.288 ;
    END
  END rx[164]
  PIN rx[165]
    DIRECTION OUTPUT ;
    USE SIGNAL ;
    SHAPE ABUTMENT ;
    PORT
      LAYER M4 ;
      RECT 249.828 1487.472 250.020 1487.496 ;
    END
  END rx[165]
  PIN rx[166]
    DIRECTION OUTPUT ;
    USE SIGNAL ;
    SHAPE ABUTMENT ;
    PORT
      LAYER M4 ;
      RECT 249.828 1489.680 250.020 1489.704 ;
    END
  END rx[166]
  PIN rx[167]
    DIRECTION OUTPUT ;
    USE SIGNAL ;
    SHAPE ABUTMENT ;
    PORT
      LAYER M4 ;
      RECT 249.828 1491.888 250.020 1491.912 ;
    END
  END rx[167]
  PIN rx[168]
    DIRECTION OUTPUT ;
    USE SIGNAL ;
    SHAPE ABUTMENT ;
    PORT
      LAYER M4 ;
      RECT 249.828 1494.048 250.020 1494.072 ;
    END
  END rx[168]
  PIN rx[169]
    DIRECTION OUTPUT ;
    USE SIGNAL ;
    SHAPE ABUTMENT ;
    PORT
      LAYER M4 ;
      RECT 249.828 1496.256 250.020 1496.280 ;
    END
  END rx[169]
  PIN rx[170]
    DIRECTION OUTPUT ;
    USE SIGNAL ;
    SHAPE ABUTMENT ;
    PORT
      LAYER M4 ;
      RECT 249.828 1498.464 250.020 1498.488 ;
    END
  END rx[170]
  PIN rx[171]
    DIRECTION OUTPUT ;
    USE SIGNAL ;
    SHAPE ABUTMENT ;
    PORT
      LAYER M4 ;
      RECT 249.828 1500.672 250.020 1500.696 ;
    END
  END rx[171]
  PIN rx[172]
    DIRECTION OUTPUT ;
    USE SIGNAL ;
    SHAPE ABUTMENT ;
    PORT
      LAYER M4 ;
      RECT 249.828 1502.880 250.020 1502.904 ;
    END
  END rx[172]
  PIN rx[173]
    DIRECTION OUTPUT ;
    USE SIGNAL ;
    SHAPE ABUTMENT ;
    PORT
      LAYER M4 ;
      RECT 249.828 1505.040 250.020 1505.064 ;
    END
  END rx[173]
  PIN rx[174]
    DIRECTION OUTPUT ;
    USE SIGNAL ;
    SHAPE ABUTMENT ;
    PORT
      LAYER M4 ;
      RECT 249.828 1507.248 250.020 1507.272 ;
    END
  END rx[174]
  PIN rx[175]
    DIRECTION OUTPUT ;
    USE SIGNAL ;
    SHAPE ABUTMENT ;
    PORT
      LAYER M4 ;
      RECT 249.828 1509.456 250.020 1509.480 ;
    END
  END rx[175]
  PIN rx[176]
    DIRECTION OUTPUT ;
    USE SIGNAL ;
    SHAPE ABUTMENT ;
    PORT
      LAYER M4 ;
      RECT 249.828 1511.664 250.020 1511.688 ;
    END
  END rx[176]
  PIN rx[177]
    DIRECTION OUTPUT ;
    USE SIGNAL ;
    SHAPE ABUTMENT ;
    PORT
      LAYER M4 ;
      RECT 249.828 1513.824 250.020 1513.848 ;
    END
  END rx[177]
  PIN rx[178]
    DIRECTION OUTPUT ;
    USE SIGNAL ;
    SHAPE ABUTMENT ;
    PORT
      LAYER M4 ;
      RECT 249.828 1516.032 250.020 1516.056 ;
    END
  END rx[178]
  PIN rx[179]
    DIRECTION OUTPUT ;
    USE SIGNAL ;
    SHAPE ABUTMENT ;
    PORT
      LAYER M4 ;
      RECT 249.828 1518.240 250.020 1518.264 ;
    END
  END rx[179]
  PIN rx[180]
    DIRECTION OUTPUT ;
    USE SIGNAL ;
    SHAPE ABUTMENT ;
    PORT
      LAYER M4 ;
      RECT 249.828 1520.448 250.020 1520.472 ;
    END
  END rx[180]
  PIN rx[181]
    DIRECTION OUTPUT ;
    USE SIGNAL ;
    SHAPE ABUTMENT ;
    PORT
      LAYER M4 ;
      RECT 249.828 1522.608 250.020 1522.632 ;
    END
  END rx[181]
  PIN rx[182]
    DIRECTION OUTPUT ;
    USE SIGNAL ;
    SHAPE ABUTMENT ;
    PORT
      LAYER M4 ;
      RECT 249.828 1524.816 250.020 1524.840 ;
    END
  END rx[182]
  PIN rx[183]
    DIRECTION OUTPUT ;
    USE SIGNAL ;
    SHAPE ABUTMENT ;
    PORT
      LAYER M4 ;
      RECT 249.828 1527.024 250.020 1527.048 ;
    END
  END rx[183]
  PIN rx[184]
    DIRECTION OUTPUT ;
    USE SIGNAL ;
    SHAPE ABUTMENT ;
    PORT
      LAYER M4 ;
      RECT 249.828 1529.232 250.020 1529.256 ;
    END
  END rx[184]
  PIN rx[185]
    DIRECTION OUTPUT ;
    USE SIGNAL ;
    SHAPE ABUTMENT ;
    PORT
      LAYER M4 ;
      RECT 249.828 1531.392 250.020 1531.416 ;
    END
  END rx[185]
  PIN rx[186]
    DIRECTION OUTPUT ;
    USE SIGNAL ;
    SHAPE ABUTMENT ;
    PORT
      LAYER M4 ;
      RECT 249.828 1533.600 250.020 1533.624 ;
    END
  END rx[186]
  PIN rx[187]
    DIRECTION OUTPUT ;
    USE SIGNAL ;
    SHAPE ABUTMENT ;
    PORT
      LAYER M4 ;
      RECT 249.828 1535.808 250.020 1535.832 ;
    END
  END rx[187]
  PIN rx[188]
    DIRECTION OUTPUT ;
    USE SIGNAL ;
    SHAPE ABUTMENT ;
    PORT
      LAYER M4 ;
      RECT 249.828 1538.016 250.020 1538.040 ;
    END
  END rx[188]
  PIN rx[189]
    DIRECTION OUTPUT ;
    USE SIGNAL ;
    SHAPE ABUTMENT ;
    PORT
      LAYER M4 ;
      RECT 249.828 1540.176 250.020 1540.200 ;
    END
  END rx[189]
  PIN rx[190]
    DIRECTION OUTPUT ;
    USE SIGNAL ;
    SHAPE ABUTMENT ;
    PORT
      LAYER M4 ;
      RECT 249.828 1542.384 250.020 1542.408 ;
    END
  END rx[190]
  PIN rx[191]
    DIRECTION OUTPUT ;
    USE SIGNAL ;
    SHAPE ABUTMENT ;
    PORT
      LAYER M4 ;
      RECT 249.828 1544.592 250.020 1544.616 ;
    END
  END rx[191]
  PIN rx[192]
    DIRECTION OUTPUT ;
    USE SIGNAL ;
    SHAPE ABUTMENT ;
    PORT
      LAYER M4 ;
      RECT 249.828 1546.800 250.020 1546.824 ;
    END
  END rx[192]
  PIN rx[193]
    DIRECTION OUTPUT ;
    USE SIGNAL ;
    SHAPE ABUTMENT ;
    PORT
      LAYER M4 ;
      RECT 249.828 1548.960 250.020 1548.984 ;
    END
  END rx[193]
  PIN rx[194]
    DIRECTION OUTPUT ;
    USE SIGNAL ;
    SHAPE ABUTMENT ;
    PORT
      LAYER M4 ;
      RECT 249.828 1551.168 250.020 1551.192 ;
    END
  END rx[194]
  PIN rx[195]
    DIRECTION OUTPUT ;
    USE SIGNAL ;
    SHAPE ABUTMENT ;
    PORT
      LAYER M4 ;
      RECT 249.828 1553.376 250.020 1553.400 ;
    END
  END rx[195]
  PIN rx[196]
    DIRECTION OUTPUT ;
    USE SIGNAL ;
    SHAPE ABUTMENT ;
    PORT
      LAYER M4 ;
      RECT 249.828 1555.584 250.020 1555.608 ;
    END
  END rx[196]
  PIN rx[197]
    DIRECTION OUTPUT ;
    USE SIGNAL ;
    SHAPE ABUTMENT ;
    PORT
      LAYER M4 ;
      RECT 249.828 1557.744 250.020 1557.768 ;
    END
  END rx[197]
  PIN rx[198]
    DIRECTION OUTPUT ;
    USE SIGNAL ;
    SHAPE ABUTMENT ;
    PORT
      LAYER M4 ;
      RECT 249.828 1559.952 250.020 1559.976 ;
    END
  END rx[198]
  PIN rx[199]
    DIRECTION OUTPUT ;
    USE SIGNAL ;
    SHAPE ABUTMENT ;
    PORT
      LAYER M4 ;
      RECT 249.828 1562.160 250.020 1562.184 ;
    END
  END rx[199]
  PIN rx[200]
    DIRECTION OUTPUT ;
    USE SIGNAL ;
    SHAPE ABUTMENT ;
    PORT
      LAYER M4 ;
      RECT 249.828 1564.368 250.020 1564.392 ;
    END
  END rx[200]
  PIN rx[201]
    DIRECTION OUTPUT ;
    USE SIGNAL ;
    SHAPE ABUTMENT ;
    PORT
      LAYER M4 ;
      RECT 249.828 1566.576 250.020 1566.600 ;
    END
  END rx[201]
  PIN rx[202]
    DIRECTION OUTPUT ;
    USE SIGNAL ;
    SHAPE ABUTMENT ;
    PORT
      LAYER M4 ;
      RECT 249.828 1568.736 250.020 1568.760 ;
    END
  END rx[202]
  PIN rx[203]
    DIRECTION OUTPUT ;
    USE SIGNAL ;
    SHAPE ABUTMENT ;
    PORT
      LAYER M4 ;
      RECT 249.828 1570.944 250.020 1570.968 ;
    END
  END rx[203]
  PIN rx[204]
    DIRECTION OUTPUT ;
    USE SIGNAL ;
    SHAPE ABUTMENT ;
    PORT
      LAYER M4 ;
      RECT 249.828 1573.152 250.020 1573.176 ;
    END
  END rx[204]
  PIN rx[205]
    DIRECTION OUTPUT ;
    USE SIGNAL ;
    SHAPE ABUTMENT ;
    PORT
      LAYER M4 ;
      RECT 249.828 1575.360 250.020 1575.384 ;
    END
  END rx[205]
  PIN rx[206]
    DIRECTION OUTPUT ;
    USE SIGNAL ;
    SHAPE ABUTMENT ;
    PORT
      LAYER M4 ;
      RECT 249.828 1577.520 250.020 1577.544 ;
    END
  END rx[206]
  PIN rx[207]
    DIRECTION OUTPUT ;
    USE SIGNAL ;
    SHAPE ABUTMENT ;
    PORT
      LAYER M4 ;
      RECT 249.828 1579.728 250.020 1579.752 ;
    END
  END rx[207]
  PIN rx[208]
    DIRECTION OUTPUT ;
    USE SIGNAL ;
    SHAPE ABUTMENT ;
    PORT
      LAYER M4 ;
      RECT 249.828 1581.936 250.020 1581.960 ;
    END
  END rx[208]
  PIN rx[209]
    DIRECTION OUTPUT ;
    USE SIGNAL ;
    SHAPE ABUTMENT ;
    PORT
      LAYER M4 ;
      RECT 249.828 1584.144 250.020 1584.168 ;
    END
  END rx[209]
  PIN rx[210]
    DIRECTION OUTPUT ;
    USE SIGNAL ;
    SHAPE ABUTMENT ;
    PORT
      LAYER M4 ;
      RECT 249.828 1586.304 250.020 1586.328 ;
    END
  END rx[210]
  PIN rx[211]
    DIRECTION OUTPUT ;
    USE SIGNAL ;
    SHAPE ABUTMENT ;
    PORT
      LAYER M4 ;
      RECT 249.828 1588.512 250.020 1588.536 ;
    END
  END rx[211]
  PIN rx[212]
    DIRECTION OUTPUT ;
    USE SIGNAL ;
    SHAPE ABUTMENT ;
    PORT
      LAYER M4 ;
      RECT 249.828 1590.720 250.020 1590.744 ;
    END
  END rx[212]
  PIN rx[213]
    DIRECTION OUTPUT ;
    USE SIGNAL ;
    SHAPE ABUTMENT ;
    PORT
      LAYER M4 ;
      RECT 249.828 1592.928 250.020 1592.952 ;
    END
  END rx[213]
  PIN rx[214]
    DIRECTION OUTPUT ;
    USE SIGNAL ;
    SHAPE ABUTMENT ;
    PORT
      LAYER M4 ;
      RECT 249.828 1595.088 250.020 1595.112 ;
    END
  END rx[214]
  PIN rx[215]
    DIRECTION OUTPUT ;
    USE SIGNAL ;
    SHAPE ABUTMENT ;
    PORT
      LAYER M4 ;
      RECT 249.828 1597.296 250.020 1597.320 ;
    END
  END rx[215]
  PIN rx[216]
    DIRECTION OUTPUT ;
    USE SIGNAL ;
    SHAPE ABUTMENT ;
    PORT
      LAYER M4 ;
      RECT 249.828 1599.504 250.020 1599.528 ;
    END
  END rx[216]
  PIN rx[217]
    DIRECTION OUTPUT ;
    USE SIGNAL ;
    SHAPE ABUTMENT ;
    PORT
      LAYER M4 ;
      RECT 249.828 1601.712 250.020 1601.736 ;
    END
  END rx[217]
  PIN rx[218]
    DIRECTION OUTPUT ;
    USE SIGNAL ;
    SHAPE ABUTMENT ;
    PORT
      LAYER M4 ;
      RECT 249.828 1603.872 250.020 1603.896 ;
    END
  END rx[218]
  PIN rx[219]
    DIRECTION OUTPUT ;
    USE SIGNAL ;
    SHAPE ABUTMENT ;
    PORT
      LAYER M4 ;
      RECT 249.828 1606.080 250.020 1606.104 ;
    END
  END rx[219]
  PIN rx[220]
    DIRECTION OUTPUT ;
    USE SIGNAL ;
    SHAPE ABUTMENT ;
    PORT
      LAYER M4 ;
      RECT 249.828 1608.288 250.020 1608.312 ;
    END
  END rx[220]
  PIN rx[221]
    DIRECTION OUTPUT ;
    USE SIGNAL ;
    SHAPE ABUTMENT ;
    PORT
      LAYER M4 ;
      RECT 249.828 1610.496 250.020 1610.520 ;
    END
  END rx[221]
  PIN rx[222]
    DIRECTION OUTPUT ;
    USE SIGNAL ;
    SHAPE ABUTMENT ;
    PORT
      LAYER M4 ;
      RECT 249.828 1612.656 250.020 1612.680 ;
    END
  END rx[222]
  PIN rx[223]
    DIRECTION OUTPUT ;
    USE SIGNAL ;
    SHAPE ABUTMENT ;
    PORT
      LAYER M4 ;
      RECT 249.828 1614.864 250.020 1614.888 ;
    END
  END rx[223]
  PIN rx[224]
    DIRECTION OUTPUT ;
    USE SIGNAL ;
    SHAPE ABUTMENT ;
    PORT
      LAYER M4 ;
      RECT 249.828 1617.072 250.020 1617.096 ;
    END
  END rx[224]
  PIN rx[225]
    DIRECTION OUTPUT ;
    USE SIGNAL ;
    SHAPE ABUTMENT ;
    PORT
      LAYER M4 ;
      RECT 249.828 1619.280 250.020 1619.304 ;
    END
  END rx[225]
  PIN rx[226]
    DIRECTION OUTPUT ;
    USE SIGNAL ;
    SHAPE ABUTMENT ;
    PORT
      LAYER M4 ;
      RECT 249.828 1621.440 250.020 1621.464 ;
    END
  END rx[226]
  PIN rx[227]
    DIRECTION OUTPUT ;
    USE SIGNAL ;
    SHAPE ABUTMENT ;
    PORT
      LAYER M4 ;
      RECT 249.828 1623.648 250.020 1623.672 ;
    END
  END rx[227]
  PIN rx[228]
    DIRECTION OUTPUT ;
    USE SIGNAL ;
    SHAPE ABUTMENT ;
    PORT
      LAYER M4 ;
      RECT 249.828 1625.856 250.020 1625.880 ;
    END
  END rx[228]
  PIN rx[229]
    DIRECTION OUTPUT ;
    USE SIGNAL ;
    SHAPE ABUTMENT ;
    PORT
      LAYER M4 ;
      RECT 249.828 1628.064 250.020 1628.088 ;
    END
  END rx[229]
  PIN rx[230]
    DIRECTION OUTPUT ;
    USE SIGNAL ;
    SHAPE ABUTMENT ;
    PORT
      LAYER M4 ;
      RECT 249.828 1630.272 250.020 1630.296 ;
    END
  END rx[230]
  PIN rx[231]
    DIRECTION OUTPUT ;
    USE SIGNAL ;
    SHAPE ABUTMENT ;
    PORT
      LAYER M4 ;
      RECT 249.828 1632.432 250.020 1632.456 ;
    END
  END rx[231]
  PIN rx[232]
    DIRECTION OUTPUT ;
    USE SIGNAL ;
    SHAPE ABUTMENT ;
    PORT
      LAYER M4 ;
      RECT 249.828 1634.640 250.020 1634.664 ;
    END
  END rx[232]
  PIN rx[233]
    DIRECTION OUTPUT ;
    USE SIGNAL ;
    SHAPE ABUTMENT ;
    PORT
      LAYER M4 ;
      RECT 249.828 1636.848 250.020 1636.872 ;
    END
  END rx[233]
  PIN rx[234]
    DIRECTION OUTPUT ;
    USE SIGNAL ;
    SHAPE ABUTMENT ;
    PORT
      LAYER M4 ;
      RECT 249.828 1639.056 250.020 1639.080 ;
    END
  END rx[234]
  PIN rx[235]
    DIRECTION OUTPUT ;
    USE SIGNAL ;
    SHAPE ABUTMENT ;
    PORT
      LAYER M4 ;
      RECT 249.828 1641.216 250.020 1641.240 ;
    END
  END rx[235]
  PIN rx[236]
    DIRECTION OUTPUT ;
    USE SIGNAL ;
    SHAPE ABUTMENT ;
    PORT
      LAYER M4 ;
      RECT 249.828 1643.424 250.020 1643.448 ;
    END
  END rx[236]
  PIN rx[237]
    DIRECTION OUTPUT ;
    USE SIGNAL ;
    SHAPE ABUTMENT ;
    PORT
      LAYER M4 ;
      RECT 249.828 1645.632 250.020 1645.656 ;
    END
  END rx[237]
  PIN rx[238]
    DIRECTION OUTPUT ;
    USE SIGNAL ;
    SHAPE ABUTMENT ;
    PORT
      LAYER M4 ;
      RECT 249.828 1647.840 250.020 1647.864 ;
    END
  END rx[238]
  PIN rx[239]
    DIRECTION OUTPUT ;
    USE SIGNAL ;
    SHAPE ABUTMENT ;
    PORT
      LAYER M4 ;
      RECT 249.828 1650.000 250.020 1650.024 ;
    END
  END rx[239]
  PIN rx[240]
    DIRECTION OUTPUT ;
    USE SIGNAL ;
    SHAPE ABUTMENT ;
    PORT
      LAYER M4 ;
      RECT 249.828 1652.208 250.020 1652.232 ;
    END
  END rx[240]
  PIN rx[241]
    DIRECTION OUTPUT ;
    USE SIGNAL ;
    SHAPE ABUTMENT ;
    PORT
      LAYER M4 ;
      RECT 249.828 1654.416 250.020 1654.440 ;
    END
  END rx[241]
  PIN rx[242]
    DIRECTION OUTPUT ;
    USE SIGNAL ;
    SHAPE ABUTMENT ;
    PORT
      LAYER M4 ;
      RECT 249.828 1656.624 250.020 1656.648 ;
    END
  END rx[242]
  PIN rx[243]
    DIRECTION OUTPUT ;
    USE SIGNAL ;
    SHAPE ABUTMENT ;
    PORT
      LAYER M4 ;
      RECT 249.828 1658.784 250.020 1658.808 ;
    END
  END rx[243]
  PIN rx[244]
    DIRECTION OUTPUT ;
    USE SIGNAL ;
    SHAPE ABUTMENT ;
    PORT
      LAYER M4 ;
      RECT 249.828 1660.992 250.020 1661.016 ;
    END
  END rx[244]
  PIN rx[245]
    DIRECTION OUTPUT ;
    USE SIGNAL ;
    SHAPE ABUTMENT ;
    PORT
      LAYER M4 ;
      RECT 249.828 1663.200 250.020 1663.224 ;
    END
  END rx[245]
  PIN rx[246]
    DIRECTION OUTPUT ;
    USE SIGNAL ;
    SHAPE ABUTMENT ;
    PORT
      LAYER M4 ;
      RECT 249.828 1665.408 250.020 1665.432 ;
    END
  END rx[246]
  PIN rx[247]
    DIRECTION OUTPUT ;
    USE SIGNAL ;
    SHAPE ABUTMENT ;
    PORT
      LAYER M4 ;
      RECT 249.828 1667.568 250.020 1667.592 ;
    END
  END rx[247]
  PIN rx[248]
    DIRECTION OUTPUT ;
    USE SIGNAL ;
    SHAPE ABUTMENT ;
    PORT
      LAYER M4 ;
      RECT 249.828 1669.776 250.020 1669.800 ;
    END
  END rx[248]
  PIN rx[249]
    DIRECTION OUTPUT ;
    USE SIGNAL ;
    SHAPE ABUTMENT ;
    PORT
      LAYER M4 ;
      RECT 249.828 1671.984 250.020 1672.008 ;
    END
  END rx[249]
  PIN rx[250]
    DIRECTION OUTPUT ;
    USE SIGNAL ;
    SHAPE ABUTMENT ;
    PORT
      LAYER M4 ;
      RECT 249.828 1674.192 250.020 1674.216 ;
    END
  END rx[250]
  PIN rx[251]
    DIRECTION OUTPUT ;
    USE SIGNAL ;
    SHAPE ABUTMENT ;
    PORT
      LAYER M4 ;
      RECT 249.828 1676.352 250.020 1676.376 ;
    END
  END rx[251]
  PIN rx[252]
    DIRECTION OUTPUT ;
    USE SIGNAL ;
    SHAPE ABUTMENT ;
    PORT
      LAYER M4 ;
      RECT 249.828 1678.560 250.020 1678.584 ;
    END
  END rx[252]
  PIN rx[253]
    DIRECTION OUTPUT ;
    USE SIGNAL ;
    SHAPE ABUTMENT ;
    PORT
      LAYER M4 ;
      RECT 249.828 1680.768 250.020 1680.792 ;
    END
  END rx[253]
  PIN rx[254]
    DIRECTION OUTPUT ;
    USE SIGNAL ;
    SHAPE ABUTMENT ;
    PORT
      LAYER M4 ;
      RECT 249.828 1682.976 250.020 1683.000 ;
    END
  END rx[254]
  PIN rx[255]
    DIRECTION OUTPUT ;
    USE SIGNAL ;
    SHAPE ABUTMENT ;
    PORT
      LAYER M4 ;
      RECT 249.828 1685.136 250.020 1685.160 ;
    END
  END rx[255]
  PIN rx[256]
    DIRECTION OUTPUT ;
    USE SIGNAL ;
    SHAPE ABUTMENT ;
    PORT
      LAYER M4 ;
      RECT 249.828 1687.344 250.020 1687.368 ;
    END
  END rx[256]
  PIN rx[257]
    DIRECTION OUTPUT ;
    USE SIGNAL ;
    SHAPE ABUTMENT ;
    PORT
      LAYER M4 ;
      RECT 249.828 1689.552 250.020 1689.576 ;
    END
  END rx[257]
  PIN rx[258]
    DIRECTION OUTPUT ;
    USE SIGNAL ;
    SHAPE ABUTMENT ;
    PORT
      LAYER M4 ;
      RECT 249.828 1691.760 250.020 1691.784 ;
    END
  END rx[258]
  PIN rx[259]
    DIRECTION OUTPUT ;
    USE SIGNAL ;
    SHAPE ABUTMENT ;
    PORT
      LAYER M4 ;
      RECT 249.828 1693.968 250.020 1693.992 ;
    END
  END rx[259]
  PIN rx[260]
    DIRECTION OUTPUT ;
    USE SIGNAL ;
    SHAPE ABUTMENT ;
    PORT
      LAYER M4 ;
      RECT 249.828 1696.128 250.020 1696.152 ;
    END
  END rx[260]
  PIN rx[261]
    DIRECTION OUTPUT ;
    USE SIGNAL ;
    SHAPE ABUTMENT ;
    PORT
      LAYER M4 ;
      RECT 249.828 1698.336 250.020 1698.360 ;
    END
  END rx[261]
  PIN rx[262]
    DIRECTION OUTPUT ;
    USE SIGNAL ;
    SHAPE ABUTMENT ;
    PORT
      LAYER M4 ;
      RECT 249.828 1700.544 250.020 1700.568 ;
    END
  END rx[262]
  PIN rx[263]
    DIRECTION OUTPUT ;
    USE SIGNAL ;
    SHAPE ABUTMENT ;
    PORT
      LAYER M4 ;
      RECT 249.828 1702.752 250.020 1702.776 ;
    END
  END rx[263]
  PIN rx[264]
    DIRECTION OUTPUT ;
    USE SIGNAL ;
    SHAPE ABUTMENT ;
    PORT
      LAYER M4 ;
      RECT 249.828 1704.912 250.020 1704.936 ;
    END
  END rx[264]
  PIN rx[265]
    DIRECTION OUTPUT ;
    USE SIGNAL ;
    SHAPE ABUTMENT ;
    PORT
      LAYER M4 ;
      RECT 249.828 1707.120 250.020 1707.144 ;
    END
  END rx[265]
  PIN rx[266]
    DIRECTION OUTPUT ;
    USE SIGNAL ;
    SHAPE ABUTMENT ;
    PORT
      LAYER M4 ;
      RECT 249.828 1709.328 250.020 1709.352 ;
    END
  END rx[266]
  PIN rx[267]
    DIRECTION OUTPUT ;
    USE SIGNAL ;
    SHAPE ABUTMENT ;
    PORT
      LAYER M4 ;
      RECT 249.828 1711.536 250.020 1711.560 ;
    END
  END rx[267]
  PIN rx[268]
    DIRECTION OUTPUT ;
    USE SIGNAL ;
    SHAPE ABUTMENT ;
    PORT
      LAYER M4 ;
      RECT 249.828 1713.696 250.020 1713.720 ;
    END
  END rx[268]
  PIN rx[269]
    DIRECTION OUTPUT ;
    USE SIGNAL ;
    SHAPE ABUTMENT ;
    PORT
      LAYER M4 ;
      RECT 249.828 1715.904 250.020 1715.928 ;
    END
  END rx[269]
  PIN rx[270]
    DIRECTION OUTPUT ;
    USE SIGNAL ;
    SHAPE ABUTMENT ;
    PORT
      LAYER M4 ;
      RECT 249.828 1718.112 250.020 1718.136 ;
    END
  END rx[270]
  PIN rx[271]
    DIRECTION OUTPUT ;
    USE SIGNAL ;
    SHAPE ABUTMENT ;
    PORT
      LAYER M4 ;
      RECT 249.828 1720.320 250.020 1720.344 ;
    END
  END rx[271]
  PIN rx[272]
    DIRECTION OUTPUT ;
    USE SIGNAL ;
    SHAPE ABUTMENT ;
    PORT
      LAYER M4 ;
      RECT 249.828 1722.480 250.020 1722.504 ;
    END
  END rx[272]
  PIN rx[273]
    DIRECTION OUTPUT ;
    USE SIGNAL ;
    SHAPE ABUTMENT ;
    PORT
      LAYER M4 ;
      RECT 249.828 1724.688 250.020 1724.712 ;
    END
  END rx[273]
  PIN rx[274]
    DIRECTION OUTPUT ;
    USE SIGNAL ;
    SHAPE ABUTMENT ;
    PORT
      LAYER M4 ;
      RECT 249.828 1726.896 250.020 1726.920 ;
    END
  END rx[274]
  PIN rx[275]
    DIRECTION OUTPUT ;
    USE SIGNAL ;
    SHAPE ABUTMENT ;
    PORT
      LAYER M4 ;
      RECT 249.828 1729.104 250.020 1729.128 ;
    END
  END rx[275]
  PIN rx[276]
    DIRECTION OUTPUT ;
    USE SIGNAL ;
    SHAPE ABUTMENT ;
    PORT
      LAYER M4 ;
      RECT 249.828 1731.264 250.020 1731.288 ;
    END
  END rx[276]
  PIN rx[277]
    DIRECTION OUTPUT ;
    USE SIGNAL ;
    SHAPE ABUTMENT ;
    PORT
      LAYER M4 ;
      RECT 249.828 1733.472 250.020 1733.496 ;
    END
  END rx[277]
  PIN rx[278]
    DIRECTION OUTPUT ;
    USE SIGNAL ;
    SHAPE ABUTMENT ;
    PORT
      LAYER M4 ;
      RECT 249.828 1735.680 250.020 1735.704 ;
    END
  END rx[278]
  PIN rx[279]
    DIRECTION OUTPUT ;
    USE SIGNAL ;
    SHAPE ABUTMENT ;
    PORT
      LAYER M4 ;
      RECT 249.828 1737.888 250.020 1737.912 ;
    END
  END rx[279]
  PIN rx[280]
    DIRECTION OUTPUT ;
    USE SIGNAL ;
    SHAPE ABUTMENT ;
    PORT
      LAYER M4 ;
      RECT 249.828 1740.048 250.020 1740.072 ;
    END
  END rx[280]
  PIN rx[281]
    DIRECTION OUTPUT ;
    USE SIGNAL ;
    SHAPE ABUTMENT ;
    PORT
      LAYER M4 ;
      RECT 249.828 1742.256 250.020 1742.280 ;
    END
  END rx[281]
  PIN rx[282]
    DIRECTION OUTPUT ;
    USE SIGNAL ;
    SHAPE ABUTMENT ;
    PORT
      LAYER M4 ;
      RECT 249.828 1744.464 250.020 1744.488 ;
    END
  END rx[282]
  PIN rx[283]
    DIRECTION OUTPUT ;
    USE SIGNAL ;
    SHAPE ABUTMENT ;
    PORT
      LAYER M4 ;
      RECT 249.828 1746.672 250.020 1746.696 ;
    END
  END rx[283]
  PIN rx[284]
    DIRECTION OUTPUT ;
    USE SIGNAL ;
    SHAPE ABUTMENT ;
    PORT
      LAYER M4 ;
      RECT 249.828 1748.832 250.020 1748.856 ;
    END
  END rx[284]
  PIN rx[285]
    DIRECTION OUTPUT ;
    USE SIGNAL ;
    SHAPE ABUTMENT ;
    PORT
      LAYER M4 ;
      RECT 249.828 1751.040 250.020 1751.064 ;
    END
  END rx[285]
  PIN rx[286]
    DIRECTION OUTPUT ;
    USE SIGNAL ;
    SHAPE ABUTMENT ;
    PORT
      LAYER M4 ;
      RECT 249.828 1753.248 250.020 1753.272 ;
    END
  END rx[286]
  PIN rx[287]
    DIRECTION OUTPUT ;
    USE SIGNAL ;
    SHAPE ABUTMENT ;
    PORT
      LAYER M4 ;
      RECT 249.828 1755.456 250.020 1755.480 ;
    END
  END rx[287]
  PIN rx[288]
    DIRECTION OUTPUT ;
    USE SIGNAL ;
    SHAPE ABUTMENT ;
    PORT
      LAYER M4 ;
      RECT 249.828 1757.664 250.020 1757.688 ;
    END
  END rx[288]
  PIN rx[289]
    DIRECTION OUTPUT ;
    USE SIGNAL ;
    SHAPE ABUTMENT ;
    PORT
      LAYER M4 ;
      RECT 249.828 1759.824 250.020 1759.848 ;
    END
  END rx[289]
  PIN rx[290]
    DIRECTION OUTPUT ;
    USE SIGNAL ;
    SHAPE ABUTMENT ;
    PORT
      LAYER M4 ;
      RECT 249.828 1762.032 250.020 1762.056 ;
    END
  END rx[290]
  PIN rx[291]
    DIRECTION OUTPUT ;
    USE SIGNAL ;
    SHAPE ABUTMENT ;
    PORT
      LAYER M4 ;
      RECT 249.828 1764.240 250.020 1764.264 ;
    END
  END rx[291]
  PIN rx[292]
    DIRECTION OUTPUT ;
    USE SIGNAL ;
    SHAPE ABUTMENT ;
    PORT
      LAYER M4 ;
      RECT 249.828 1766.448 250.020 1766.472 ;
    END
  END rx[292]
  PIN rx[293]
    DIRECTION OUTPUT ;
    USE SIGNAL ;
    SHAPE ABUTMENT ;
    PORT
      LAYER M4 ;
      RECT 249.828 1768.608 250.020 1768.632 ;
    END
  END rx[293]
  PIN rx[294]
    DIRECTION OUTPUT ;
    USE SIGNAL ;
    SHAPE ABUTMENT ;
    PORT
      LAYER M4 ;
      RECT 249.828 1770.816 250.020 1770.840 ;
    END
  END rx[294]
  PIN rx[295]
    DIRECTION OUTPUT ;
    USE SIGNAL ;
    SHAPE ABUTMENT ;
    PORT
      LAYER M4 ;
      RECT 249.828 1773.024 250.020 1773.048 ;
    END
  END rx[295]
  PIN rx[296]
    DIRECTION OUTPUT ;
    USE SIGNAL ;
    SHAPE ABUTMENT ;
    PORT
      LAYER M4 ;
      RECT 249.828 1775.232 250.020 1775.256 ;
    END
  END rx[296]
  PIN rx[297]
    DIRECTION OUTPUT ;
    USE SIGNAL ;
    SHAPE ABUTMENT ;
    PORT
      LAYER M4 ;
      RECT 249.828 1777.392 250.020 1777.416 ;
    END
  END rx[297]
  PIN rx[298]
    DIRECTION OUTPUT ;
    USE SIGNAL ;
    SHAPE ABUTMENT ;
    PORT
      LAYER M4 ;
      RECT 249.828 1779.600 250.020 1779.624 ;
    END
  END rx[298]
  PIN rx[299]
    DIRECTION OUTPUT ;
    USE SIGNAL ;
    SHAPE ABUTMENT ;
    PORT
      LAYER M4 ;
      RECT 249.828 1781.808 250.020 1781.832 ;
    END
  END rx[299]
  PIN rx[300]
    DIRECTION OUTPUT ;
    USE SIGNAL ;
    SHAPE ABUTMENT ;
    PORT
      LAYER M4 ;
      RECT 249.828 1784.016 250.020 1784.040 ;
    END
  END rx[300]
  PIN rx[301]
    DIRECTION OUTPUT ;
    USE SIGNAL ;
    SHAPE ABUTMENT ;
    PORT
      LAYER M4 ;
      RECT 249.828 1786.176 250.020 1786.200 ;
    END
  END rx[301]
  PIN rx[302]
    DIRECTION OUTPUT ;
    USE SIGNAL ;
    SHAPE ABUTMENT ;
    PORT
      LAYER M4 ;
      RECT 249.828 1788.384 250.020 1788.408 ;
    END
  END rx[302]
  PIN rx[303]
    DIRECTION OUTPUT ;
    USE SIGNAL ;
    SHAPE ABUTMENT ;
    PORT
      LAYER M4 ;
      RECT 249.828 1790.592 250.020 1790.616 ;
    END
  END rx[303]
  PIN rx[304]
    DIRECTION OUTPUT ;
    USE SIGNAL ;
    SHAPE ABUTMENT ;
    PORT
      LAYER M4 ;
      RECT 249.828 1792.800 250.020 1792.824 ;
    END
  END rx[304]
  PIN rx[305]
    DIRECTION OUTPUT ;
    USE SIGNAL ;
    SHAPE ABUTMENT ;
    PORT
      LAYER M4 ;
      RECT 249.828 1794.960 250.020 1794.984 ;
    END
  END rx[305]
  PIN rx[306]
    DIRECTION OUTPUT ;
    USE SIGNAL ;
    SHAPE ABUTMENT ;
    PORT
      LAYER M4 ;
      RECT 249.828 1797.168 250.020 1797.192 ;
    END
  END rx[306]
  PIN rx[307]
    DIRECTION OUTPUT ;
    USE SIGNAL ;
    SHAPE ABUTMENT ;
    PORT
      LAYER M4 ;
      RECT 249.828 1799.376 250.020 1799.400 ;
    END
  END rx[307]
  PIN rx[308]
    DIRECTION OUTPUT ;
    USE SIGNAL ;
    SHAPE ABUTMENT ;
    PORT
      LAYER M4 ;
      RECT 249.828 1801.584 250.020 1801.608 ;
    END
  END rx[308]
  PIN rx[309]
    DIRECTION OUTPUT ;
    USE SIGNAL ;
    SHAPE ABUTMENT ;
    PORT
      LAYER M4 ;
      RECT 249.828 1803.744 250.020 1803.768 ;
    END
  END rx[309]
  PIN rx[310]
    DIRECTION OUTPUT ;
    USE SIGNAL ;
    SHAPE ABUTMENT ;
    PORT
      LAYER M4 ;
      RECT 249.828 1805.952 250.020 1805.976 ;
    END
  END rx[310]
  PIN rx[311]
    DIRECTION OUTPUT ;
    USE SIGNAL ;
    SHAPE ABUTMENT ;
    PORT
      LAYER M4 ;
      RECT 249.828 1808.160 250.020 1808.184 ;
    END
  END rx[311]
  PIN rx[312]
    DIRECTION OUTPUT ;
    USE SIGNAL ;
    SHAPE ABUTMENT ;
    PORT
      LAYER M4 ;
      RECT 249.828 1810.368 250.020 1810.392 ;
    END
  END rx[312]
  PIN rx[313]
    DIRECTION OUTPUT ;
    USE SIGNAL ;
    SHAPE ABUTMENT ;
    PORT
      LAYER M4 ;
      RECT 249.828 1812.576 250.020 1812.600 ;
    END
  END rx[313]
  PIN rx[314]
    DIRECTION OUTPUT ;
    USE SIGNAL ;
    SHAPE ABUTMENT ;
    PORT
      LAYER M4 ;
      RECT 249.828 1814.736 250.020 1814.760 ;
    END
  END rx[314]
  PIN rx[315]
    DIRECTION OUTPUT ;
    USE SIGNAL ;
    SHAPE ABUTMENT ;
    PORT
      LAYER M4 ;
      RECT 249.828 1816.944 250.020 1816.968 ;
    END
  END rx[315]
  PIN rx[316]
    DIRECTION OUTPUT ;
    USE SIGNAL ;
    SHAPE ABUTMENT ;
    PORT
      LAYER M4 ;
      RECT 249.828 1819.152 250.020 1819.176 ;
    END
  END rx[316]
  PIN rx[317]
    DIRECTION OUTPUT ;
    USE SIGNAL ;
    SHAPE ABUTMENT ;
    PORT
      LAYER M4 ;
      RECT 249.828 1821.360 250.020 1821.384 ;
    END
  END rx[317]
  PIN rx[318]
    DIRECTION OUTPUT ;
    USE SIGNAL ;
    SHAPE ABUTMENT ;
    PORT
      LAYER M4 ;
      RECT 249.828 1823.520 250.020 1823.544 ;
    END
  END rx[318]
  PIN rx[319]
    DIRECTION OUTPUT ;
    USE SIGNAL ;
    SHAPE ABUTMENT ;
    PORT
      LAYER M4 ;
      RECT 249.828 1825.728 250.020 1825.752 ;
    END
  END rx[319]
  PIN rx[320]
    DIRECTION OUTPUT ;
    USE SIGNAL ;
    SHAPE ABUTMENT ;
    PORT
      LAYER M4 ;
      RECT 249.828 1827.936 250.020 1827.960 ;
    END
  END rx[320]
  PIN rx[321]
    DIRECTION OUTPUT ;
    USE SIGNAL ;
    SHAPE ABUTMENT ;
    PORT
      LAYER M4 ;
      RECT 249.828 1830.144 250.020 1830.168 ;
    END
  END rx[321]
  PIN rx[322]
    DIRECTION OUTPUT ;
    USE SIGNAL ;
    SHAPE ABUTMENT ;
    PORT
      LAYER M4 ;
      RECT 249.828 1832.304 250.020 1832.328 ;
    END
  END rx[322]
  PIN rx[323]
    DIRECTION OUTPUT ;
    USE SIGNAL ;
    SHAPE ABUTMENT ;
    PORT
      LAYER M4 ;
      RECT 249.828 1834.512 250.020 1834.536 ;
    END
  END rx[323]
  PIN rx[324]
    DIRECTION OUTPUT ;
    USE SIGNAL ;
    SHAPE ABUTMENT ;
    PORT
      LAYER M4 ;
      RECT 249.828 1836.720 250.020 1836.744 ;
    END
  END rx[324]
  PIN rx[325]
    DIRECTION OUTPUT ;
    USE SIGNAL ;
    SHAPE ABUTMENT ;
    PORT
      LAYER M4 ;
      RECT 249.828 1838.928 250.020 1838.952 ;
    END
  END rx[325]
  PIN rx[326]
    DIRECTION OUTPUT ;
    USE SIGNAL ;
    SHAPE ABUTMENT ;
    PORT
      LAYER M4 ;
      RECT 249.828 1841.088 250.020 1841.112 ;
    END
  END rx[326]
  PIN rx[327]
    DIRECTION OUTPUT ;
    USE SIGNAL ;
    SHAPE ABUTMENT ;
    PORT
      LAYER M4 ;
      RECT 249.828 1843.296 250.020 1843.320 ;
    END
  END rx[327]
  PIN rx[328]
    DIRECTION OUTPUT ;
    USE SIGNAL ;
    SHAPE ABUTMENT ;
    PORT
      LAYER M4 ;
      RECT 249.828 1845.504 250.020 1845.528 ;
    END
  END rx[328]
  PIN rx[329]
    DIRECTION OUTPUT ;
    USE SIGNAL ;
    SHAPE ABUTMENT ;
    PORT
      LAYER M4 ;
      RECT 249.828 1847.712 250.020 1847.736 ;
    END
  END rx[329]
  PIN rx[330]
    DIRECTION OUTPUT ;
    USE SIGNAL ;
    SHAPE ABUTMENT ;
    PORT
      LAYER M4 ;
      RECT 249.828 1849.872 250.020 1849.896 ;
    END
  END rx[330]
  PIN rx[331]
    DIRECTION OUTPUT ;
    USE SIGNAL ;
    SHAPE ABUTMENT ;
    PORT
      LAYER M4 ;
      RECT 249.828 1852.080 250.020 1852.104 ;
    END
  END rx[331]
  PIN rx[332]
    DIRECTION OUTPUT ;
    USE SIGNAL ;
    SHAPE ABUTMENT ;
    PORT
      LAYER M4 ;
      RECT 249.828 1854.288 250.020 1854.312 ;
    END
  END rx[332]
  PIN rx[333]
    DIRECTION OUTPUT ;
    USE SIGNAL ;
    SHAPE ABUTMENT ;
    PORT
      LAYER M4 ;
      RECT 249.828 1856.496 250.020 1856.520 ;
    END
  END rx[333]
  PIN rx[334]
    DIRECTION OUTPUT ;
    USE SIGNAL ;
    SHAPE ABUTMENT ;
    PORT
      LAYER M4 ;
      RECT 249.828 1858.656 250.020 1858.680 ;
    END
  END rx[334]
  PIN rx[335]
    DIRECTION OUTPUT ;
    USE SIGNAL ;
    SHAPE ABUTMENT ;
    PORT
      LAYER M4 ;
      RECT 249.828 1860.864 250.020 1860.888 ;
    END
  END rx[335]
  PIN rx[336]
    DIRECTION OUTPUT ;
    USE SIGNAL ;
    SHAPE ABUTMENT ;
    PORT
      LAYER M4 ;
      RECT 249.828 1863.072 250.020 1863.096 ;
    END
  END rx[336]
  PIN rx[337]
    DIRECTION OUTPUT ;
    USE SIGNAL ;
    SHAPE ABUTMENT ;
    PORT
      LAYER M4 ;
      RECT 249.828 1865.280 250.020 1865.304 ;
    END
  END rx[337]
  PIN rx[338]
    DIRECTION OUTPUT ;
    USE SIGNAL ;
    SHAPE ABUTMENT ;
    PORT
      LAYER M4 ;
      RECT 249.828 1867.440 250.020 1867.464 ;
    END
  END rx[338]
  PIN rx[339]
    DIRECTION OUTPUT ;
    USE SIGNAL ;
    SHAPE ABUTMENT ;
    PORT
      LAYER M4 ;
      RECT 249.828 1869.648 250.020 1869.672 ;
    END
  END rx[339]
  PIN rx[340]
    DIRECTION OUTPUT ;
    USE SIGNAL ;
    SHAPE ABUTMENT ;
    PORT
      LAYER M4 ;
      RECT 249.828 1871.856 250.020 1871.880 ;
    END
  END rx[340]
  PIN rx[341]
    DIRECTION OUTPUT ;
    USE SIGNAL ;
    SHAPE ABUTMENT ;
    PORT
      LAYER M4 ;
      RECT 249.828 1874.064 250.020 1874.088 ;
    END
  END rx[341]
  PIN rx[342]
    DIRECTION OUTPUT ;
    USE SIGNAL ;
    SHAPE ABUTMENT ;
    PORT
      LAYER M4 ;
      RECT 249.828 1876.272 250.020 1876.296 ;
    END
  END rx[342]
  PIN rx[343]
    DIRECTION OUTPUT ;
    USE SIGNAL ;
    SHAPE ABUTMENT ;
    PORT
      LAYER M4 ;
      RECT 249.828 1878.432 250.020 1878.456 ;
    END
  END rx[343]
  PIN rx[344]
    DIRECTION OUTPUT ;
    USE SIGNAL ;
    SHAPE ABUTMENT ;
    PORT
      LAYER M4 ;
      RECT 249.828 1880.640 250.020 1880.664 ;
    END
  END rx[344]
  PIN rx[345]
    DIRECTION OUTPUT ;
    USE SIGNAL ;
    SHAPE ABUTMENT ;
    PORT
      LAYER M4 ;
      RECT 249.828 1882.848 250.020 1882.872 ;
    END
  END rx[345]
  PIN rx[346]
    DIRECTION OUTPUT ;
    USE SIGNAL ;
    SHAPE ABUTMENT ;
    PORT
      LAYER M4 ;
      RECT 249.828 1885.056 250.020 1885.080 ;
    END
  END rx[346]
  PIN rx[347]
    DIRECTION OUTPUT ;
    USE SIGNAL ;
    SHAPE ABUTMENT ;
    PORT
      LAYER M4 ;
      RECT 249.828 1887.216 250.020 1887.240 ;
    END
  END rx[347]
  PIN rx[348]
    DIRECTION OUTPUT ;
    USE SIGNAL ;
    SHAPE ABUTMENT ;
    PORT
      LAYER M4 ;
      RECT 249.828 1889.424 250.020 1889.448 ;
    END
  END rx[348]
  PIN rx[349]
    DIRECTION OUTPUT ;
    USE SIGNAL ;
    SHAPE ABUTMENT ;
    PORT
      LAYER M4 ;
      RECT 249.828 1891.632 250.020 1891.656 ;
    END
  END rx[349]
  PIN rx[350]
    DIRECTION OUTPUT ;
    USE SIGNAL ;
    SHAPE ABUTMENT ;
    PORT
      LAYER M4 ;
      RECT 249.828 1893.840 250.020 1893.864 ;
    END
  END rx[350]
  PIN rx[351]
    DIRECTION OUTPUT ;
    USE SIGNAL ;
    SHAPE ABUTMENT ;
    PORT
      LAYER M4 ;
      RECT 249.828 1896.000 250.020 1896.024 ;
    END
  END rx[351]
  PIN rx[352]
    DIRECTION OUTPUT ;
    USE SIGNAL ;
    SHAPE ABUTMENT ;
    PORT
      LAYER M4 ;
      RECT 249.828 1898.208 250.020 1898.232 ;
    END
  END rx[352]
  PIN rx[353]
    DIRECTION OUTPUT ;
    USE SIGNAL ;
    SHAPE ABUTMENT ;
    PORT
      LAYER M4 ;
      RECT 249.828 1900.416 250.020 1900.440 ;
    END
  END rx[353]
  PIN rx[354]
    DIRECTION OUTPUT ;
    USE SIGNAL ;
    SHAPE ABUTMENT ;
    PORT
      LAYER M4 ;
      RECT 249.828 1902.624 250.020 1902.648 ;
    END
  END rx[354]
  PIN rx[355]
    DIRECTION OUTPUT ;
    USE SIGNAL ;
    SHAPE ABUTMENT ;
    PORT
      LAYER M4 ;
      RECT 249.828 1904.784 250.020 1904.808 ;
    END
  END rx[355]
  PIN rx[356]
    DIRECTION OUTPUT ;
    USE SIGNAL ;
    SHAPE ABUTMENT ;
    PORT
      LAYER M4 ;
      RECT 249.828 1906.992 250.020 1907.016 ;
    END
  END rx[356]
  PIN rx[357]
    DIRECTION OUTPUT ;
    USE SIGNAL ;
    SHAPE ABUTMENT ;
    PORT
      LAYER M4 ;
      RECT 249.828 1909.200 250.020 1909.224 ;
    END
  END rx[357]
  PIN rx[358]
    DIRECTION OUTPUT ;
    USE SIGNAL ;
    SHAPE ABUTMENT ;
    PORT
      LAYER M4 ;
      RECT 249.828 1911.408 250.020 1911.432 ;
    END
  END rx[358]
  PIN rx[359]
    DIRECTION OUTPUT ;
    USE SIGNAL ;
    SHAPE ABUTMENT ;
    PORT
      LAYER M4 ;
      RECT 249.828 1913.568 250.020 1913.592 ;
    END
  END rx[359]
  PIN rx[360]
    DIRECTION OUTPUT ;
    USE SIGNAL ;
    SHAPE ABUTMENT ;
    PORT
      LAYER M4 ;
      RECT 249.828 1915.776 250.020 1915.800 ;
    END
  END rx[360]
  PIN rx[361]
    DIRECTION OUTPUT ;
    USE SIGNAL ;
    SHAPE ABUTMENT ;
    PORT
      LAYER M4 ;
      RECT 249.828 1917.984 250.020 1918.008 ;
    END
  END rx[361]
  PIN rx[362]
    DIRECTION OUTPUT ;
    USE SIGNAL ;
    SHAPE ABUTMENT ;
    PORT
      LAYER M4 ;
      RECT 249.828 1920.192 250.020 1920.216 ;
    END
  END rx[362]
  PIN rx[363]
    DIRECTION OUTPUT ;
    USE SIGNAL ;
    SHAPE ABUTMENT ;
    PORT
      LAYER M4 ;
      RECT 249.828 1922.352 250.020 1922.376 ;
    END
  END rx[363]
  PIN rx[364]
    DIRECTION OUTPUT ;
    USE SIGNAL ;
    SHAPE ABUTMENT ;
    PORT
      LAYER M4 ;
      RECT 249.828 1924.560 250.020 1924.584 ;
    END
  END rx[364]
  PIN rx[365]
    DIRECTION OUTPUT ;
    USE SIGNAL ;
    SHAPE ABUTMENT ;
    PORT
      LAYER M4 ;
      RECT 249.828 1926.768 250.020 1926.792 ;
    END
  END rx[365]
  PIN rx[366]
    DIRECTION OUTPUT ;
    USE SIGNAL ;
    SHAPE ABUTMENT ;
    PORT
      LAYER M4 ;
      RECT 249.828 1928.976 250.020 1929.000 ;
    END
  END rx[366]
  PIN rx[367]
    DIRECTION OUTPUT ;
    USE SIGNAL ;
    SHAPE ABUTMENT ;
    PORT
      LAYER M4 ;
      RECT 249.828 1931.136 250.020 1931.160 ;
    END
  END rx[367]
  PIN rx[368]
    DIRECTION OUTPUT ;
    USE SIGNAL ;
    SHAPE ABUTMENT ;
    PORT
      LAYER M4 ;
      RECT 249.828 1933.344 250.020 1933.368 ;
    END
  END rx[368]
  PIN rx[369]
    DIRECTION OUTPUT ;
    USE SIGNAL ;
    SHAPE ABUTMENT ;
    PORT
      LAYER M4 ;
      RECT 249.828 1935.552 250.020 1935.576 ;
    END
  END rx[369]
  PIN rx[370]
    DIRECTION OUTPUT ;
    USE SIGNAL ;
    SHAPE ABUTMENT ;
    PORT
      LAYER M4 ;
      RECT 249.828 1937.760 250.020 1937.784 ;
    END
  END rx[370]
  PIN rx[371]
    DIRECTION OUTPUT ;
    USE SIGNAL ;
    SHAPE ABUTMENT ;
    PORT
      LAYER M4 ;
      RECT 249.828 1939.968 250.020 1939.992 ;
    END
  END rx[371]
  PIN rx[372]
    DIRECTION OUTPUT ;
    USE SIGNAL ;
    SHAPE ABUTMENT ;
    PORT
      LAYER M4 ;
      RECT 249.828 1942.128 250.020 1942.152 ;
    END
  END rx[372]
  PIN rx[373]
    DIRECTION OUTPUT ;
    USE SIGNAL ;
    SHAPE ABUTMENT ;
    PORT
      LAYER M4 ;
      RECT 249.828 1944.336 250.020 1944.360 ;
    END
  END rx[373]
  PIN rx[374]
    DIRECTION OUTPUT ;
    USE SIGNAL ;
    SHAPE ABUTMENT ;
    PORT
      LAYER M4 ;
      RECT 249.828 1946.544 250.020 1946.568 ;
    END
  END rx[374]
  PIN rx[375]
    DIRECTION OUTPUT ;
    USE SIGNAL ;
    SHAPE ABUTMENT ;
    PORT
      LAYER M4 ;
      RECT 249.828 1948.752 250.020 1948.776 ;
    END
  END rx[375]
  PIN rx[376]
    DIRECTION OUTPUT ;
    USE SIGNAL ;
    SHAPE ABUTMENT ;
    PORT
      LAYER M4 ;
      RECT 249.828 1950.912 250.020 1950.936 ;
    END
  END rx[376]
  PIN rx[377]
    DIRECTION OUTPUT ;
    USE SIGNAL ;
    SHAPE ABUTMENT ;
    PORT
      LAYER M4 ;
      RECT 249.828 1953.120 250.020 1953.144 ;
    END
  END rx[377]
  PIN rx[378]
    DIRECTION OUTPUT ;
    USE SIGNAL ;
    SHAPE ABUTMENT ;
    PORT
      LAYER M4 ;
      RECT 249.828 1955.328 250.020 1955.352 ;
    END
  END rx[378]
  PIN rx[379]
    DIRECTION OUTPUT ;
    USE SIGNAL ;
    SHAPE ABUTMENT ;
    PORT
      LAYER M4 ;
      RECT 249.828 1957.536 250.020 1957.560 ;
    END
  END rx[379]
  PIN rx[380]
    DIRECTION OUTPUT ;
    USE SIGNAL ;
    SHAPE ABUTMENT ;
    PORT
      LAYER M4 ;
      RECT 249.828 1959.696 250.020 1959.720 ;
    END
  END rx[380]
  PIN rx[381]
    DIRECTION OUTPUT ;
    USE SIGNAL ;
    SHAPE ABUTMENT ;
    PORT
      LAYER M4 ;
      RECT 249.828 1961.904 250.020 1961.928 ;
    END
  END rx[381]
  PIN rx[382]
    DIRECTION OUTPUT ;
    USE SIGNAL ;
    SHAPE ABUTMENT ;
    PORT
      LAYER M4 ;
      RECT 249.828 1964.112 250.020 1964.136 ;
    END
  END rx[382]
  PIN rx[383]
    DIRECTION OUTPUT ;
    USE SIGNAL ;
    SHAPE ABUTMENT ;
    PORT
      LAYER M4 ;
      RECT 249.828 1966.320 250.020 1966.344 ;
    END
  END rx[383]
  PIN rx[384]
    DIRECTION OUTPUT ;
    USE SIGNAL ;
    SHAPE ABUTMENT ;
    PORT
      LAYER M4 ;
      RECT 249.828 1968.480 250.020 1968.504 ;
    END
  END rx[384]
  PIN rx[385]
    DIRECTION OUTPUT ;
    USE SIGNAL ;
    SHAPE ABUTMENT ;
    PORT
      LAYER M4 ;
      RECT 249.828 1970.688 250.020 1970.712 ;
    END
  END rx[385]
  PIN rx[386]
    DIRECTION OUTPUT ;
    USE SIGNAL ;
    SHAPE ABUTMENT ;
    PORT
      LAYER M4 ;
      RECT 249.828 1972.896 250.020 1972.920 ;
    END
  END rx[386]
  PIN rx[387]
    DIRECTION OUTPUT ;
    USE SIGNAL ;
    SHAPE ABUTMENT ;
    PORT
      LAYER M4 ;
      RECT 249.828 1975.104 250.020 1975.128 ;
    END
  END rx[387]
  PIN rx[388]
    DIRECTION OUTPUT ;
    USE SIGNAL ;
    SHAPE ABUTMENT ;
    PORT
      LAYER M4 ;
      RECT 249.828 1977.264 250.020 1977.288 ;
    END
  END rx[388]
  PIN rx[389]
    DIRECTION OUTPUT ;
    USE SIGNAL ;
    SHAPE ABUTMENT ;
    PORT
      LAYER M4 ;
      RECT 249.828 1979.472 250.020 1979.496 ;
    END
  END rx[389]
  PIN rx[390]
    DIRECTION OUTPUT ;
    USE SIGNAL ;
    SHAPE ABUTMENT ;
    PORT
      LAYER M4 ;
      RECT 249.828 1981.680 250.020 1981.704 ;
    END
  END rx[390]
  PIN rx[391]
    DIRECTION OUTPUT ;
    USE SIGNAL ;
    SHAPE ABUTMENT ;
    PORT
      LAYER M4 ;
      RECT 249.828 1983.888 250.020 1983.912 ;
    END
  END rx[391]
  PIN rx[392]
    DIRECTION OUTPUT ;
    USE SIGNAL ;
    SHAPE ABUTMENT ;
    PORT
      LAYER M4 ;
      RECT 249.828 1986.048 250.020 1986.072 ;
    END
  END rx[392]
  PIN rx[393]
    DIRECTION OUTPUT ;
    USE SIGNAL ;
    SHAPE ABUTMENT ;
    PORT
      LAYER M4 ;
      RECT 249.828 1988.256 250.020 1988.280 ;
    END
  END rx[393]
  PIN rx[394]
    DIRECTION OUTPUT ;
    USE SIGNAL ;
    SHAPE ABUTMENT ;
    PORT
      LAYER M4 ;
      RECT 249.828 1990.464 250.020 1990.488 ;
    END
  END rx[394]
  PIN rx[395]
    DIRECTION OUTPUT ;
    USE SIGNAL ;
    SHAPE ABUTMENT ;
    PORT
      LAYER M4 ;
      RECT 249.828 1992.672 250.020 1992.696 ;
    END
  END rx[395]
  PIN rx[396]
    DIRECTION OUTPUT ;
    USE SIGNAL ;
    SHAPE ABUTMENT ;
    PORT
      LAYER M4 ;
      RECT 249.828 1994.832 250.020 1994.856 ;
    END
  END rx[396]
  PIN rx[397]
    DIRECTION OUTPUT ;
    USE SIGNAL ;
    SHAPE ABUTMENT ;
    PORT
      LAYER M4 ;
      RECT 249.828 1997.040 250.020 1997.064 ;
    END
  END rx[397]
  PIN rx[398]
    DIRECTION OUTPUT ;
    USE SIGNAL ;
    SHAPE ABUTMENT ;
    PORT
      LAYER M4 ;
      RECT 249.828 1999.248 250.020 1999.272 ;
    END
  END rx[398]
  PIN rx[399]
    DIRECTION OUTPUT ;
    USE SIGNAL ;
    SHAPE ABUTMENT ;
    PORT
      LAYER M4 ;
      RECT 249.828 2001.456 250.020 2001.480 ;
    END
  END rx[399]
  PIN rx[400]
    DIRECTION OUTPUT ;
    USE SIGNAL ;
    SHAPE ABUTMENT ;
    PORT
      LAYER M4 ;
      RECT 249.828 2003.664 250.020 2003.688 ;
    END
  END rx[400]
  PIN rx[401]
    DIRECTION OUTPUT ;
    USE SIGNAL ;
    SHAPE ABUTMENT ;
    PORT
      LAYER M4 ;
      RECT 249.828 2005.824 250.020 2005.848 ;
    END
  END rx[401]
  PIN rx[402]
    DIRECTION OUTPUT ;
    USE SIGNAL ;
    SHAPE ABUTMENT ;
    PORT
      LAYER M4 ;
      RECT 249.828 2008.032 250.020 2008.056 ;
    END
  END rx[402]
  PIN rx[403]
    DIRECTION OUTPUT ;
    USE SIGNAL ;
    SHAPE ABUTMENT ;
    PORT
      LAYER M4 ;
      RECT 249.828 2010.240 250.020 2010.264 ;
    END
  END rx[403]
  PIN rx[404]
    DIRECTION OUTPUT ;
    USE SIGNAL ;
    SHAPE ABUTMENT ;
    PORT
      LAYER M4 ;
      RECT 249.828 2012.448 250.020 2012.472 ;
    END
  END rx[404]
  PIN rx[405]
    DIRECTION OUTPUT ;
    USE SIGNAL ;
    SHAPE ABUTMENT ;
    PORT
      LAYER M4 ;
      RECT 249.828 2014.608 250.020 2014.632 ;
    END
  END rx[405]
  PIN rx[406]
    DIRECTION OUTPUT ;
    USE SIGNAL ;
    SHAPE ABUTMENT ;
    PORT
      LAYER M4 ;
      RECT 249.828 2016.816 250.020 2016.840 ;
    END
  END rx[406]
  PIN rx[407]
    DIRECTION OUTPUT ;
    USE SIGNAL ;
    SHAPE ABUTMENT ;
    PORT
      LAYER M4 ;
      RECT 249.828 2019.024 250.020 2019.048 ;
    END
  END rx[407]
  PIN rx[408]
    DIRECTION OUTPUT ;
    USE SIGNAL ;
    SHAPE ABUTMENT ;
    PORT
      LAYER M4 ;
      RECT 249.828 2021.232 250.020 2021.256 ;
    END
  END rx[408]
  PIN rx[409]
    DIRECTION OUTPUT ;
    USE SIGNAL ;
    SHAPE ABUTMENT ;
    PORT
      LAYER M4 ;
      RECT 249.828 2023.392 250.020 2023.416 ;
    END
  END rx[409]
  PIN rx[410]
    DIRECTION OUTPUT ;
    USE SIGNAL ;
    SHAPE ABUTMENT ;
    PORT
      LAYER M4 ;
      RECT 249.828 2025.600 250.020 2025.624 ;
    END
  END rx[410]
  PIN rx[411]
    DIRECTION OUTPUT ;
    USE SIGNAL ;
    SHAPE ABUTMENT ;
    PORT
      LAYER M4 ;
      RECT 249.828 2027.808 250.020 2027.832 ;
    END
  END rx[411]
  PIN rx[412]
    DIRECTION OUTPUT ;
    USE SIGNAL ;
    SHAPE ABUTMENT ;
    PORT
      LAYER M4 ;
      RECT 249.828 2030.016 250.020 2030.040 ;
    END
  END rx[412]
  PIN rx[413]
    DIRECTION OUTPUT ;
    USE SIGNAL ;
    SHAPE ABUTMENT ;
    PORT
      LAYER M4 ;
      RECT 249.828 2032.176 250.020 2032.200 ;
    END
  END rx[413]
  PIN rx[414]
    DIRECTION OUTPUT ;
    USE SIGNAL ;
    SHAPE ABUTMENT ;
    PORT
      LAYER M4 ;
      RECT 249.828 2034.384 250.020 2034.408 ;
    END
  END rx[414]
  PIN rx[415]
    DIRECTION OUTPUT ;
    USE SIGNAL ;
    SHAPE ABUTMENT ;
    PORT
      LAYER M4 ;
      RECT 249.828 2036.592 250.020 2036.616 ;
    END
  END rx[415]
  PIN rx[416]
    DIRECTION OUTPUT ;
    USE SIGNAL ;
    SHAPE ABUTMENT ;
    PORT
      LAYER M4 ;
      RECT 249.828 2038.800 250.020 2038.824 ;
    END
  END rx[416]
  PIN rx[417]
    DIRECTION OUTPUT ;
    USE SIGNAL ;
    SHAPE ABUTMENT ;
    PORT
      LAYER M4 ;
      RECT 249.828 2040.960 250.020 2040.984 ;
    END
  END rx[417]
  PIN rx[418]
    DIRECTION OUTPUT ;
    USE SIGNAL ;
    SHAPE ABUTMENT ;
    PORT
      LAYER M4 ;
      RECT 249.828 2043.168 250.020 2043.192 ;
    END
  END rx[418]
  PIN rx[419]
    DIRECTION OUTPUT ;
    USE SIGNAL ;
    SHAPE ABUTMENT ;
    PORT
      LAYER M4 ;
      RECT 249.828 2045.376 250.020 2045.400 ;
    END
  END rx[419]
  PIN rx[420]
    DIRECTION OUTPUT ;
    USE SIGNAL ;
    SHAPE ABUTMENT ;
    PORT
      LAYER M4 ;
      RECT 249.828 2047.584 250.020 2047.608 ;
    END
  END rx[420]
  PIN rx[421]
    DIRECTION OUTPUT ;
    USE SIGNAL ;
    SHAPE ABUTMENT ;
    PORT
      LAYER M4 ;
      RECT 249.828 2049.744 250.020 2049.768 ;
    END
  END rx[421]
  PIN rx[422]
    DIRECTION OUTPUT ;
    USE SIGNAL ;
    SHAPE ABUTMENT ;
    PORT
      LAYER M4 ;
      RECT 249.828 2051.952 250.020 2051.976 ;
    END
  END rx[422]
  PIN rx[423]
    DIRECTION OUTPUT ;
    USE SIGNAL ;
    SHAPE ABUTMENT ;
    PORT
      LAYER M4 ;
      RECT 249.828 2054.160 250.020 2054.184 ;
    END
  END rx[423]
  PIN rx[424]
    DIRECTION OUTPUT ;
    USE SIGNAL ;
    SHAPE ABUTMENT ;
    PORT
      LAYER M4 ;
      RECT 249.828 2056.368 250.020 2056.392 ;
    END
  END rx[424]
  PIN rx[425]
    DIRECTION OUTPUT ;
    USE SIGNAL ;
    SHAPE ABUTMENT ;
    PORT
      LAYER M4 ;
      RECT 249.828 2058.528 250.020 2058.552 ;
    END
  END rx[425]
  PIN rx[426]
    DIRECTION OUTPUT ;
    USE SIGNAL ;
    SHAPE ABUTMENT ;
    PORT
      LAYER M4 ;
      RECT 249.828 2060.736 250.020 2060.760 ;
    END
  END rx[426]
  PIN rx[427]
    DIRECTION OUTPUT ;
    USE SIGNAL ;
    SHAPE ABUTMENT ;
    PORT
      LAYER M4 ;
      RECT 249.828 2062.944 250.020 2062.968 ;
    END
  END rx[427]
  PIN rx[428]
    DIRECTION OUTPUT ;
    USE SIGNAL ;
    SHAPE ABUTMENT ;
    PORT
      LAYER M4 ;
      RECT 249.828 2065.152 250.020 2065.176 ;
    END
  END rx[428]
  PIN rx[429]
    DIRECTION OUTPUT ;
    USE SIGNAL ;
    SHAPE ABUTMENT ;
    PORT
      LAYER M4 ;
      RECT 249.828 2067.360 250.020 2067.384 ;
    END
  END rx[429]
  PIN rx[430]
    DIRECTION OUTPUT ;
    USE SIGNAL ;
    SHAPE ABUTMENT ;
    PORT
      LAYER M4 ;
      RECT 249.828 2069.520 250.020 2069.544 ;
    END
  END rx[430]
  PIN rx[431]
    DIRECTION OUTPUT ;
    USE SIGNAL ;
    SHAPE ABUTMENT ;
    PORT
      LAYER M4 ;
      RECT 249.828 2071.728 250.020 2071.752 ;
    END
  END rx[431]
  PIN rx[432]
    DIRECTION OUTPUT ;
    USE SIGNAL ;
    SHAPE ABUTMENT ;
    PORT
      LAYER M4 ;
      RECT 249.828 2073.936 250.020 2073.960 ;
    END
  END rx[432]
  PIN rx[433]
    DIRECTION OUTPUT ;
    USE SIGNAL ;
    SHAPE ABUTMENT ;
    PORT
      LAYER M4 ;
      RECT 249.828 2076.144 250.020 2076.168 ;
    END
  END rx[433]
  PIN rx[434]
    DIRECTION OUTPUT ;
    USE SIGNAL ;
    SHAPE ABUTMENT ;
    PORT
      LAYER M4 ;
      RECT 249.828 2078.304 250.020 2078.328 ;
    END
  END rx[434]
  PIN rx[435]
    DIRECTION OUTPUT ;
    USE SIGNAL ;
    SHAPE ABUTMENT ;
    PORT
      LAYER M4 ;
      RECT 249.828 2080.512 250.020 2080.536 ;
    END
  END rx[435]
  PIN rx[436]
    DIRECTION OUTPUT ;
    USE SIGNAL ;
    SHAPE ABUTMENT ;
    PORT
      LAYER M4 ;
      RECT 249.828 2082.720 250.020 2082.744 ;
    END
  END rx[436]
  PIN rx[437]
    DIRECTION OUTPUT ;
    USE SIGNAL ;
    SHAPE ABUTMENT ;
    PORT
      LAYER M4 ;
      RECT 249.828 2084.928 250.020 2084.952 ;
    END
  END rx[437]
  PIN rx[438]
    DIRECTION OUTPUT ;
    USE SIGNAL ;
    SHAPE ABUTMENT ;
    PORT
      LAYER M4 ;
      RECT 249.828 2087.088 250.020 2087.112 ;
    END
  END rx[438]
  PIN rx[439]
    DIRECTION OUTPUT ;
    USE SIGNAL ;
    SHAPE ABUTMENT ;
    PORT
      LAYER M4 ;
      RECT 249.828 2089.296 250.020 2089.320 ;
    END
  END rx[439]
  PIN rx[440]
    DIRECTION OUTPUT ;
    USE SIGNAL ;
    SHAPE ABUTMENT ;
    PORT
      LAYER M4 ;
      RECT 249.828 2091.504 250.020 2091.528 ;
    END
  END rx[440]
  PIN rx[441]
    DIRECTION OUTPUT ;
    USE SIGNAL ;
    SHAPE ABUTMENT ;
    PORT
      LAYER M4 ;
      RECT 249.828 2093.712 250.020 2093.736 ;
    END
  END rx[441]
  PIN rx[442]
    DIRECTION OUTPUT ;
    USE SIGNAL ;
    SHAPE ABUTMENT ;
    PORT
      LAYER M4 ;
      RECT 249.828 2095.872 250.020 2095.896 ;
    END
  END rx[442]
  PIN rx[443]
    DIRECTION OUTPUT ;
    USE SIGNAL ;
    SHAPE ABUTMENT ;
    PORT
      LAYER M4 ;
      RECT 249.828 2098.080 250.020 2098.104 ;
    END
  END rx[443]
  PIN rx[444]
    DIRECTION OUTPUT ;
    USE SIGNAL ;
    SHAPE ABUTMENT ;
    PORT
      LAYER M4 ;
      RECT 249.828 2100.288 250.020 2100.312 ;
    END
  END rx[444]
  PIN rx[445]
    DIRECTION OUTPUT ;
    USE SIGNAL ;
    SHAPE ABUTMENT ;
    PORT
      LAYER M4 ;
      RECT 249.828 2102.496 250.020 2102.520 ;
    END
  END rx[445]
  PIN rx[446]
    DIRECTION OUTPUT ;
    USE SIGNAL ;
    SHAPE ABUTMENT ;
    PORT
      LAYER M4 ;
      RECT 249.828 2104.656 250.020 2104.680 ;
    END
  END rx[446]
  PIN rx[447]
    DIRECTION OUTPUT ;
    USE SIGNAL ;
    SHAPE ABUTMENT ;
    PORT
      LAYER M4 ;
      RECT 249.828 2106.864 250.020 2106.888 ;
    END
  END rx[447]
  PIN rx[448]
    DIRECTION OUTPUT ;
    USE SIGNAL ;
    SHAPE ABUTMENT ;
    PORT
      LAYER M4 ;
      RECT 249.828 2109.072 250.020 2109.096 ;
    END
  END rx[448]
  PIN rx[449]
    DIRECTION OUTPUT ;
    USE SIGNAL ;
    SHAPE ABUTMENT ;
    PORT
      LAYER M4 ;
      RECT 249.828 2111.280 250.020 2111.304 ;
    END
  END rx[449]
  PIN rx[450]
    DIRECTION OUTPUT ;
    USE SIGNAL ;
    SHAPE ABUTMENT ;
    PORT
      LAYER M4 ;
      RECT 249.828 2113.440 250.020 2113.464 ;
    END
  END rx[450]
  PIN rx[451]
    DIRECTION OUTPUT ;
    USE SIGNAL ;
    SHAPE ABUTMENT ;
    PORT
      LAYER M4 ;
      RECT 249.828 2115.648 250.020 2115.672 ;
    END
  END rx[451]
  PIN rx[452]
    DIRECTION OUTPUT ;
    USE SIGNAL ;
    SHAPE ABUTMENT ;
    PORT
      LAYER M4 ;
      RECT 249.828 2117.856 250.020 2117.880 ;
    END
  END rx[452]
  PIN rx[453]
    DIRECTION OUTPUT ;
    USE SIGNAL ;
    SHAPE ABUTMENT ;
    PORT
      LAYER M4 ;
      RECT 249.828 2120.064 250.020 2120.088 ;
    END
  END rx[453]
  PIN rx[454]
    DIRECTION OUTPUT ;
    USE SIGNAL ;
    SHAPE ABUTMENT ;
    PORT
      LAYER M4 ;
      RECT 249.828 2122.224 250.020 2122.248 ;
    END
  END rx[454]
  PIN rx[455]
    DIRECTION OUTPUT ;
    USE SIGNAL ;
    SHAPE ABUTMENT ;
    PORT
      LAYER M4 ;
      RECT 249.828 2124.432 250.020 2124.456 ;
    END
  END rx[455]
  PIN rx[456]
    DIRECTION OUTPUT ;
    USE SIGNAL ;
    SHAPE ABUTMENT ;
    PORT
      LAYER M4 ;
      RECT 249.828 2126.640 250.020 2126.664 ;
    END
  END rx[456]
  PIN rx[457]
    DIRECTION OUTPUT ;
    USE SIGNAL ;
    SHAPE ABUTMENT ;
    PORT
      LAYER M4 ;
      RECT 249.828 2128.848 250.020 2128.872 ;
    END
  END rx[457]
  PIN rx[458]
    DIRECTION OUTPUT ;
    USE SIGNAL ;
    SHAPE ABUTMENT ;
    PORT
      LAYER M4 ;
      RECT 249.828 2131.056 250.020 2131.080 ;
    END
  END rx[458]
  PIN rx[459]
    DIRECTION OUTPUT ;
    USE SIGNAL ;
    SHAPE ABUTMENT ;
    PORT
      LAYER M4 ;
      RECT 249.828 2133.216 250.020 2133.240 ;
    END
  END rx[459]
  PIN rx[460]
    DIRECTION OUTPUT ;
    USE SIGNAL ;
    SHAPE ABUTMENT ;
    PORT
      LAYER M4 ;
      RECT 249.828 2135.424 250.020 2135.448 ;
    END
  END rx[460]
  PIN rx[461]
    DIRECTION OUTPUT ;
    USE SIGNAL ;
    SHAPE ABUTMENT ;
    PORT
      LAYER M4 ;
      RECT 249.828 2137.632 250.020 2137.656 ;
    END
  END rx[461]
  PIN rx[462]
    DIRECTION OUTPUT ;
    USE SIGNAL ;
    SHAPE ABUTMENT ;
    PORT
      LAYER M4 ;
      RECT 249.828 2139.840 250.020 2139.864 ;
    END
  END rx[462]
  PIN rx[463]
    DIRECTION OUTPUT ;
    USE SIGNAL ;
    SHAPE ABUTMENT ;
    PORT
      LAYER M4 ;
      RECT 249.828 2142.000 250.020 2142.024 ;
    END
  END rx[463]
  PIN rx[464]
    DIRECTION OUTPUT ;
    USE SIGNAL ;
    SHAPE ABUTMENT ;
    PORT
      LAYER M4 ;
      RECT 249.828 2144.208 250.020 2144.232 ;
    END
  END rx[464]
  PIN rx[465]
    DIRECTION OUTPUT ;
    USE SIGNAL ;
    SHAPE ABUTMENT ;
    PORT
      LAYER M4 ;
      RECT 249.828 2146.416 250.020 2146.440 ;
    END
  END rx[465]
  PIN rx[466]
    DIRECTION OUTPUT ;
    USE SIGNAL ;
    SHAPE ABUTMENT ;
    PORT
      LAYER M4 ;
      RECT 249.828 2148.624 250.020 2148.648 ;
    END
  END rx[466]
  PIN rx[467]
    DIRECTION OUTPUT ;
    USE SIGNAL ;
    SHAPE ABUTMENT ;
    PORT
      LAYER M4 ;
      RECT 249.828 2150.784 250.020 2150.808 ;
    END
  END rx[467]
  PIN rx[468]
    DIRECTION OUTPUT ;
    USE SIGNAL ;
    SHAPE ABUTMENT ;
    PORT
      LAYER M4 ;
      RECT 249.828 2152.992 250.020 2153.016 ;
    END
  END rx[468]
  PIN rx[469]
    DIRECTION OUTPUT ;
    USE SIGNAL ;
    SHAPE ABUTMENT ;
    PORT
      LAYER M4 ;
      RECT 249.828 2155.200 250.020 2155.224 ;
    END
  END rx[469]
  PIN rx[470]
    DIRECTION OUTPUT ;
    USE SIGNAL ;
    SHAPE ABUTMENT ;
    PORT
      LAYER M4 ;
      RECT 249.828 2157.408 250.020 2157.432 ;
    END
  END rx[470]
  PIN rx[471]
    DIRECTION OUTPUT ;
    USE SIGNAL ;
    SHAPE ABUTMENT ;
    PORT
      LAYER M4 ;
      RECT 249.828 2159.568 250.020 2159.592 ;
    END
  END rx[471]
  PIN rx[472]
    DIRECTION OUTPUT ;
    USE SIGNAL ;
    SHAPE ABUTMENT ;
    PORT
      LAYER M4 ;
      RECT 249.828 2161.776 250.020 2161.800 ;
    END
  END rx[472]
  PIN rx[473]
    DIRECTION OUTPUT ;
    USE SIGNAL ;
    SHAPE ABUTMENT ;
    PORT
      LAYER M4 ;
      RECT 249.828 2163.984 250.020 2164.008 ;
    END
  END rx[473]
  PIN rx[474]
    DIRECTION OUTPUT ;
    USE SIGNAL ;
    SHAPE ABUTMENT ;
    PORT
      LAYER M4 ;
      RECT 249.828 2166.192 250.020 2166.216 ;
    END
  END rx[474]
  PIN rx[475]
    DIRECTION OUTPUT ;
    USE SIGNAL ;
    SHAPE ABUTMENT ;
    PORT
      LAYER M4 ;
      RECT 249.828 2168.352 250.020 2168.376 ;
    END
  END rx[475]
  PIN rx[476]
    DIRECTION OUTPUT ;
    USE SIGNAL ;
    SHAPE ABUTMENT ;
    PORT
      LAYER M4 ;
      RECT 249.828 2170.560 250.020 2170.584 ;
    END
  END rx[476]
  PIN rx[477]
    DIRECTION OUTPUT ;
    USE SIGNAL ;
    SHAPE ABUTMENT ;
    PORT
      LAYER M4 ;
      RECT 249.828 2172.768 250.020 2172.792 ;
    END
  END rx[477]
  PIN rx[478]
    DIRECTION OUTPUT ;
    USE SIGNAL ;
    SHAPE ABUTMENT ;
    PORT
      LAYER M4 ;
      RECT 249.828 2174.976 250.020 2175.000 ;
    END
  END rx[478]
  PIN rx[479]
    DIRECTION OUTPUT ;
    USE SIGNAL ;
    SHAPE ABUTMENT ;
    PORT
      LAYER M4 ;
      RECT 249.828 2177.136 250.020 2177.160 ;
    END
  END rx[479]
  PIN rx[480]
    DIRECTION OUTPUT ;
    USE SIGNAL ;
    SHAPE ABUTMENT ;
    PORT
      LAYER M4 ;
      RECT 249.828 2179.344 250.020 2179.368 ;
    END
  END rx[480]
  PIN rx[481]
    DIRECTION OUTPUT ;
    USE SIGNAL ;
    SHAPE ABUTMENT ;
    PORT
      LAYER M4 ;
      RECT 249.828 2181.552 250.020 2181.576 ;
    END
  END rx[481]
  PIN rx[482]
    DIRECTION OUTPUT ;
    USE SIGNAL ;
    SHAPE ABUTMENT ;
    PORT
      LAYER M4 ;
      RECT 249.828 2183.760 250.020 2183.784 ;
    END
  END rx[482]
  PIN rx[483]
    DIRECTION OUTPUT ;
    USE SIGNAL ;
    SHAPE ABUTMENT ;
    PORT
      LAYER M4 ;
      RECT 249.828 2185.920 250.020 2185.944 ;
    END
  END rx[483]
  PIN rx[484]
    DIRECTION OUTPUT ;
    USE SIGNAL ;
    SHAPE ABUTMENT ;
    PORT
      LAYER M4 ;
      RECT 249.828 2188.128 250.020 2188.152 ;
    END
  END rx[484]
  PIN rx[485]
    DIRECTION OUTPUT ;
    USE SIGNAL ;
    SHAPE ABUTMENT ;
    PORT
      LAYER M4 ;
      RECT 249.828 2190.336 250.020 2190.360 ;
    END
  END rx[485]
  PIN rx[486]
    DIRECTION OUTPUT ;
    USE SIGNAL ;
    SHAPE ABUTMENT ;
    PORT
      LAYER M4 ;
      RECT 249.828 2192.544 250.020 2192.568 ;
    END
  END rx[486]
  PIN rx[487]
    DIRECTION OUTPUT ;
    USE SIGNAL ;
    SHAPE ABUTMENT ;
    PORT
      LAYER M4 ;
      RECT 249.828 2194.752 250.020 2194.776 ;
    END
  END rx[487]
  PIN rx[488]
    DIRECTION OUTPUT ;
    USE SIGNAL ;
    SHAPE ABUTMENT ;
    PORT
      LAYER M4 ;
      RECT 249.828 2196.912 250.020 2196.936 ;
    END
  END rx[488]
  PIN rx[489]
    DIRECTION OUTPUT ;
    USE SIGNAL ;
    SHAPE ABUTMENT ;
    PORT
      LAYER M4 ;
      RECT 249.828 2199.120 250.020 2199.144 ;
    END
  END rx[489]
  PIN rx[490]
    DIRECTION OUTPUT ;
    USE SIGNAL ;
    SHAPE ABUTMENT ;
    PORT
      LAYER M4 ;
      RECT 249.828 2201.328 250.020 2201.352 ;
    END
  END rx[490]
  PIN rx[491]
    DIRECTION OUTPUT ;
    USE SIGNAL ;
    SHAPE ABUTMENT ;
    PORT
      LAYER M4 ;
      RECT 249.828 2203.536 250.020 2203.560 ;
    END
  END rx[491]
  PIN rx[492]
    DIRECTION OUTPUT ;
    USE SIGNAL ;
    SHAPE ABUTMENT ;
    PORT
      LAYER M4 ;
      RECT 249.828 2205.696 250.020 2205.720 ;
    END
  END rx[492]
  PIN rx[493]
    DIRECTION OUTPUT ;
    USE SIGNAL ;
    SHAPE ABUTMENT ;
    PORT
      LAYER M4 ;
      RECT 249.828 2207.904 250.020 2207.928 ;
    END
  END rx[493]
  PIN rx[494]
    DIRECTION OUTPUT ;
    USE SIGNAL ;
    SHAPE ABUTMENT ;
    PORT
      LAYER M4 ;
      RECT 249.828 2210.112 250.020 2210.136 ;
    END
  END rx[494]
  PIN rx[495]
    DIRECTION OUTPUT ;
    USE SIGNAL ;
    SHAPE ABUTMENT ;
    PORT
      LAYER M4 ;
      RECT 249.828 2212.320 250.020 2212.344 ;
    END
  END rx[495]
  PIN rx[496]
    DIRECTION OUTPUT ;
    USE SIGNAL ;
    SHAPE ABUTMENT ;
    PORT
      LAYER M4 ;
      RECT 249.828 2214.480 250.020 2214.504 ;
    END
  END rx[496]
  PIN rx[497]
    DIRECTION OUTPUT ;
    USE SIGNAL ;
    SHAPE ABUTMENT ;
    PORT
      LAYER M4 ;
      RECT 249.828 2216.688 250.020 2216.712 ;
    END
  END rx[497]
  PIN rx[498]
    DIRECTION OUTPUT ;
    USE SIGNAL ;
    SHAPE ABUTMENT ;
    PORT
      LAYER M4 ;
      RECT 249.828 2218.896 250.020 2218.920 ;
    END
  END rx[498]
  PIN rx[499]
    DIRECTION OUTPUT ;
    USE SIGNAL ;
    SHAPE ABUTMENT ;
    PORT
      LAYER M4 ;
      RECT 249.828 2221.104 250.020 2221.128 ;
    END
  END rx[499]
  PIN rx[500]
    DIRECTION OUTPUT ;
    USE SIGNAL ;
    SHAPE ABUTMENT ;
    PORT
      LAYER M4 ;
      RECT 249.828 2223.264 250.020 2223.288 ;
    END
  END rx[500]
  PIN rx[501]
    DIRECTION OUTPUT ;
    USE SIGNAL ;
    SHAPE ABUTMENT ;
    PORT
      LAYER M4 ;
      RECT 249.828 2225.472 250.020 2225.496 ;
    END
  END rx[501]
  PIN rx[502]
    DIRECTION OUTPUT ;
    USE SIGNAL ;
    SHAPE ABUTMENT ;
    PORT
      LAYER M4 ;
      RECT 249.828 2227.680 250.020 2227.704 ;
    END
  END rx[502]
  PIN rx[503]
    DIRECTION OUTPUT ;
    USE SIGNAL ;
    SHAPE ABUTMENT ;
    PORT
      LAYER M4 ;
      RECT 249.828 2229.888 250.020 2229.912 ;
    END
  END rx[503]
  PIN rx[504]
    DIRECTION OUTPUT ;
    USE SIGNAL ;
    SHAPE ABUTMENT ;
    PORT
      LAYER M4 ;
      RECT 249.828 2232.048 250.020 2232.072 ;
    END
  END rx[504]
  PIN rx[505]
    DIRECTION OUTPUT ;
    USE SIGNAL ;
    SHAPE ABUTMENT ;
    PORT
      LAYER M4 ;
      RECT 249.828 2234.256 250.020 2234.280 ;
    END
  END rx[505]
  PIN rx[506]
    DIRECTION OUTPUT ;
    USE SIGNAL ;
    SHAPE ABUTMENT ;
    PORT
      LAYER M4 ;
      RECT 249.828 2236.464 250.020 2236.488 ;
    END
  END rx[506]
  PIN rx[507]
    DIRECTION OUTPUT ;
    USE SIGNAL ;
    SHAPE ABUTMENT ;
    PORT
      LAYER M4 ;
      RECT 249.828 2238.672 250.020 2238.696 ;
    END
  END rx[507]
  PIN rx[508]
    DIRECTION OUTPUT ;
    USE SIGNAL ;
    SHAPE ABUTMENT ;
    PORT
      LAYER M4 ;
      RECT 249.828 2240.832 250.020 2240.856 ;
    END
  END rx[508]
  PIN rx[509]
    DIRECTION OUTPUT ;
    USE SIGNAL ;
    SHAPE ABUTMENT ;
    PORT
      LAYER M4 ;
      RECT 249.828 2243.040 250.020 2243.064 ;
    END
  END rx[509]
  PIN rx[510]
    DIRECTION OUTPUT ;
    USE SIGNAL ;
    SHAPE ABUTMENT ;
    PORT
      LAYER M4 ;
      RECT 249.828 2245.248 250.020 2245.272 ;
    END
  END rx[510]
  PIN rx[511]
    DIRECTION OUTPUT ;
    USE SIGNAL ;
    SHAPE ABUTMENT ;
    PORT
      LAYER M4 ;
      RECT 249.828 2247.456 250.020 2247.480 ;
    END
  END rx[511]
  PIN VSS
    DIRECTION INOUT ;
    USE GROUND ;
    PORT
      LAYER M4 ;
      RECT 0.492 1.200 249.528 1.296 ;
      RECT 0.492 3.600 249.528 3.696 ;
      RECT 0.492 6.000 249.528 6.096 ;
      RECT 0.492 8.400 249.528 8.496 ;
      RECT 0.492 10.800 249.528 10.896 ;
      RECT 0.492 13.200 249.528 13.296 ;
      RECT 0.492 15.600 249.528 15.696 ;
      RECT 0.492 18.000 249.528 18.096 ;
      RECT 0.492 20.400 249.528 20.496 ;
      RECT 0.492 22.800 249.528 22.896 ;
      RECT 0.492 25.200 249.528 25.296 ;
      RECT 0.492 27.600 249.528 27.696 ;
      RECT 0.492 30.000 249.528 30.096 ;
      RECT 0.492 32.400 249.528 32.496 ;
      RECT 0.492 34.800 249.528 34.896 ;
      RECT 0.492 37.200 249.528 37.296 ;
      RECT 0.492 39.600 249.528 39.696 ;
      RECT 0.492 42.000 249.528 42.096 ;
      RECT 0.492 44.400 249.528 44.496 ;
      RECT 0.492 46.800 249.528 46.896 ;
      RECT 0.492 49.200 249.528 49.296 ;
      RECT 0.492 51.600 249.528 51.696 ;
      RECT 0.492 54.000 249.528 54.096 ;
      RECT 0.492 56.400 249.528 56.496 ;
      RECT 0.492 58.800 249.528 58.896 ;
      RECT 0.492 61.200 249.528 61.296 ;
      RECT 0.492 63.600 249.528 63.696 ;
      RECT 0.492 66.000 249.528 66.096 ;
      RECT 0.492 68.400 249.528 68.496 ;
      RECT 0.492 70.800 249.528 70.896 ;
      RECT 0.492 73.200 249.528 73.296 ;
      RECT 0.492 75.600 249.528 75.696 ;
      RECT 0.492 78.000 249.528 78.096 ;
      RECT 0.492 80.400 249.528 80.496 ;
      RECT 0.492 82.800 249.528 82.896 ;
      RECT 0.492 85.200 249.528 85.296 ;
      RECT 0.492 87.600 249.528 87.696 ;
      RECT 0.492 90.000 249.528 90.096 ;
      RECT 0.492 92.400 249.528 92.496 ;
      RECT 0.492 94.800 249.528 94.896 ;
      RECT 0.492 97.200 249.528 97.296 ;
      RECT 0.492 99.600 249.528 99.696 ;
      RECT 0.492 102.000 249.528 102.096 ;
      RECT 0.492 104.400 249.528 104.496 ;
      RECT 0.492 106.800 249.528 106.896 ;
      RECT 0.492 109.200 249.528 109.296 ;
      RECT 0.492 111.600 249.528 111.696 ;
      RECT 0.492 114.000 249.528 114.096 ;
      RECT 0.492 116.400 249.528 116.496 ;
      RECT 0.492 118.800 249.528 118.896 ;
      RECT 0.492 121.200 249.528 121.296 ;
      RECT 0.492 123.600 249.528 123.696 ;
      RECT 0.492 126.000 249.528 126.096 ;
      RECT 0.492 128.400 249.528 128.496 ;
      RECT 0.492 130.800 249.528 130.896 ;
      RECT 0.492 133.200 249.528 133.296 ;
      RECT 0.492 135.600 249.528 135.696 ;
      RECT 0.492 138.000 249.528 138.096 ;
      RECT 0.492 140.400 249.528 140.496 ;
      RECT 0.492 142.800 249.528 142.896 ;
      RECT 0.492 145.200 249.528 145.296 ;
      RECT 0.492 147.600 249.528 147.696 ;
      RECT 0.492 150.000 249.528 150.096 ;
      RECT 0.492 152.400 249.528 152.496 ;
      RECT 0.492 154.800 249.528 154.896 ;
      RECT 0.492 157.200 249.528 157.296 ;
      RECT 0.492 159.600 249.528 159.696 ;
      RECT 0.492 162.000 249.528 162.096 ;
      RECT 0.492 164.400 249.528 164.496 ;
      RECT 0.492 166.800 249.528 166.896 ;
      RECT 0.492 169.200 249.528 169.296 ;
      RECT 0.492 171.600 249.528 171.696 ;
      RECT 0.492 174.000 249.528 174.096 ;
      RECT 0.492 176.400 249.528 176.496 ;
      RECT 0.492 178.800 249.528 178.896 ;
      RECT 0.492 181.200 249.528 181.296 ;
      RECT 0.492 183.600 249.528 183.696 ;
      RECT 0.492 186.000 249.528 186.096 ;
      RECT 0.492 188.400 249.528 188.496 ;
      RECT 0.492 190.800 249.528 190.896 ;
      RECT 0.492 193.200 249.528 193.296 ;
      RECT 0.492 195.600 249.528 195.696 ;
      RECT 0.492 198.000 249.528 198.096 ;
      RECT 0.492 200.400 249.528 200.496 ;
      RECT 0.492 202.800 249.528 202.896 ;
      RECT 0.492 205.200 249.528 205.296 ;
      RECT 0.492 207.600 249.528 207.696 ;
      RECT 0.492 210.000 249.528 210.096 ;
      RECT 0.492 212.400 249.528 212.496 ;
      RECT 0.492 214.800 249.528 214.896 ;
      RECT 0.492 217.200 249.528 217.296 ;
      RECT 0.492 219.600 249.528 219.696 ;
      RECT 0.492 222.000 249.528 222.096 ;
      RECT 0.492 224.400 249.528 224.496 ;
      RECT 0.492 226.800 249.528 226.896 ;
      RECT 0.492 229.200 249.528 229.296 ;
      RECT 0.492 231.600 249.528 231.696 ;
      RECT 0.492 234.000 249.528 234.096 ;
      RECT 0.492 236.400 249.528 236.496 ;
      RECT 0.492 238.800 249.528 238.896 ;
      RECT 0.492 241.200 249.528 241.296 ;
      RECT 0.492 243.600 249.528 243.696 ;
      RECT 0.492 246.000 249.528 246.096 ;
      RECT 0.492 248.400 249.528 248.496 ;
      RECT 0.492 250.800 249.528 250.896 ;
      RECT 0.492 253.200 249.528 253.296 ;
      RECT 0.492 255.600 249.528 255.696 ;
      RECT 0.492 258.000 249.528 258.096 ;
      RECT 0.492 260.400 249.528 260.496 ;
      RECT 0.492 262.800 249.528 262.896 ;
      RECT 0.492 265.200 249.528 265.296 ;
      RECT 0.492 267.600 249.528 267.696 ;
      RECT 0.492 270.000 249.528 270.096 ;
      RECT 0.492 272.400 249.528 272.496 ;
      RECT 0.492 274.800 249.528 274.896 ;
      RECT 0.492 277.200 249.528 277.296 ;
      RECT 0.492 279.600 249.528 279.696 ;
      RECT 0.492 282.000 249.528 282.096 ;
      RECT 0.492 284.400 249.528 284.496 ;
      RECT 0.492 286.800 249.528 286.896 ;
      RECT 0.492 289.200 249.528 289.296 ;
      RECT 0.492 291.600 249.528 291.696 ;
      RECT 0.492 294.000 249.528 294.096 ;
      RECT 0.492 296.400 249.528 296.496 ;
      RECT 0.492 298.800 249.528 298.896 ;
      RECT 0.492 301.200 249.528 301.296 ;
      RECT 0.492 303.600 249.528 303.696 ;
      RECT 0.492 306.000 249.528 306.096 ;
      RECT 0.492 308.400 249.528 308.496 ;
      RECT 0.492 310.800 249.528 310.896 ;
      RECT 0.492 313.200 249.528 313.296 ;
      RECT 0.492 315.600 249.528 315.696 ;
      RECT 0.492 318.000 249.528 318.096 ;
      RECT 0.492 320.400 249.528 320.496 ;
      RECT 0.492 322.800 249.528 322.896 ;
      RECT 0.492 325.200 249.528 325.296 ;
      RECT 0.492 327.600 249.528 327.696 ;
      RECT 0.492 330.000 249.528 330.096 ;
      RECT 0.492 332.400 249.528 332.496 ;
      RECT 0.492 334.800 249.528 334.896 ;
      RECT 0.492 337.200 249.528 337.296 ;
      RECT 0.492 339.600 249.528 339.696 ;
      RECT 0.492 342.000 249.528 342.096 ;
      RECT 0.492 344.400 249.528 344.496 ;
      RECT 0.492 346.800 249.528 346.896 ;
      RECT 0.492 349.200 249.528 349.296 ;
      RECT 0.492 351.600 249.528 351.696 ;
      RECT 0.492 354.000 249.528 354.096 ;
      RECT 0.492 356.400 249.528 356.496 ;
      RECT 0.492 358.800 249.528 358.896 ;
      RECT 0.492 361.200 249.528 361.296 ;
      RECT 0.492 363.600 249.528 363.696 ;
      RECT 0.492 366.000 249.528 366.096 ;
      RECT 0.492 368.400 249.528 368.496 ;
      RECT 0.492 370.800 249.528 370.896 ;
      RECT 0.492 373.200 249.528 373.296 ;
      RECT 0.492 375.600 249.528 375.696 ;
      RECT 0.492 378.000 249.528 378.096 ;
      RECT 0.492 380.400 249.528 380.496 ;
      RECT 0.492 382.800 249.528 382.896 ;
      RECT 0.492 385.200 249.528 385.296 ;
      RECT 0.492 387.600 249.528 387.696 ;
      RECT 0.492 390.000 249.528 390.096 ;
      RECT 0.492 392.400 249.528 392.496 ;
      RECT 0.492 394.800 249.528 394.896 ;
      RECT 0.492 397.200 249.528 397.296 ;
      RECT 0.492 399.600 249.528 399.696 ;
      RECT 0.492 402.000 249.528 402.096 ;
      RECT 0.492 404.400 249.528 404.496 ;
      RECT 0.492 406.800 249.528 406.896 ;
      RECT 0.492 409.200 249.528 409.296 ;
      RECT 0.492 411.600 249.528 411.696 ;
      RECT 0.492 414.000 249.528 414.096 ;
      RECT 0.492 416.400 249.528 416.496 ;
      RECT 0.492 418.800 249.528 418.896 ;
      RECT 0.492 421.200 249.528 421.296 ;
      RECT 0.492 423.600 249.528 423.696 ;
      RECT 0.492 426.000 249.528 426.096 ;
      RECT 0.492 428.400 249.528 428.496 ;
      RECT 0.492 430.800 249.528 430.896 ;
      RECT 0.492 433.200 249.528 433.296 ;
      RECT 0.492 435.600 249.528 435.696 ;
      RECT 0.492 438.000 249.528 438.096 ;
      RECT 0.492 440.400 249.528 440.496 ;
      RECT 0.492 442.800 249.528 442.896 ;
      RECT 0.492 445.200 249.528 445.296 ;
      RECT 0.492 447.600 249.528 447.696 ;
      RECT 0.492 450.000 249.528 450.096 ;
      RECT 0.492 452.400 249.528 452.496 ;
      RECT 0.492 454.800 249.528 454.896 ;
      RECT 0.492 457.200 249.528 457.296 ;
      RECT 0.492 459.600 249.528 459.696 ;
      RECT 0.492 462.000 249.528 462.096 ;
      RECT 0.492 464.400 249.528 464.496 ;
      RECT 0.492 466.800 249.528 466.896 ;
      RECT 0.492 469.200 249.528 469.296 ;
      RECT 0.492 471.600 249.528 471.696 ;
      RECT 0.492 474.000 249.528 474.096 ;
      RECT 0.492 476.400 249.528 476.496 ;
      RECT 0.492 478.800 249.528 478.896 ;
      RECT 0.492 481.200 249.528 481.296 ;
      RECT 0.492 483.600 249.528 483.696 ;
      RECT 0.492 486.000 249.528 486.096 ;
      RECT 0.492 488.400 249.528 488.496 ;
      RECT 0.492 490.800 249.528 490.896 ;
      RECT 0.492 493.200 249.528 493.296 ;
      RECT 0.492 495.600 249.528 495.696 ;
      RECT 0.492 498.000 249.528 498.096 ;
      RECT 0.492 500.400 249.528 500.496 ;
      RECT 0.492 502.800 249.528 502.896 ;
      RECT 0.492 505.200 249.528 505.296 ;
      RECT 0.492 507.600 249.528 507.696 ;
      RECT 0.492 510.000 249.528 510.096 ;
      RECT 0.492 512.400 249.528 512.496 ;
      RECT 0.492 514.800 249.528 514.896 ;
      RECT 0.492 517.200 249.528 517.296 ;
      RECT 0.492 519.600 249.528 519.696 ;
      RECT 0.492 522.000 249.528 522.096 ;
      RECT 0.492 524.400 249.528 524.496 ;
      RECT 0.492 526.800 249.528 526.896 ;
      RECT 0.492 529.200 249.528 529.296 ;
      RECT 0.492 531.600 249.528 531.696 ;
      RECT 0.492 534.000 249.528 534.096 ;
      RECT 0.492 536.400 249.528 536.496 ;
      RECT 0.492 538.800 249.528 538.896 ;
      RECT 0.492 541.200 249.528 541.296 ;
      RECT 0.492 543.600 249.528 543.696 ;
      RECT 0.492 546.000 249.528 546.096 ;
      RECT 0.492 548.400 249.528 548.496 ;
      RECT 0.492 550.800 249.528 550.896 ;
      RECT 0.492 553.200 249.528 553.296 ;
      RECT 0.492 555.600 249.528 555.696 ;
      RECT 0.492 558.000 249.528 558.096 ;
      RECT 0.492 560.400 249.528 560.496 ;
      RECT 0.492 562.800 249.528 562.896 ;
      RECT 0.492 565.200 249.528 565.296 ;
      RECT 0.492 567.600 249.528 567.696 ;
      RECT 0.492 570.000 249.528 570.096 ;
      RECT 0.492 572.400 249.528 572.496 ;
      RECT 0.492 574.800 249.528 574.896 ;
      RECT 0.492 577.200 249.528 577.296 ;
      RECT 0.492 579.600 249.528 579.696 ;
      RECT 0.492 582.000 249.528 582.096 ;
      RECT 0.492 584.400 249.528 584.496 ;
      RECT 0.492 586.800 249.528 586.896 ;
      RECT 0.492 589.200 249.528 589.296 ;
      RECT 0.492 591.600 249.528 591.696 ;
      RECT 0.492 594.000 249.528 594.096 ;
      RECT 0.492 596.400 249.528 596.496 ;
      RECT 0.492 598.800 249.528 598.896 ;
      RECT 0.492 601.200 249.528 601.296 ;
      RECT 0.492 603.600 249.528 603.696 ;
      RECT 0.492 606.000 249.528 606.096 ;
      RECT 0.492 608.400 249.528 608.496 ;
      RECT 0.492 610.800 249.528 610.896 ;
      RECT 0.492 613.200 249.528 613.296 ;
      RECT 0.492 615.600 249.528 615.696 ;
      RECT 0.492 618.000 249.528 618.096 ;
      RECT 0.492 620.400 249.528 620.496 ;
      RECT 0.492 622.800 249.528 622.896 ;
      RECT 0.492 625.200 249.528 625.296 ;
      RECT 0.492 627.600 249.528 627.696 ;
      RECT 0.492 630.000 249.528 630.096 ;
      RECT 0.492 632.400 249.528 632.496 ;
      RECT 0.492 634.800 249.528 634.896 ;
      RECT 0.492 637.200 249.528 637.296 ;
      RECT 0.492 639.600 249.528 639.696 ;
      RECT 0.492 642.000 249.528 642.096 ;
      RECT 0.492 644.400 249.528 644.496 ;
      RECT 0.492 646.800 249.528 646.896 ;
      RECT 0.492 649.200 249.528 649.296 ;
      RECT 0.492 651.600 249.528 651.696 ;
      RECT 0.492 654.000 249.528 654.096 ;
      RECT 0.492 656.400 249.528 656.496 ;
      RECT 0.492 658.800 249.528 658.896 ;
      RECT 0.492 661.200 249.528 661.296 ;
      RECT 0.492 663.600 249.528 663.696 ;
      RECT 0.492 666.000 249.528 666.096 ;
      RECT 0.492 668.400 249.528 668.496 ;
      RECT 0.492 670.800 249.528 670.896 ;
      RECT 0.492 673.200 249.528 673.296 ;
      RECT 0.492 675.600 249.528 675.696 ;
      RECT 0.492 678.000 249.528 678.096 ;
      RECT 0.492 680.400 249.528 680.496 ;
      RECT 0.492 682.800 249.528 682.896 ;
      RECT 0.492 685.200 249.528 685.296 ;
      RECT 0.492 687.600 249.528 687.696 ;
      RECT 0.492 690.000 249.528 690.096 ;
      RECT 0.492 692.400 249.528 692.496 ;
      RECT 0.492 694.800 249.528 694.896 ;
      RECT 0.492 697.200 249.528 697.296 ;
      RECT 0.492 699.600 249.528 699.696 ;
      RECT 0.492 702.000 249.528 702.096 ;
      RECT 0.492 704.400 249.528 704.496 ;
      RECT 0.492 706.800 249.528 706.896 ;
      RECT 0.492 709.200 249.528 709.296 ;
      RECT 0.492 711.600 249.528 711.696 ;
      RECT 0.492 714.000 249.528 714.096 ;
      RECT 0.492 716.400 249.528 716.496 ;
      RECT 0.492 718.800 249.528 718.896 ;
      RECT 0.492 721.200 249.528 721.296 ;
      RECT 0.492 723.600 249.528 723.696 ;
      RECT 0.492 726.000 249.528 726.096 ;
      RECT 0.492 728.400 249.528 728.496 ;
      RECT 0.492 730.800 249.528 730.896 ;
      RECT 0.492 733.200 249.528 733.296 ;
      RECT 0.492 735.600 249.528 735.696 ;
      RECT 0.492 738.000 249.528 738.096 ;
      RECT 0.492 740.400 249.528 740.496 ;
      RECT 0.492 742.800 249.528 742.896 ;
      RECT 0.492 745.200 249.528 745.296 ;
      RECT 0.492 747.600 249.528 747.696 ;
      RECT 0.492 750.000 249.528 750.096 ;
      RECT 0.492 752.400 249.528 752.496 ;
      RECT 0.492 754.800 249.528 754.896 ;
      RECT 0.492 757.200 249.528 757.296 ;
      RECT 0.492 759.600 249.528 759.696 ;
      RECT 0.492 762.000 249.528 762.096 ;
      RECT 0.492 764.400 249.528 764.496 ;
      RECT 0.492 766.800 249.528 766.896 ;
      RECT 0.492 769.200 249.528 769.296 ;
      RECT 0.492 771.600 249.528 771.696 ;
      RECT 0.492 774.000 249.528 774.096 ;
      RECT 0.492 776.400 249.528 776.496 ;
      RECT 0.492 778.800 249.528 778.896 ;
      RECT 0.492 781.200 249.528 781.296 ;
      RECT 0.492 783.600 249.528 783.696 ;
      RECT 0.492 786.000 249.528 786.096 ;
      RECT 0.492 788.400 249.528 788.496 ;
      RECT 0.492 790.800 249.528 790.896 ;
      RECT 0.492 793.200 249.528 793.296 ;
      RECT 0.492 795.600 249.528 795.696 ;
      RECT 0.492 798.000 249.528 798.096 ;
      RECT 0.492 800.400 249.528 800.496 ;
      RECT 0.492 802.800 249.528 802.896 ;
      RECT 0.492 805.200 249.528 805.296 ;
      RECT 0.492 807.600 249.528 807.696 ;
      RECT 0.492 810.000 249.528 810.096 ;
      RECT 0.492 812.400 249.528 812.496 ;
      RECT 0.492 814.800 249.528 814.896 ;
      RECT 0.492 817.200 249.528 817.296 ;
      RECT 0.492 819.600 249.528 819.696 ;
      RECT 0.492 822.000 249.528 822.096 ;
      RECT 0.492 824.400 249.528 824.496 ;
      RECT 0.492 826.800 249.528 826.896 ;
      RECT 0.492 829.200 249.528 829.296 ;
      RECT 0.492 831.600 249.528 831.696 ;
      RECT 0.492 834.000 249.528 834.096 ;
      RECT 0.492 836.400 249.528 836.496 ;
      RECT 0.492 838.800 249.528 838.896 ;
      RECT 0.492 841.200 249.528 841.296 ;
      RECT 0.492 843.600 249.528 843.696 ;
      RECT 0.492 846.000 249.528 846.096 ;
      RECT 0.492 848.400 249.528 848.496 ;
      RECT 0.492 850.800 249.528 850.896 ;
      RECT 0.492 853.200 249.528 853.296 ;
      RECT 0.492 855.600 249.528 855.696 ;
      RECT 0.492 858.000 249.528 858.096 ;
      RECT 0.492 860.400 249.528 860.496 ;
      RECT 0.492 862.800 249.528 862.896 ;
      RECT 0.492 865.200 249.528 865.296 ;
      RECT 0.492 867.600 249.528 867.696 ;
      RECT 0.492 870.000 249.528 870.096 ;
      RECT 0.492 872.400 249.528 872.496 ;
      RECT 0.492 874.800 249.528 874.896 ;
      RECT 0.492 877.200 249.528 877.296 ;
      RECT 0.492 879.600 249.528 879.696 ;
      RECT 0.492 882.000 249.528 882.096 ;
      RECT 0.492 884.400 249.528 884.496 ;
      RECT 0.492 886.800 249.528 886.896 ;
      RECT 0.492 889.200 249.528 889.296 ;
      RECT 0.492 891.600 249.528 891.696 ;
      RECT 0.492 894.000 249.528 894.096 ;
      RECT 0.492 896.400 249.528 896.496 ;
      RECT 0.492 898.800 249.528 898.896 ;
      RECT 0.492 901.200 249.528 901.296 ;
      RECT 0.492 903.600 249.528 903.696 ;
      RECT 0.492 906.000 249.528 906.096 ;
      RECT 0.492 908.400 249.528 908.496 ;
      RECT 0.492 910.800 249.528 910.896 ;
      RECT 0.492 913.200 249.528 913.296 ;
      RECT 0.492 915.600 249.528 915.696 ;
      RECT 0.492 918.000 249.528 918.096 ;
      RECT 0.492 920.400 249.528 920.496 ;
      RECT 0.492 922.800 249.528 922.896 ;
      RECT 0.492 925.200 249.528 925.296 ;
      RECT 0.492 927.600 249.528 927.696 ;
      RECT 0.492 930.000 249.528 930.096 ;
      RECT 0.492 932.400 249.528 932.496 ;
      RECT 0.492 934.800 249.528 934.896 ;
      RECT 0.492 937.200 249.528 937.296 ;
      RECT 0.492 939.600 249.528 939.696 ;
      RECT 0.492 942.000 249.528 942.096 ;
      RECT 0.492 944.400 249.528 944.496 ;
      RECT 0.492 946.800 249.528 946.896 ;
      RECT 0.492 949.200 249.528 949.296 ;
      RECT 0.492 951.600 249.528 951.696 ;
      RECT 0.492 954.000 249.528 954.096 ;
      RECT 0.492 956.400 249.528 956.496 ;
      RECT 0.492 958.800 249.528 958.896 ;
      RECT 0.492 961.200 249.528 961.296 ;
      RECT 0.492 963.600 249.528 963.696 ;
      RECT 0.492 966.000 249.528 966.096 ;
      RECT 0.492 968.400 249.528 968.496 ;
      RECT 0.492 970.800 249.528 970.896 ;
      RECT 0.492 973.200 249.528 973.296 ;
      RECT 0.492 975.600 249.528 975.696 ;
      RECT 0.492 978.000 249.528 978.096 ;
      RECT 0.492 980.400 249.528 980.496 ;
      RECT 0.492 982.800 249.528 982.896 ;
      RECT 0.492 985.200 249.528 985.296 ;
      RECT 0.492 987.600 249.528 987.696 ;
      RECT 0.492 990.000 249.528 990.096 ;
      RECT 0.492 992.400 249.528 992.496 ;
      RECT 0.492 994.800 249.528 994.896 ;
      RECT 0.492 997.200 249.528 997.296 ;
      RECT 0.492 999.600 249.528 999.696 ;
      RECT 0.492 1002.000 249.528 1002.096 ;
      RECT 0.492 1004.400 249.528 1004.496 ;
      RECT 0.492 1006.800 249.528 1006.896 ;
      RECT 0.492 1009.200 249.528 1009.296 ;
      RECT 0.492 1011.600 249.528 1011.696 ;
      RECT 0.492 1014.000 249.528 1014.096 ;
      RECT 0.492 1016.400 249.528 1016.496 ;
      RECT 0.492 1018.800 249.528 1018.896 ;
      RECT 0.492 1021.200 249.528 1021.296 ;
      RECT 0.492 1023.600 249.528 1023.696 ;
      RECT 0.492 1026.000 249.528 1026.096 ;
      RECT 0.492 1028.400 249.528 1028.496 ;
      RECT 0.492 1030.800 249.528 1030.896 ;
      RECT 0.492 1033.200 249.528 1033.296 ;
      RECT 0.492 1035.600 249.528 1035.696 ;
      RECT 0.492 1038.000 249.528 1038.096 ;
      RECT 0.492 1040.400 249.528 1040.496 ;
      RECT 0.492 1042.800 249.528 1042.896 ;
      RECT 0.492 1045.200 249.528 1045.296 ;
      RECT 0.492 1047.600 249.528 1047.696 ;
      RECT 0.492 1050.000 249.528 1050.096 ;
      RECT 0.492 1052.400 249.528 1052.496 ;
      RECT 0.492 1054.800 249.528 1054.896 ;
      RECT 0.492 1057.200 249.528 1057.296 ;
      RECT 0.492 1059.600 249.528 1059.696 ;
      RECT 0.492 1062.000 249.528 1062.096 ;
      RECT 0.492 1064.400 249.528 1064.496 ;
      RECT 0.492 1066.800 249.528 1066.896 ;
      RECT 0.492 1069.200 249.528 1069.296 ;
      RECT 0.492 1071.600 249.528 1071.696 ;
      RECT 0.492 1074.000 249.528 1074.096 ;
      RECT 0.492 1076.400 249.528 1076.496 ;
      RECT 0.492 1078.800 249.528 1078.896 ;
      RECT 0.492 1081.200 249.528 1081.296 ;
      RECT 0.492 1083.600 249.528 1083.696 ;
      RECT 0.492 1086.000 249.528 1086.096 ;
      RECT 0.492 1088.400 249.528 1088.496 ;
      RECT 0.492 1090.800 249.528 1090.896 ;
      RECT 0.492 1093.200 249.528 1093.296 ;
      RECT 0.492 1095.600 249.528 1095.696 ;
      RECT 0.492 1098.000 249.528 1098.096 ;
      RECT 0.492 1100.400 249.528 1100.496 ;
      RECT 0.492 1102.800 249.528 1102.896 ;
      RECT 0.492 1105.200 249.528 1105.296 ;
      RECT 0.492 1107.600 249.528 1107.696 ;
      RECT 0.492 1110.000 249.528 1110.096 ;
      RECT 0.492 1112.400 249.528 1112.496 ;
      RECT 0.492 1114.800 249.528 1114.896 ;
      RECT 0.492 1117.200 249.528 1117.296 ;
      RECT 0.492 1119.600 249.528 1119.696 ;
      RECT 0.492 1122.000 249.528 1122.096 ;
      RECT 0.492 1124.400 249.528 1124.496 ;
      RECT 0.492 1126.800 249.528 1126.896 ;
      RECT 0.492 1129.200 249.528 1129.296 ;
      RECT 0.492 1131.600 249.528 1131.696 ;
      RECT 0.492 1134.000 249.528 1134.096 ;
      RECT 0.492 1136.400 249.528 1136.496 ;
      RECT 0.492 1138.800 249.528 1138.896 ;
      RECT 0.492 1141.200 249.528 1141.296 ;
      RECT 0.492 1143.600 249.528 1143.696 ;
      RECT 0.492 1146.000 249.528 1146.096 ;
      RECT 0.492 1148.400 249.528 1148.496 ;
      RECT 0.492 1150.800 249.528 1150.896 ;
      RECT 0.492 1153.200 249.528 1153.296 ;
      RECT 0.492 1155.600 249.528 1155.696 ;
      RECT 0.492 1158.000 249.528 1158.096 ;
      RECT 0.492 1160.400 249.528 1160.496 ;
      RECT 0.492 1162.800 249.528 1162.896 ;
      RECT 0.492 1165.200 249.528 1165.296 ;
      RECT 0.492 1167.600 249.528 1167.696 ;
      RECT 0.492 1170.000 249.528 1170.096 ;
      RECT 0.492 1172.400 249.528 1172.496 ;
      RECT 0.492 1174.800 249.528 1174.896 ;
      RECT 0.492 1177.200 249.528 1177.296 ;
      RECT 0.492 1179.600 249.528 1179.696 ;
      RECT 0.492 1182.000 249.528 1182.096 ;
      RECT 0.492 1184.400 249.528 1184.496 ;
      RECT 0.492 1186.800 249.528 1186.896 ;
      RECT 0.492 1189.200 249.528 1189.296 ;
      RECT 0.492 1191.600 249.528 1191.696 ;
      RECT 0.492 1194.000 249.528 1194.096 ;
      RECT 0.492 1196.400 249.528 1196.496 ;
      RECT 0.492 1198.800 249.528 1198.896 ;
      RECT 0.492 1201.200 249.528 1201.296 ;
      RECT 0.492 1203.600 249.528 1203.696 ;
      RECT 0.492 1206.000 249.528 1206.096 ;
      RECT 0.492 1208.400 249.528 1208.496 ;
      RECT 0.492 1210.800 249.528 1210.896 ;
      RECT 0.492 1213.200 249.528 1213.296 ;
      RECT 0.492 1215.600 249.528 1215.696 ;
      RECT 0.492 1218.000 249.528 1218.096 ;
      RECT 0.492 1220.400 249.528 1220.496 ;
      RECT 0.492 1222.800 249.528 1222.896 ;
      RECT 0.492 1225.200 249.528 1225.296 ;
      RECT 0.492 1227.600 249.528 1227.696 ;
      RECT 0.492 1230.000 249.528 1230.096 ;
      RECT 0.492 1232.400 249.528 1232.496 ;
      RECT 0.492 1234.800 249.528 1234.896 ;
      RECT 0.492 1237.200 249.528 1237.296 ;
      RECT 0.492 1239.600 249.528 1239.696 ;
      RECT 0.492 1242.000 249.528 1242.096 ;
      RECT 0.492 1244.400 249.528 1244.496 ;
      RECT 0.492 1246.800 249.528 1246.896 ;
      RECT 0.492 1249.200 249.528 1249.296 ;
      RECT 0.492 1251.600 249.528 1251.696 ;
      RECT 0.492 1254.000 249.528 1254.096 ;
      RECT 0.492 1256.400 249.528 1256.496 ;
      RECT 0.492 1258.800 249.528 1258.896 ;
      RECT 0.492 1261.200 249.528 1261.296 ;
      RECT 0.492 1263.600 249.528 1263.696 ;
      RECT 0.492 1266.000 249.528 1266.096 ;
      RECT 0.492 1268.400 249.528 1268.496 ;
      RECT 0.492 1270.800 249.528 1270.896 ;
      RECT 0.492 1273.200 249.528 1273.296 ;
      RECT 0.492 1275.600 249.528 1275.696 ;
      RECT 0.492 1278.000 249.528 1278.096 ;
      RECT 0.492 1280.400 249.528 1280.496 ;
      RECT 0.492 1282.800 249.528 1282.896 ;
      RECT 0.492 1285.200 249.528 1285.296 ;
      RECT 0.492 1287.600 249.528 1287.696 ;
      RECT 0.492 1290.000 249.528 1290.096 ;
      RECT 0.492 1292.400 249.528 1292.496 ;
      RECT 0.492 1294.800 249.528 1294.896 ;
      RECT 0.492 1297.200 249.528 1297.296 ;
      RECT 0.492 1299.600 249.528 1299.696 ;
      RECT 0.492 1302.000 249.528 1302.096 ;
      RECT 0.492 1304.400 249.528 1304.496 ;
      RECT 0.492 1306.800 249.528 1306.896 ;
      RECT 0.492 1309.200 249.528 1309.296 ;
      RECT 0.492 1311.600 249.528 1311.696 ;
      RECT 0.492 1314.000 249.528 1314.096 ;
      RECT 0.492 1316.400 249.528 1316.496 ;
      RECT 0.492 1318.800 249.528 1318.896 ;
      RECT 0.492 1321.200 249.528 1321.296 ;
      RECT 0.492 1323.600 249.528 1323.696 ;
      RECT 0.492 1326.000 249.528 1326.096 ;
      RECT 0.492 1328.400 249.528 1328.496 ;
      RECT 0.492 1330.800 249.528 1330.896 ;
      RECT 0.492 1333.200 249.528 1333.296 ;
      RECT 0.492 1335.600 249.528 1335.696 ;
      RECT 0.492 1338.000 249.528 1338.096 ;
      RECT 0.492 1340.400 249.528 1340.496 ;
      RECT 0.492 1342.800 249.528 1342.896 ;
      RECT 0.492 1345.200 249.528 1345.296 ;
      RECT 0.492 1347.600 249.528 1347.696 ;
      RECT 0.492 1350.000 249.528 1350.096 ;
      RECT 0.492 1352.400 249.528 1352.496 ;
      RECT 0.492 1354.800 249.528 1354.896 ;
      RECT 0.492 1357.200 249.528 1357.296 ;
      RECT 0.492 1359.600 249.528 1359.696 ;
      RECT 0.492 1362.000 249.528 1362.096 ;
      RECT 0.492 1364.400 249.528 1364.496 ;
      RECT 0.492 1366.800 249.528 1366.896 ;
      RECT 0.492 1369.200 249.528 1369.296 ;
      RECT 0.492 1371.600 249.528 1371.696 ;
      RECT 0.492 1374.000 249.528 1374.096 ;
      RECT 0.492 1376.400 249.528 1376.496 ;
      RECT 0.492 1378.800 249.528 1378.896 ;
      RECT 0.492 1381.200 249.528 1381.296 ;
      RECT 0.492 1383.600 249.528 1383.696 ;
      RECT 0.492 1386.000 249.528 1386.096 ;
      RECT 0.492 1388.400 249.528 1388.496 ;
      RECT 0.492 1390.800 249.528 1390.896 ;
      RECT 0.492 1393.200 249.528 1393.296 ;
      RECT 0.492 1395.600 249.528 1395.696 ;
      RECT 0.492 1398.000 249.528 1398.096 ;
      RECT 0.492 1400.400 249.528 1400.496 ;
      RECT 0.492 1402.800 249.528 1402.896 ;
      RECT 0.492 1405.200 249.528 1405.296 ;
      RECT 0.492 1407.600 249.528 1407.696 ;
      RECT 0.492 1410.000 249.528 1410.096 ;
      RECT 0.492 1412.400 249.528 1412.496 ;
      RECT 0.492 1414.800 249.528 1414.896 ;
      RECT 0.492 1417.200 249.528 1417.296 ;
      RECT 0.492 1419.600 249.528 1419.696 ;
      RECT 0.492 1422.000 249.528 1422.096 ;
      RECT 0.492 1424.400 249.528 1424.496 ;
      RECT 0.492 1426.800 249.528 1426.896 ;
      RECT 0.492 1429.200 249.528 1429.296 ;
      RECT 0.492 1431.600 249.528 1431.696 ;
      RECT 0.492 1434.000 249.528 1434.096 ;
      RECT 0.492 1436.400 249.528 1436.496 ;
      RECT 0.492 1438.800 249.528 1438.896 ;
      RECT 0.492 1441.200 249.528 1441.296 ;
      RECT 0.492 1443.600 249.528 1443.696 ;
      RECT 0.492 1446.000 249.528 1446.096 ;
      RECT 0.492 1448.400 249.528 1448.496 ;
      RECT 0.492 1450.800 249.528 1450.896 ;
      RECT 0.492 1453.200 249.528 1453.296 ;
      RECT 0.492 1455.600 249.528 1455.696 ;
      RECT 0.492 1458.000 249.528 1458.096 ;
      RECT 0.492 1460.400 249.528 1460.496 ;
      RECT 0.492 1462.800 249.528 1462.896 ;
      RECT 0.492 1465.200 249.528 1465.296 ;
      RECT 0.492 1467.600 249.528 1467.696 ;
      RECT 0.492 1470.000 249.528 1470.096 ;
      RECT 0.492 1472.400 249.528 1472.496 ;
      RECT 0.492 1474.800 249.528 1474.896 ;
      RECT 0.492 1477.200 249.528 1477.296 ;
      RECT 0.492 1479.600 249.528 1479.696 ;
      RECT 0.492 1482.000 249.528 1482.096 ;
      RECT 0.492 1484.400 249.528 1484.496 ;
      RECT 0.492 1486.800 249.528 1486.896 ;
      RECT 0.492 1489.200 249.528 1489.296 ;
      RECT 0.492 1491.600 249.528 1491.696 ;
      RECT 0.492 1494.000 249.528 1494.096 ;
      RECT 0.492 1496.400 249.528 1496.496 ;
      RECT 0.492 1498.800 249.528 1498.896 ;
      RECT 0.492 1501.200 249.528 1501.296 ;
      RECT 0.492 1503.600 249.528 1503.696 ;
      RECT 0.492 1506.000 249.528 1506.096 ;
      RECT 0.492 1508.400 249.528 1508.496 ;
      RECT 0.492 1510.800 249.528 1510.896 ;
      RECT 0.492 1513.200 249.528 1513.296 ;
      RECT 0.492 1515.600 249.528 1515.696 ;
      RECT 0.492 1518.000 249.528 1518.096 ;
      RECT 0.492 1520.400 249.528 1520.496 ;
      RECT 0.492 1522.800 249.528 1522.896 ;
      RECT 0.492 1525.200 249.528 1525.296 ;
      RECT 0.492 1527.600 249.528 1527.696 ;
      RECT 0.492 1530.000 249.528 1530.096 ;
      RECT 0.492 1532.400 249.528 1532.496 ;
      RECT 0.492 1534.800 249.528 1534.896 ;
      RECT 0.492 1537.200 249.528 1537.296 ;
      RECT 0.492 1539.600 249.528 1539.696 ;
      RECT 0.492 1542.000 249.528 1542.096 ;
      RECT 0.492 1544.400 249.528 1544.496 ;
      RECT 0.492 1546.800 249.528 1546.896 ;
      RECT 0.492 1549.200 249.528 1549.296 ;
      RECT 0.492 1551.600 249.528 1551.696 ;
      RECT 0.492 1554.000 249.528 1554.096 ;
      RECT 0.492 1556.400 249.528 1556.496 ;
      RECT 0.492 1558.800 249.528 1558.896 ;
      RECT 0.492 1561.200 249.528 1561.296 ;
      RECT 0.492 1563.600 249.528 1563.696 ;
      RECT 0.492 1566.000 249.528 1566.096 ;
      RECT 0.492 1568.400 249.528 1568.496 ;
      RECT 0.492 1570.800 249.528 1570.896 ;
      RECT 0.492 1573.200 249.528 1573.296 ;
      RECT 0.492 1575.600 249.528 1575.696 ;
      RECT 0.492 1578.000 249.528 1578.096 ;
      RECT 0.492 1580.400 249.528 1580.496 ;
      RECT 0.492 1582.800 249.528 1582.896 ;
      RECT 0.492 1585.200 249.528 1585.296 ;
      RECT 0.492 1587.600 249.528 1587.696 ;
      RECT 0.492 1590.000 249.528 1590.096 ;
      RECT 0.492 1592.400 249.528 1592.496 ;
      RECT 0.492 1594.800 249.528 1594.896 ;
      RECT 0.492 1597.200 249.528 1597.296 ;
      RECT 0.492 1599.600 249.528 1599.696 ;
      RECT 0.492 1602.000 249.528 1602.096 ;
      RECT 0.492 1604.400 249.528 1604.496 ;
      RECT 0.492 1606.800 249.528 1606.896 ;
      RECT 0.492 1609.200 249.528 1609.296 ;
      RECT 0.492 1611.600 249.528 1611.696 ;
      RECT 0.492 1614.000 249.528 1614.096 ;
      RECT 0.492 1616.400 249.528 1616.496 ;
      RECT 0.492 1618.800 249.528 1618.896 ;
      RECT 0.492 1621.200 249.528 1621.296 ;
      RECT 0.492 1623.600 249.528 1623.696 ;
      RECT 0.492 1626.000 249.528 1626.096 ;
      RECT 0.492 1628.400 249.528 1628.496 ;
      RECT 0.492 1630.800 249.528 1630.896 ;
      RECT 0.492 1633.200 249.528 1633.296 ;
      RECT 0.492 1635.600 249.528 1635.696 ;
      RECT 0.492 1638.000 249.528 1638.096 ;
      RECT 0.492 1640.400 249.528 1640.496 ;
      RECT 0.492 1642.800 249.528 1642.896 ;
      RECT 0.492 1645.200 249.528 1645.296 ;
      RECT 0.492 1647.600 249.528 1647.696 ;
      RECT 0.492 1650.000 249.528 1650.096 ;
      RECT 0.492 1652.400 249.528 1652.496 ;
      RECT 0.492 1654.800 249.528 1654.896 ;
      RECT 0.492 1657.200 249.528 1657.296 ;
      RECT 0.492 1659.600 249.528 1659.696 ;
      RECT 0.492 1662.000 249.528 1662.096 ;
      RECT 0.492 1664.400 249.528 1664.496 ;
      RECT 0.492 1666.800 249.528 1666.896 ;
      RECT 0.492 1669.200 249.528 1669.296 ;
      RECT 0.492 1671.600 249.528 1671.696 ;
      RECT 0.492 1674.000 249.528 1674.096 ;
      RECT 0.492 1676.400 249.528 1676.496 ;
      RECT 0.492 1678.800 249.528 1678.896 ;
      RECT 0.492 1681.200 249.528 1681.296 ;
      RECT 0.492 1683.600 249.528 1683.696 ;
      RECT 0.492 1686.000 249.528 1686.096 ;
      RECT 0.492 1688.400 249.528 1688.496 ;
      RECT 0.492 1690.800 249.528 1690.896 ;
      RECT 0.492 1693.200 249.528 1693.296 ;
      RECT 0.492 1695.600 249.528 1695.696 ;
      RECT 0.492 1698.000 249.528 1698.096 ;
      RECT 0.492 1700.400 249.528 1700.496 ;
      RECT 0.492 1702.800 249.528 1702.896 ;
      RECT 0.492 1705.200 249.528 1705.296 ;
      RECT 0.492 1707.600 249.528 1707.696 ;
      RECT 0.492 1710.000 249.528 1710.096 ;
      RECT 0.492 1712.400 249.528 1712.496 ;
      RECT 0.492 1714.800 249.528 1714.896 ;
      RECT 0.492 1717.200 249.528 1717.296 ;
      RECT 0.492 1719.600 249.528 1719.696 ;
      RECT 0.492 1722.000 249.528 1722.096 ;
      RECT 0.492 1724.400 249.528 1724.496 ;
      RECT 0.492 1726.800 249.528 1726.896 ;
      RECT 0.492 1729.200 249.528 1729.296 ;
      RECT 0.492 1731.600 249.528 1731.696 ;
      RECT 0.492 1734.000 249.528 1734.096 ;
      RECT 0.492 1736.400 249.528 1736.496 ;
      RECT 0.492 1738.800 249.528 1738.896 ;
      RECT 0.492 1741.200 249.528 1741.296 ;
      RECT 0.492 1743.600 249.528 1743.696 ;
      RECT 0.492 1746.000 249.528 1746.096 ;
      RECT 0.492 1748.400 249.528 1748.496 ;
      RECT 0.492 1750.800 249.528 1750.896 ;
      RECT 0.492 1753.200 249.528 1753.296 ;
      RECT 0.492 1755.600 249.528 1755.696 ;
      RECT 0.492 1758.000 249.528 1758.096 ;
      RECT 0.492 1760.400 249.528 1760.496 ;
      RECT 0.492 1762.800 249.528 1762.896 ;
      RECT 0.492 1765.200 249.528 1765.296 ;
      RECT 0.492 1767.600 249.528 1767.696 ;
      RECT 0.492 1770.000 249.528 1770.096 ;
      RECT 0.492 1772.400 249.528 1772.496 ;
      RECT 0.492 1774.800 249.528 1774.896 ;
      RECT 0.492 1777.200 249.528 1777.296 ;
      RECT 0.492 1779.600 249.528 1779.696 ;
      RECT 0.492 1782.000 249.528 1782.096 ;
      RECT 0.492 1784.400 249.528 1784.496 ;
      RECT 0.492 1786.800 249.528 1786.896 ;
      RECT 0.492 1789.200 249.528 1789.296 ;
      RECT 0.492 1791.600 249.528 1791.696 ;
      RECT 0.492 1794.000 249.528 1794.096 ;
      RECT 0.492 1796.400 249.528 1796.496 ;
      RECT 0.492 1798.800 249.528 1798.896 ;
      RECT 0.492 1801.200 249.528 1801.296 ;
      RECT 0.492 1803.600 249.528 1803.696 ;
      RECT 0.492 1806.000 249.528 1806.096 ;
      RECT 0.492 1808.400 249.528 1808.496 ;
      RECT 0.492 1810.800 249.528 1810.896 ;
      RECT 0.492 1813.200 249.528 1813.296 ;
      RECT 0.492 1815.600 249.528 1815.696 ;
      RECT 0.492 1818.000 249.528 1818.096 ;
      RECT 0.492 1820.400 249.528 1820.496 ;
      RECT 0.492 1822.800 249.528 1822.896 ;
      RECT 0.492 1825.200 249.528 1825.296 ;
      RECT 0.492 1827.600 249.528 1827.696 ;
      RECT 0.492 1830.000 249.528 1830.096 ;
      RECT 0.492 1832.400 249.528 1832.496 ;
      RECT 0.492 1834.800 249.528 1834.896 ;
      RECT 0.492 1837.200 249.528 1837.296 ;
      RECT 0.492 1839.600 249.528 1839.696 ;
      RECT 0.492 1842.000 249.528 1842.096 ;
      RECT 0.492 1844.400 249.528 1844.496 ;
      RECT 0.492 1846.800 249.528 1846.896 ;
      RECT 0.492 1849.200 249.528 1849.296 ;
      RECT 0.492 1851.600 249.528 1851.696 ;
      RECT 0.492 1854.000 249.528 1854.096 ;
      RECT 0.492 1856.400 249.528 1856.496 ;
      RECT 0.492 1858.800 249.528 1858.896 ;
      RECT 0.492 1861.200 249.528 1861.296 ;
      RECT 0.492 1863.600 249.528 1863.696 ;
      RECT 0.492 1866.000 249.528 1866.096 ;
      RECT 0.492 1868.400 249.528 1868.496 ;
      RECT 0.492 1870.800 249.528 1870.896 ;
      RECT 0.492 1873.200 249.528 1873.296 ;
      RECT 0.492 1875.600 249.528 1875.696 ;
      RECT 0.492 1878.000 249.528 1878.096 ;
      RECT 0.492 1880.400 249.528 1880.496 ;
      RECT 0.492 1882.800 249.528 1882.896 ;
      RECT 0.492 1885.200 249.528 1885.296 ;
      RECT 0.492 1887.600 249.528 1887.696 ;
      RECT 0.492 1890.000 249.528 1890.096 ;
      RECT 0.492 1892.400 249.528 1892.496 ;
      RECT 0.492 1894.800 249.528 1894.896 ;
      RECT 0.492 1897.200 249.528 1897.296 ;
      RECT 0.492 1899.600 249.528 1899.696 ;
      RECT 0.492 1902.000 249.528 1902.096 ;
      RECT 0.492 1904.400 249.528 1904.496 ;
      RECT 0.492 1906.800 249.528 1906.896 ;
      RECT 0.492 1909.200 249.528 1909.296 ;
      RECT 0.492 1911.600 249.528 1911.696 ;
      RECT 0.492 1914.000 249.528 1914.096 ;
      RECT 0.492 1916.400 249.528 1916.496 ;
      RECT 0.492 1918.800 249.528 1918.896 ;
      RECT 0.492 1921.200 249.528 1921.296 ;
      RECT 0.492 1923.600 249.528 1923.696 ;
      RECT 0.492 1926.000 249.528 1926.096 ;
      RECT 0.492 1928.400 249.528 1928.496 ;
      RECT 0.492 1930.800 249.528 1930.896 ;
      RECT 0.492 1933.200 249.528 1933.296 ;
      RECT 0.492 1935.600 249.528 1935.696 ;
      RECT 0.492 1938.000 249.528 1938.096 ;
      RECT 0.492 1940.400 249.528 1940.496 ;
      RECT 0.492 1942.800 249.528 1942.896 ;
      RECT 0.492 1945.200 249.528 1945.296 ;
      RECT 0.492 1947.600 249.528 1947.696 ;
      RECT 0.492 1950.000 249.528 1950.096 ;
      RECT 0.492 1952.400 249.528 1952.496 ;
      RECT 0.492 1954.800 249.528 1954.896 ;
      RECT 0.492 1957.200 249.528 1957.296 ;
      RECT 0.492 1959.600 249.528 1959.696 ;
      RECT 0.492 1962.000 249.528 1962.096 ;
      RECT 0.492 1964.400 249.528 1964.496 ;
      RECT 0.492 1966.800 249.528 1966.896 ;
      RECT 0.492 1969.200 249.528 1969.296 ;
      RECT 0.492 1971.600 249.528 1971.696 ;
      RECT 0.492 1974.000 249.528 1974.096 ;
      RECT 0.492 1976.400 249.528 1976.496 ;
      RECT 0.492 1978.800 249.528 1978.896 ;
      RECT 0.492 1981.200 249.528 1981.296 ;
      RECT 0.492 1983.600 249.528 1983.696 ;
      RECT 0.492 1986.000 249.528 1986.096 ;
      RECT 0.492 1988.400 249.528 1988.496 ;
      RECT 0.492 1990.800 249.528 1990.896 ;
      RECT 0.492 1993.200 249.528 1993.296 ;
      RECT 0.492 1995.600 249.528 1995.696 ;
      RECT 0.492 1998.000 249.528 1998.096 ;
      RECT 0.492 2000.400 249.528 2000.496 ;
      RECT 0.492 2002.800 249.528 2002.896 ;
      RECT 0.492 2005.200 249.528 2005.296 ;
      RECT 0.492 2007.600 249.528 2007.696 ;
      RECT 0.492 2010.000 249.528 2010.096 ;
      RECT 0.492 2012.400 249.528 2012.496 ;
      RECT 0.492 2014.800 249.528 2014.896 ;
      RECT 0.492 2017.200 249.528 2017.296 ;
      RECT 0.492 2019.600 249.528 2019.696 ;
      RECT 0.492 2022.000 249.528 2022.096 ;
      RECT 0.492 2024.400 249.528 2024.496 ;
      RECT 0.492 2026.800 249.528 2026.896 ;
      RECT 0.492 2029.200 249.528 2029.296 ;
      RECT 0.492 2031.600 249.528 2031.696 ;
      RECT 0.492 2034.000 249.528 2034.096 ;
      RECT 0.492 2036.400 249.528 2036.496 ;
      RECT 0.492 2038.800 249.528 2038.896 ;
      RECT 0.492 2041.200 249.528 2041.296 ;
      RECT 0.492 2043.600 249.528 2043.696 ;
      RECT 0.492 2046.000 249.528 2046.096 ;
      RECT 0.492 2048.400 249.528 2048.496 ;
      RECT 0.492 2050.800 249.528 2050.896 ;
      RECT 0.492 2053.200 249.528 2053.296 ;
      RECT 0.492 2055.600 249.528 2055.696 ;
      RECT 0.492 2058.000 249.528 2058.096 ;
      RECT 0.492 2060.400 249.528 2060.496 ;
      RECT 0.492 2062.800 249.528 2062.896 ;
      RECT 0.492 2065.200 249.528 2065.296 ;
      RECT 0.492 2067.600 249.528 2067.696 ;
      RECT 0.492 2070.000 249.528 2070.096 ;
      RECT 0.492 2072.400 249.528 2072.496 ;
      RECT 0.492 2074.800 249.528 2074.896 ;
      RECT 0.492 2077.200 249.528 2077.296 ;
      RECT 0.492 2079.600 249.528 2079.696 ;
      RECT 0.492 2082.000 249.528 2082.096 ;
      RECT 0.492 2084.400 249.528 2084.496 ;
      RECT 0.492 2086.800 249.528 2086.896 ;
      RECT 0.492 2089.200 249.528 2089.296 ;
      RECT 0.492 2091.600 249.528 2091.696 ;
      RECT 0.492 2094.000 249.528 2094.096 ;
      RECT 0.492 2096.400 249.528 2096.496 ;
      RECT 0.492 2098.800 249.528 2098.896 ;
      RECT 0.492 2101.200 249.528 2101.296 ;
      RECT 0.492 2103.600 249.528 2103.696 ;
      RECT 0.492 2106.000 249.528 2106.096 ;
      RECT 0.492 2108.400 249.528 2108.496 ;
      RECT 0.492 2110.800 249.528 2110.896 ;
      RECT 0.492 2113.200 249.528 2113.296 ;
      RECT 0.492 2115.600 249.528 2115.696 ;
      RECT 0.492 2118.000 249.528 2118.096 ;
      RECT 0.492 2120.400 249.528 2120.496 ;
      RECT 0.492 2122.800 249.528 2122.896 ;
      RECT 0.492 2125.200 249.528 2125.296 ;
      RECT 0.492 2127.600 249.528 2127.696 ;
      RECT 0.492 2130.000 249.528 2130.096 ;
      RECT 0.492 2132.400 249.528 2132.496 ;
      RECT 0.492 2134.800 249.528 2134.896 ;
      RECT 0.492 2137.200 249.528 2137.296 ;
      RECT 0.492 2139.600 249.528 2139.696 ;
      RECT 0.492 2142.000 249.528 2142.096 ;
      RECT 0.492 2144.400 249.528 2144.496 ;
      RECT 0.492 2146.800 249.528 2146.896 ;
      RECT 0.492 2149.200 249.528 2149.296 ;
      RECT 0.492 2151.600 249.528 2151.696 ;
      RECT 0.492 2154.000 249.528 2154.096 ;
      RECT 0.492 2156.400 249.528 2156.496 ;
      RECT 0.492 2158.800 249.528 2158.896 ;
      RECT 0.492 2161.200 249.528 2161.296 ;
      RECT 0.492 2163.600 249.528 2163.696 ;
      RECT 0.492 2166.000 249.528 2166.096 ;
      RECT 0.492 2168.400 249.528 2168.496 ;
      RECT 0.492 2170.800 249.528 2170.896 ;
      RECT 0.492 2173.200 249.528 2173.296 ;
      RECT 0.492 2175.600 249.528 2175.696 ;
      RECT 0.492 2178.000 249.528 2178.096 ;
      RECT 0.492 2180.400 249.528 2180.496 ;
      RECT 0.492 2182.800 249.528 2182.896 ;
      RECT 0.492 2185.200 249.528 2185.296 ;
      RECT 0.492 2187.600 249.528 2187.696 ;
      RECT 0.492 2190.000 249.528 2190.096 ;
      RECT 0.492 2192.400 249.528 2192.496 ;
      RECT 0.492 2194.800 249.528 2194.896 ;
      RECT 0.492 2197.200 249.528 2197.296 ;
      RECT 0.492 2199.600 249.528 2199.696 ;
      RECT 0.492 2202.000 249.528 2202.096 ;
      RECT 0.492 2204.400 249.528 2204.496 ;
      RECT 0.492 2206.800 249.528 2206.896 ;
      RECT 0.492 2209.200 249.528 2209.296 ;
      RECT 0.492 2211.600 249.528 2211.696 ;
      RECT 0.492 2214.000 249.528 2214.096 ;
      RECT 0.492 2216.400 249.528 2216.496 ;
      RECT 0.492 2218.800 249.528 2218.896 ;
      RECT 0.492 2221.200 249.528 2221.296 ;
      RECT 0.492 2223.600 249.528 2223.696 ;
      RECT 0.492 2226.000 249.528 2226.096 ;
      RECT 0.492 2228.400 249.528 2228.496 ;
      RECT 0.492 2230.800 249.528 2230.896 ;
      RECT 0.492 2233.200 249.528 2233.296 ;
      RECT 0.492 2235.600 249.528 2235.696 ;
      RECT 0.492 2238.000 249.528 2238.096 ;
      RECT 0.492 2240.400 249.528 2240.496 ;
      RECT 0.492 2242.800 249.528 2242.896 ;
      RECT 0.492 2245.200 249.528 2245.296 ;
      RECT 0.492 2247.600 249.528 2247.696 ;
    END
  END VSS
  PIN VDD
    DIRECTION INOUT ;
    USE POWER ;
    PORT
      LAYER M4 ;
      RECT 0.492 2.400 249.528 2.496 ;
      RECT 0.492 4.800 249.528 4.896 ;
      RECT 0.492 7.200 249.528 7.296 ;
      RECT 0.492 9.600 249.528 9.696 ;
      RECT 0.492 12.000 249.528 12.096 ;
      RECT 0.492 14.400 249.528 14.496 ;
      RECT 0.492 16.800 249.528 16.896 ;
      RECT 0.492 19.200 249.528 19.296 ;
      RECT 0.492 21.600 249.528 21.696 ;
      RECT 0.492 24.000 249.528 24.096 ;
      RECT 0.492 26.400 249.528 26.496 ;
      RECT 0.492 28.800 249.528 28.896 ;
      RECT 0.492 31.200 249.528 31.296 ;
      RECT 0.492 33.600 249.528 33.696 ;
      RECT 0.492 36.000 249.528 36.096 ;
      RECT 0.492 38.400 249.528 38.496 ;
      RECT 0.492 40.800 249.528 40.896 ;
      RECT 0.492 43.200 249.528 43.296 ;
      RECT 0.492 45.600 249.528 45.696 ;
      RECT 0.492 48.000 249.528 48.096 ;
      RECT 0.492 50.400 249.528 50.496 ;
      RECT 0.492 52.800 249.528 52.896 ;
      RECT 0.492 55.200 249.528 55.296 ;
      RECT 0.492 57.600 249.528 57.696 ;
      RECT 0.492 60.000 249.528 60.096 ;
      RECT 0.492 62.400 249.528 62.496 ;
      RECT 0.492 64.800 249.528 64.896 ;
      RECT 0.492 67.200 249.528 67.296 ;
      RECT 0.492 69.600 249.528 69.696 ;
      RECT 0.492 72.000 249.528 72.096 ;
      RECT 0.492 74.400 249.528 74.496 ;
      RECT 0.492 76.800 249.528 76.896 ;
      RECT 0.492 79.200 249.528 79.296 ;
      RECT 0.492 81.600 249.528 81.696 ;
      RECT 0.492 84.000 249.528 84.096 ;
      RECT 0.492 86.400 249.528 86.496 ;
      RECT 0.492 88.800 249.528 88.896 ;
      RECT 0.492 91.200 249.528 91.296 ;
      RECT 0.492 93.600 249.528 93.696 ;
      RECT 0.492 96.000 249.528 96.096 ;
      RECT 0.492 98.400 249.528 98.496 ;
      RECT 0.492 100.800 249.528 100.896 ;
      RECT 0.492 103.200 249.528 103.296 ;
      RECT 0.492 105.600 249.528 105.696 ;
      RECT 0.492 108.000 249.528 108.096 ;
      RECT 0.492 110.400 249.528 110.496 ;
      RECT 0.492 112.800 249.528 112.896 ;
      RECT 0.492 115.200 249.528 115.296 ;
      RECT 0.492 117.600 249.528 117.696 ;
      RECT 0.492 120.000 249.528 120.096 ;
      RECT 0.492 122.400 249.528 122.496 ;
      RECT 0.492 124.800 249.528 124.896 ;
      RECT 0.492 127.200 249.528 127.296 ;
      RECT 0.492 129.600 249.528 129.696 ;
      RECT 0.492 132.000 249.528 132.096 ;
      RECT 0.492 134.400 249.528 134.496 ;
      RECT 0.492 136.800 249.528 136.896 ;
      RECT 0.492 139.200 249.528 139.296 ;
      RECT 0.492 141.600 249.528 141.696 ;
      RECT 0.492 144.000 249.528 144.096 ;
      RECT 0.492 146.400 249.528 146.496 ;
      RECT 0.492 148.800 249.528 148.896 ;
      RECT 0.492 151.200 249.528 151.296 ;
      RECT 0.492 153.600 249.528 153.696 ;
      RECT 0.492 156.000 249.528 156.096 ;
      RECT 0.492 158.400 249.528 158.496 ;
      RECT 0.492 160.800 249.528 160.896 ;
      RECT 0.492 163.200 249.528 163.296 ;
      RECT 0.492 165.600 249.528 165.696 ;
      RECT 0.492 168.000 249.528 168.096 ;
      RECT 0.492 170.400 249.528 170.496 ;
      RECT 0.492 172.800 249.528 172.896 ;
      RECT 0.492 175.200 249.528 175.296 ;
      RECT 0.492 177.600 249.528 177.696 ;
      RECT 0.492 180.000 249.528 180.096 ;
      RECT 0.492 182.400 249.528 182.496 ;
      RECT 0.492 184.800 249.528 184.896 ;
      RECT 0.492 187.200 249.528 187.296 ;
      RECT 0.492 189.600 249.528 189.696 ;
      RECT 0.492 192.000 249.528 192.096 ;
      RECT 0.492 194.400 249.528 194.496 ;
      RECT 0.492 196.800 249.528 196.896 ;
      RECT 0.492 199.200 249.528 199.296 ;
      RECT 0.492 201.600 249.528 201.696 ;
      RECT 0.492 204.000 249.528 204.096 ;
      RECT 0.492 206.400 249.528 206.496 ;
      RECT 0.492 208.800 249.528 208.896 ;
      RECT 0.492 211.200 249.528 211.296 ;
      RECT 0.492 213.600 249.528 213.696 ;
      RECT 0.492 216.000 249.528 216.096 ;
      RECT 0.492 218.400 249.528 218.496 ;
      RECT 0.492 220.800 249.528 220.896 ;
      RECT 0.492 223.200 249.528 223.296 ;
      RECT 0.492 225.600 249.528 225.696 ;
      RECT 0.492 228.000 249.528 228.096 ;
      RECT 0.492 230.400 249.528 230.496 ;
      RECT 0.492 232.800 249.528 232.896 ;
      RECT 0.492 235.200 249.528 235.296 ;
      RECT 0.492 237.600 249.528 237.696 ;
      RECT 0.492 240.000 249.528 240.096 ;
      RECT 0.492 242.400 249.528 242.496 ;
      RECT 0.492 244.800 249.528 244.896 ;
      RECT 0.492 247.200 249.528 247.296 ;
      RECT 0.492 249.600 249.528 249.696 ;
      RECT 0.492 252.000 249.528 252.096 ;
      RECT 0.492 254.400 249.528 254.496 ;
      RECT 0.492 256.800 249.528 256.896 ;
      RECT 0.492 259.200 249.528 259.296 ;
      RECT 0.492 261.600 249.528 261.696 ;
      RECT 0.492 264.000 249.528 264.096 ;
      RECT 0.492 266.400 249.528 266.496 ;
      RECT 0.492 268.800 249.528 268.896 ;
      RECT 0.492 271.200 249.528 271.296 ;
      RECT 0.492 273.600 249.528 273.696 ;
      RECT 0.492 276.000 249.528 276.096 ;
      RECT 0.492 278.400 249.528 278.496 ;
      RECT 0.492 280.800 249.528 280.896 ;
      RECT 0.492 283.200 249.528 283.296 ;
      RECT 0.492 285.600 249.528 285.696 ;
      RECT 0.492 288.000 249.528 288.096 ;
      RECT 0.492 290.400 249.528 290.496 ;
      RECT 0.492 292.800 249.528 292.896 ;
      RECT 0.492 295.200 249.528 295.296 ;
      RECT 0.492 297.600 249.528 297.696 ;
      RECT 0.492 300.000 249.528 300.096 ;
      RECT 0.492 302.400 249.528 302.496 ;
      RECT 0.492 304.800 249.528 304.896 ;
      RECT 0.492 307.200 249.528 307.296 ;
      RECT 0.492 309.600 249.528 309.696 ;
      RECT 0.492 312.000 249.528 312.096 ;
      RECT 0.492 314.400 249.528 314.496 ;
      RECT 0.492 316.800 249.528 316.896 ;
      RECT 0.492 319.200 249.528 319.296 ;
      RECT 0.492 321.600 249.528 321.696 ;
      RECT 0.492 324.000 249.528 324.096 ;
      RECT 0.492 326.400 249.528 326.496 ;
      RECT 0.492 328.800 249.528 328.896 ;
      RECT 0.492 331.200 249.528 331.296 ;
      RECT 0.492 333.600 249.528 333.696 ;
      RECT 0.492 336.000 249.528 336.096 ;
      RECT 0.492 338.400 249.528 338.496 ;
      RECT 0.492 340.800 249.528 340.896 ;
      RECT 0.492 343.200 249.528 343.296 ;
      RECT 0.492 345.600 249.528 345.696 ;
      RECT 0.492 348.000 249.528 348.096 ;
      RECT 0.492 350.400 249.528 350.496 ;
      RECT 0.492 352.800 249.528 352.896 ;
      RECT 0.492 355.200 249.528 355.296 ;
      RECT 0.492 357.600 249.528 357.696 ;
      RECT 0.492 360.000 249.528 360.096 ;
      RECT 0.492 362.400 249.528 362.496 ;
      RECT 0.492 364.800 249.528 364.896 ;
      RECT 0.492 367.200 249.528 367.296 ;
      RECT 0.492 369.600 249.528 369.696 ;
      RECT 0.492 372.000 249.528 372.096 ;
      RECT 0.492 374.400 249.528 374.496 ;
      RECT 0.492 376.800 249.528 376.896 ;
      RECT 0.492 379.200 249.528 379.296 ;
      RECT 0.492 381.600 249.528 381.696 ;
      RECT 0.492 384.000 249.528 384.096 ;
      RECT 0.492 386.400 249.528 386.496 ;
      RECT 0.492 388.800 249.528 388.896 ;
      RECT 0.492 391.200 249.528 391.296 ;
      RECT 0.492 393.600 249.528 393.696 ;
      RECT 0.492 396.000 249.528 396.096 ;
      RECT 0.492 398.400 249.528 398.496 ;
      RECT 0.492 400.800 249.528 400.896 ;
      RECT 0.492 403.200 249.528 403.296 ;
      RECT 0.492 405.600 249.528 405.696 ;
      RECT 0.492 408.000 249.528 408.096 ;
      RECT 0.492 410.400 249.528 410.496 ;
      RECT 0.492 412.800 249.528 412.896 ;
      RECT 0.492 415.200 249.528 415.296 ;
      RECT 0.492 417.600 249.528 417.696 ;
      RECT 0.492 420.000 249.528 420.096 ;
      RECT 0.492 422.400 249.528 422.496 ;
      RECT 0.492 424.800 249.528 424.896 ;
      RECT 0.492 427.200 249.528 427.296 ;
      RECT 0.492 429.600 249.528 429.696 ;
      RECT 0.492 432.000 249.528 432.096 ;
      RECT 0.492 434.400 249.528 434.496 ;
      RECT 0.492 436.800 249.528 436.896 ;
      RECT 0.492 439.200 249.528 439.296 ;
      RECT 0.492 441.600 249.528 441.696 ;
      RECT 0.492 444.000 249.528 444.096 ;
      RECT 0.492 446.400 249.528 446.496 ;
      RECT 0.492 448.800 249.528 448.896 ;
      RECT 0.492 451.200 249.528 451.296 ;
      RECT 0.492 453.600 249.528 453.696 ;
      RECT 0.492 456.000 249.528 456.096 ;
      RECT 0.492 458.400 249.528 458.496 ;
      RECT 0.492 460.800 249.528 460.896 ;
      RECT 0.492 463.200 249.528 463.296 ;
      RECT 0.492 465.600 249.528 465.696 ;
      RECT 0.492 468.000 249.528 468.096 ;
      RECT 0.492 470.400 249.528 470.496 ;
      RECT 0.492 472.800 249.528 472.896 ;
      RECT 0.492 475.200 249.528 475.296 ;
      RECT 0.492 477.600 249.528 477.696 ;
      RECT 0.492 480.000 249.528 480.096 ;
      RECT 0.492 482.400 249.528 482.496 ;
      RECT 0.492 484.800 249.528 484.896 ;
      RECT 0.492 487.200 249.528 487.296 ;
      RECT 0.492 489.600 249.528 489.696 ;
      RECT 0.492 492.000 249.528 492.096 ;
      RECT 0.492 494.400 249.528 494.496 ;
      RECT 0.492 496.800 249.528 496.896 ;
      RECT 0.492 499.200 249.528 499.296 ;
      RECT 0.492 501.600 249.528 501.696 ;
      RECT 0.492 504.000 249.528 504.096 ;
      RECT 0.492 506.400 249.528 506.496 ;
      RECT 0.492 508.800 249.528 508.896 ;
      RECT 0.492 511.200 249.528 511.296 ;
      RECT 0.492 513.600 249.528 513.696 ;
      RECT 0.492 516.000 249.528 516.096 ;
      RECT 0.492 518.400 249.528 518.496 ;
      RECT 0.492 520.800 249.528 520.896 ;
      RECT 0.492 523.200 249.528 523.296 ;
      RECT 0.492 525.600 249.528 525.696 ;
      RECT 0.492 528.000 249.528 528.096 ;
      RECT 0.492 530.400 249.528 530.496 ;
      RECT 0.492 532.800 249.528 532.896 ;
      RECT 0.492 535.200 249.528 535.296 ;
      RECT 0.492 537.600 249.528 537.696 ;
      RECT 0.492 540.000 249.528 540.096 ;
      RECT 0.492 542.400 249.528 542.496 ;
      RECT 0.492 544.800 249.528 544.896 ;
      RECT 0.492 547.200 249.528 547.296 ;
      RECT 0.492 549.600 249.528 549.696 ;
      RECT 0.492 552.000 249.528 552.096 ;
      RECT 0.492 554.400 249.528 554.496 ;
      RECT 0.492 556.800 249.528 556.896 ;
      RECT 0.492 559.200 249.528 559.296 ;
      RECT 0.492 561.600 249.528 561.696 ;
      RECT 0.492 564.000 249.528 564.096 ;
      RECT 0.492 566.400 249.528 566.496 ;
      RECT 0.492 568.800 249.528 568.896 ;
      RECT 0.492 571.200 249.528 571.296 ;
      RECT 0.492 573.600 249.528 573.696 ;
      RECT 0.492 576.000 249.528 576.096 ;
      RECT 0.492 578.400 249.528 578.496 ;
      RECT 0.492 580.800 249.528 580.896 ;
      RECT 0.492 583.200 249.528 583.296 ;
      RECT 0.492 585.600 249.528 585.696 ;
      RECT 0.492 588.000 249.528 588.096 ;
      RECT 0.492 590.400 249.528 590.496 ;
      RECT 0.492 592.800 249.528 592.896 ;
      RECT 0.492 595.200 249.528 595.296 ;
      RECT 0.492 597.600 249.528 597.696 ;
      RECT 0.492 600.000 249.528 600.096 ;
      RECT 0.492 602.400 249.528 602.496 ;
      RECT 0.492 604.800 249.528 604.896 ;
      RECT 0.492 607.200 249.528 607.296 ;
      RECT 0.492 609.600 249.528 609.696 ;
      RECT 0.492 612.000 249.528 612.096 ;
      RECT 0.492 614.400 249.528 614.496 ;
      RECT 0.492 616.800 249.528 616.896 ;
      RECT 0.492 619.200 249.528 619.296 ;
      RECT 0.492 621.600 249.528 621.696 ;
      RECT 0.492 624.000 249.528 624.096 ;
      RECT 0.492 626.400 249.528 626.496 ;
      RECT 0.492 628.800 249.528 628.896 ;
      RECT 0.492 631.200 249.528 631.296 ;
      RECT 0.492 633.600 249.528 633.696 ;
      RECT 0.492 636.000 249.528 636.096 ;
      RECT 0.492 638.400 249.528 638.496 ;
      RECT 0.492 640.800 249.528 640.896 ;
      RECT 0.492 643.200 249.528 643.296 ;
      RECT 0.492 645.600 249.528 645.696 ;
      RECT 0.492 648.000 249.528 648.096 ;
      RECT 0.492 650.400 249.528 650.496 ;
      RECT 0.492 652.800 249.528 652.896 ;
      RECT 0.492 655.200 249.528 655.296 ;
      RECT 0.492 657.600 249.528 657.696 ;
      RECT 0.492 660.000 249.528 660.096 ;
      RECT 0.492 662.400 249.528 662.496 ;
      RECT 0.492 664.800 249.528 664.896 ;
      RECT 0.492 667.200 249.528 667.296 ;
      RECT 0.492 669.600 249.528 669.696 ;
      RECT 0.492 672.000 249.528 672.096 ;
      RECT 0.492 674.400 249.528 674.496 ;
      RECT 0.492 676.800 249.528 676.896 ;
      RECT 0.492 679.200 249.528 679.296 ;
      RECT 0.492 681.600 249.528 681.696 ;
      RECT 0.492 684.000 249.528 684.096 ;
      RECT 0.492 686.400 249.528 686.496 ;
      RECT 0.492 688.800 249.528 688.896 ;
      RECT 0.492 691.200 249.528 691.296 ;
      RECT 0.492 693.600 249.528 693.696 ;
      RECT 0.492 696.000 249.528 696.096 ;
      RECT 0.492 698.400 249.528 698.496 ;
      RECT 0.492 700.800 249.528 700.896 ;
      RECT 0.492 703.200 249.528 703.296 ;
      RECT 0.492 705.600 249.528 705.696 ;
      RECT 0.492 708.000 249.528 708.096 ;
      RECT 0.492 710.400 249.528 710.496 ;
      RECT 0.492 712.800 249.528 712.896 ;
      RECT 0.492 715.200 249.528 715.296 ;
      RECT 0.492 717.600 249.528 717.696 ;
      RECT 0.492 720.000 249.528 720.096 ;
      RECT 0.492 722.400 249.528 722.496 ;
      RECT 0.492 724.800 249.528 724.896 ;
      RECT 0.492 727.200 249.528 727.296 ;
      RECT 0.492 729.600 249.528 729.696 ;
      RECT 0.492 732.000 249.528 732.096 ;
      RECT 0.492 734.400 249.528 734.496 ;
      RECT 0.492 736.800 249.528 736.896 ;
      RECT 0.492 739.200 249.528 739.296 ;
      RECT 0.492 741.600 249.528 741.696 ;
      RECT 0.492 744.000 249.528 744.096 ;
      RECT 0.492 746.400 249.528 746.496 ;
      RECT 0.492 748.800 249.528 748.896 ;
      RECT 0.492 751.200 249.528 751.296 ;
      RECT 0.492 753.600 249.528 753.696 ;
      RECT 0.492 756.000 249.528 756.096 ;
      RECT 0.492 758.400 249.528 758.496 ;
      RECT 0.492 760.800 249.528 760.896 ;
      RECT 0.492 763.200 249.528 763.296 ;
      RECT 0.492 765.600 249.528 765.696 ;
      RECT 0.492 768.000 249.528 768.096 ;
      RECT 0.492 770.400 249.528 770.496 ;
      RECT 0.492 772.800 249.528 772.896 ;
      RECT 0.492 775.200 249.528 775.296 ;
      RECT 0.492 777.600 249.528 777.696 ;
      RECT 0.492 780.000 249.528 780.096 ;
      RECT 0.492 782.400 249.528 782.496 ;
      RECT 0.492 784.800 249.528 784.896 ;
      RECT 0.492 787.200 249.528 787.296 ;
      RECT 0.492 789.600 249.528 789.696 ;
      RECT 0.492 792.000 249.528 792.096 ;
      RECT 0.492 794.400 249.528 794.496 ;
      RECT 0.492 796.800 249.528 796.896 ;
      RECT 0.492 799.200 249.528 799.296 ;
      RECT 0.492 801.600 249.528 801.696 ;
      RECT 0.492 804.000 249.528 804.096 ;
      RECT 0.492 806.400 249.528 806.496 ;
      RECT 0.492 808.800 249.528 808.896 ;
      RECT 0.492 811.200 249.528 811.296 ;
      RECT 0.492 813.600 249.528 813.696 ;
      RECT 0.492 816.000 249.528 816.096 ;
      RECT 0.492 818.400 249.528 818.496 ;
      RECT 0.492 820.800 249.528 820.896 ;
      RECT 0.492 823.200 249.528 823.296 ;
      RECT 0.492 825.600 249.528 825.696 ;
      RECT 0.492 828.000 249.528 828.096 ;
      RECT 0.492 830.400 249.528 830.496 ;
      RECT 0.492 832.800 249.528 832.896 ;
      RECT 0.492 835.200 249.528 835.296 ;
      RECT 0.492 837.600 249.528 837.696 ;
      RECT 0.492 840.000 249.528 840.096 ;
      RECT 0.492 842.400 249.528 842.496 ;
      RECT 0.492 844.800 249.528 844.896 ;
      RECT 0.492 847.200 249.528 847.296 ;
      RECT 0.492 849.600 249.528 849.696 ;
      RECT 0.492 852.000 249.528 852.096 ;
      RECT 0.492 854.400 249.528 854.496 ;
      RECT 0.492 856.800 249.528 856.896 ;
      RECT 0.492 859.200 249.528 859.296 ;
      RECT 0.492 861.600 249.528 861.696 ;
      RECT 0.492 864.000 249.528 864.096 ;
      RECT 0.492 866.400 249.528 866.496 ;
      RECT 0.492 868.800 249.528 868.896 ;
      RECT 0.492 871.200 249.528 871.296 ;
      RECT 0.492 873.600 249.528 873.696 ;
      RECT 0.492 876.000 249.528 876.096 ;
      RECT 0.492 878.400 249.528 878.496 ;
      RECT 0.492 880.800 249.528 880.896 ;
      RECT 0.492 883.200 249.528 883.296 ;
      RECT 0.492 885.600 249.528 885.696 ;
      RECT 0.492 888.000 249.528 888.096 ;
      RECT 0.492 890.400 249.528 890.496 ;
      RECT 0.492 892.800 249.528 892.896 ;
      RECT 0.492 895.200 249.528 895.296 ;
      RECT 0.492 897.600 249.528 897.696 ;
      RECT 0.492 900.000 249.528 900.096 ;
      RECT 0.492 902.400 249.528 902.496 ;
      RECT 0.492 904.800 249.528 904.896 ;
      RECT 0.492 907.200 249.528 907.296 ;
      RECT 0.492 909.600 249.528 909.696 ;
      RECT 0.492 912.000 249.528 912.096 ;
      RECT 0.492 914.400 249.528 914.496 ;
      RECT 0.492 916.800 249.528 916.896 ;
      RECT 0.492 919.200 249.528 919.296 ;
      RECT 0.492 921.600 249.528 921.696 ;
      RECT 0.492 924.000 249.528 924.096 ;
      RECT 0.492 926.400 249.528 926.496 ;
      RECT 0.492 928.800 249.528 928.896 ;
      RECT 0.492 931.200 249.528 931.296 ;
      RECT 0.492 933.600 249.528 933.696 ;
      RECT 0.492 936.000 249.528 936.096 ;
      RECT 0.492 938.400 249.528 938.496 ;
      RECT 0.492 940.800 249.528 940.896 ;
      RECT 0.492 943.200 249.528 943.296 ;
      RECT 0.492 945.600 249.528 945.696 ;
      RECT 0.492 948.000 249.528 948.096 ;
      RECT 0.492 950.400 249.528 950.496 ;
      RECT 0.492 952.800 249.528 952.896 ;
      RECT 0.492 955.200 249.528 955.296 ;
      RECT 0.492 957.600 249.528 957.696 ;
      RECT 0.492 960.000 249.528 960.096 ;
      RECT 0.492 962.400 249.528 962.496 ;
      RECT 0.492 964.800 249.528 964.896 ;
      RECT 0.492 967.200 249.528 967.296 ;
      RECT 0.492 969.600 249.528 969.696 ;
      RECT 0.492 972.000 249.528 972.096 ;
      RECT 0.492 974.400 249.528 974.496 ;
      RECT 0.492 976.800 249.528 976.896 ;
      RECT 0.492 979.200 249.528 979.296 ;
      RECT 0.492 981.600 249.528 981.696 ;
      RECT 0.492 984.000 249.528 984.096 ;
      RECT 0.492 986.400 249.528 986.496 ;
      RECT 0.492 988.800 249.528 988.896 ;
      RECT 0.492 991.200 249.528 991.296 ;
      RECT 0.492 993.600 249.528 993.696 ;
      RECT 0.492 996.000 249.528 996.096 ;
      RECT 0.492 998.400 249.528 998.496 ;
      RECT 0.492 1000.800 249.528 1000.896 ;
      RECT 0.492 1003.200 249.528 1003.296 ;
      RECT 0.492 1005.600 249.528 1005.696 ;
      RECT 0.492 1008.000 249.528 1008.096 ;
      RECT 0.492 1010.400 249.528 1010.496 ;
      RECT 0.492 1012.800 249.528 1012.896 ;
      RECT 0.492 1015.200 249.528 1015.296 ;
      RECT 0.492 1017.600 249.528 1017.696 ;
      RECT 0.492 1020.000 249.528 1020.096 ;
      RECT 0.492 1022.400 249.528 1022.496 ;
      RECT 0.492 1024.800 249.528 1024.896 ;
      RECT 0.492 1027.200 249.528 1027.296 ;
      RECT 0.492 1029.600 249.528 1029.696 ;
      RECT 0.492 1032.000 249.528 1032.096 ;
      RECT 0.492 1034.400 249.528 1034.496 ;
      RECT 0.492 1036.800 249.528 1036.896 ;
      RECT 0.492 1039.200 249.528 1039.296 ;
      RECT 0.492 1041.600 249.528 1041.696 ;
      RECT 0.492 1044.000 249.528 1044.096 ;
      RECT 0.492 1046.400 249.528 1046.496 ;
      RECT 0.492 1048.800 249.528 1048.896 ;
      RECT 0.492 1051.200 249.528 1051.296 ;
      RECT 0.492 1053.600 249.528 1053.696 ;
      RECT 0.492 1056.000 249.528 1056.096 ;
      RECT 0.492 1058.400 249.528 1058.496 ;
      RECT 0.492 1060.800 249.528 1060.896 ;
      RECT 0.492 1063.200 249.528 1063.296 ;
      RECT 0.492 1065.600 249.528 1065.696 ;
      RECT 0.492 1068.000 249.528 1068.096 ;
      RECT 0.492 1070.400 249.528 1070.496 ;
      RECT 0.492 1072.800 249.528 1072.896 ;
      RECT 0.492 1075.200 249.528 1075.296 ;
      RECT 0.492 1077.600 249.528 1077.696 ;
      RECT 0.492 1080.000 249.528 1080.096 ;
      RECT 0.492 1082.400 249.528 1082.496 ;
      RECT 0.492 1084.800 249.528 1084.896 ;
      RECT 0.492 1087.200 249.528 1087.296 ;
      RECT 0.492 1089.600 249.528 1089.696 ;
      RECT 0.492 1092.000 249.528 1092.096 ;
      RECT 0.492 1094.400 249.528 1094.496 ;
      RECT 0.492 1096.800 249.528 1096.896 ;
      RECT 0.492 1099.200 249.528 1099.296 ;
      RECT 0.492 1101.600 249.528 1101.696 ;
      RECT 0.492 1104.000 249.528 1104.096 ;
      RECT 0.492 1106.400 249.528 1106.496 ;
      RECT 0.492 1108.800 249.528 1108.896 ;
      RECT 0.492 1111.200 249.528 1111.296 ;
      RECT 0.492 1113.600 249.528 1113.696 ;
      RECT 0.492 1116.000 249.528 1116.096 ;
      RECT 0.492 1118.400 249.528 1118.496 ;
      RECT 0.492 1120.800 249.528 1120.896 ;
      RECT 0.492 1123.200 249.528 1123.296 ;
      RECT 0.492 1125.600 249.528 1125.696 ;
      RECT 0.492 1128.000 249.528 1128.096 ;
      RECT 0.492 1130.400 249.528 1130.496 ;
      RECT 0.492 1132.800 249.528 1132.896 ;
      RECT 0.492 1135.200 249.528 1135.296 ;
      RECT 0.492 1137.600 249.528 1137.696 ;
      RECT 0.492 1140.000 249.528 1140.096 ;
      RECT 0.492 1142.400 249.528 1142.496 ;
      RECT 0.492 1144.800 249.528 1144.896 ;
      RECT 0.492 1147.200 249.528 1147.296 ;
      RECT 0.492 1149.600 249.528 1149.696 ;
      RECT 0.492 1152.000 249.528 1152.096 ;
      RECT 0.492 1154.400 249.528 1154.496 ;
      RECT 0.492 1156.800 249.528 1156.896 ;
      RECT 0.492 1159.200 249.528 1159.296 ;
      RECT 0.492 1161.600 249.528 1161.696 ;
      RECT 0.492 1164.000 249.528 1164.096 ;
      RECT 0.492 1166.400 249.528 1166.496 ;
      RECT 0.492 1168.800 249.528 1168.896 ;
      RECT 0.492 1171.200 249.528 1171.296 ;
      RECT 0.492 1173.600 249.528 1173.696 ;
      RECT 0.492 1176.000 249.528 1176.096 ;
      RECT 0.492 1178.400 249.528 1178.496 ;
      RECT 0.492 1180.800 249.528 1180.896 ;
      RECT 0.492 1183.200 249.528 1183.296 ;
      RECT 0.492 1185.600 249.528 1185.696 ;
      RECT 0.492 1188.000 249.528 1188.096 ;
      RECT 0.492 1190.400 249.528 1190.496 ;
      RECT 0.492 1192.800 249.528 1192.896 ;
      RECT 0.492 1195.200 249.528 1195.296 ;
      RECT 0.492 1197.600 249.528 1197.696 ;
      RECT 0.492 1200.000 249.528 1200.096 ;
      RECT 0.492 1202.400 249.528 1202.496 ;
      RECT 0.492 1204.800 249.528 1204.896 ;
      RECT 0.492 1207.200 249.528 1207.296 ;
      RECT 0.492 1209.600 249.528 1209.696 ;
      RECT 0.492 1212.000 249.528 1212.096 ;
      RECT 0.492 1214.400 249.528 1214.496 ;
      RECT 0.492 1216.800 249.528 1216.896 ;
      RECT 0.492 1219.200 249.528 1219.296 ;
      RECT 0.492 1221.600 249.528 1221.696 ;
      RECT 0.492 1224.000 249.528 1224.096 ;
      RECT 0.492 1226.400 249.528 1226.496 ;
      RECT 0.492 1228.800 249.528 1228.896 ;
      RECT 0.492 1231.200 249.528 1231.296 ;
      RECT 0.492 1233.600 249.528 1233.696 ;
      RECT 0.492 1236.000 249.528 1236.096 ;
      RECT 0.492 1238.400 249.528 1238.496 ;
      RECT 0.492 1240.800 249.528 1240.896 ;
      RECT 0.492 1243.200 249.528 1243.296 ;
      RECT 0.492 1245.600 249.528 1245.696 ;
      RECT 0.492 1248.000 249.528 1248.096 ;
      RECT 0.492 1250.400 249.528 1250.496 ;
      RECT 0.492 1252.800 249.528 1252.896 ;
      RECT 0.492 1255.200 249.528 1255.296 ;
      RECT 0.492 1257.600 249.528 1257.696 ;
      RECT 0.492 1260.000 249.528 1260.096 ;
      RECT 0.492 1262.400 249.528 1262.496 ;
      RECT 0.492 1264.800 249.528 1264.896 ;
      RECT 0.492 1267.200 249.528 1267.296 ;
      RECT 0.492 1269.600 249.528 1269.696 ;
      RECT 0.492 1272.000 249.528 1272.096 ;
      RECT 0.492 1274.400 249.528 1274.496 ;
      RECT 0.492 1276.800 249.528 1276.896 ;
      RECT 0.492 1279.200 249.528 1279.296 ;
      RECT 0.492 1281.600 249.528 1281.696 ;
      RECT 0.492 1284.000 249.528 1284.096 ;
      RECT 0.492 1286.400 249.528 1286.496 ;
      RECT 0.492 1288.800 249.528 1288.896 ;
      RECT 0.492 1291.200 249.528 1291.296 ;
      RECT 0.492 1293.600 249.528 1293.696 ;
      RECT 0.492 1296.000 249.528 1296.096 ;
      RECT 0.492 1298.400 249.528 1298.496 ;
      RECT 0.492 1300.800 249.528 1300.896 ;
      RECT 0.492 1303.200 249.528 1303.296 ;
      RECT 0.492 1305.600 249.528 1305.696 ;
      RECT 0.492 1308.000 249.528 1308.096 ;
      RECT 0.492 1310.400 249.528 1310.496 ;
      RECT 0.492 1312.800 249.528 1312.896 ;
      RECT 0.492 1315.200 249.528 1315.296 ;
      RECT 0.492 1317.600 249.528 1317.696 ;
      RECT 0.492 1320.000 249.528 1320.096 ;
      RECT 0.492 1322.400 249.528 1322.496 ;
      RECT 0.492 1324.800 249.528 1324.896 ;
      RECT 0.492 1327.200 249.528 1327.296 ;
      RECT 0.492 1329.600 249.528 1329.696 ;
      RECT 0.492 1332.000 249.528 1332.096 ;
      RECT 0.492 1334.400 249.528 1334.496 ;
      RECT 0.492 1336.800 249.528 1336.896 ;
      RECT 0.492 1339.200 249.528 1339.296 ;
      RECT 0.492 1341.600 249.528 1341.696 ;
      RECT 0.492 1344.000 249.528 1344.096 ;
      RECT 0.492 1346.400 249.528 1346.496 ;
      RECT 0.492 1348.800 249.528 1348.896 ;
      RECT 0.492 1351.200 249.528 1351.296 ;
      RECT 0.492 1353.600 249.528 1353.696 ;
      RECT 0.492 1356.000 249.528 1356.096 ;
      RECT 0.492 1358.400 249.528 1358.496 ;
      RECT 0.492 1360.800 249.528 1360.896 ;
      RECT 0.492 1363.200 249.528 1363.296 ;
      RECT 0.492 1365.600 249.528 1365.696 ;
      RECT 0.492 1368.000 249.528 1368.096 ;
      RECT 0.492 1370.400 249.528 1370.496 ;
      RECT 0.492 1372.800 249.528 1372.896 ;
      RECT 0.492 1375.200 249.528 1375.296 ;
      RECT 0.492 1377.600 249.528 1377.696 ;
      RECT 0.492 1380.000 249.528 1380.096 ;
      RECT 0.492 1382.400 249.528 1382.496 ;
      RECT 0.492 1384.800 249.528 1384.896 ;
      RECT 0.492 1387.200 249.528 1387.296 ;
      RECT 0.492 1389.600 249.528 1389.696 ;
      RECT 0.492 1392.000 249.528 1392.096 ;
      RECT 0.492 1394.400 249.528 1394.496 ;
      RECT 0.492 1396.800 249.528 1396.896 ;
      RECT 0.492 1399.200 249.528 1399.296 ;
      RECT 0.492 1401.600 249.528 1401.696 ;
      RECT 0.492 1404.000 249.528 1404.096 ;
      RECT 0.492 1406.400 249.528 1406.496 ;
      RECT 0.492 1408.800 249.528 1408.896 ;
      RECT 0.492 1411.200 249.528 1411.296 ;
      RECT 0.492 1413.600 249.528 1413.696 ;
      RECT 0.492 1416.000 249.528 1416.096 ;
      RECT 0.492 1418.400 249.528 1418.496 ;
      RECT 0.492 1420.800 249.528 1420.896 ;
      RECT 0.492 1423.200 249.528 1423.296 ;
      RECT 0.492 1425.600 249.528 1425.696 ;
      RECT 0.492 1428.000 249.528 1428.096 ;
      RECT 0.492 1430.400 249.528 1430.496 ;
      RECT 0.492 1432.800 249.528 1432.896 ;
      RECT 0.492 1435.200 249.528 1435.296 ;
      RECT 0.492 1437.600 249.528 1437.696 ;
      RECT 0.492 1440.000 249.528 1440.096 ;
      RECT 0.492 1442.400 249.528 1442.496 ;
      RECT 0.492 1444.800 249.528 1444.896 ;
      RECT 0.492 1447.200 249.528 1447.296 ;
      RECT 0.492 1449.600 249.528 1449.696 ;
      RECT 0.492 1452.000 249.528 1452.096 ;
      RECT 0.492 1454.400 249.528 1454.496 ;
      RECT 0.492 1456.800 249.528 1456.896 ;
      RECT 0.492 1459.200 249.528 1459.296 ;
      RECT 0.492 1461.600 249.528 1461.696 ;
      RECT 0.492 1464.000 249.528 1464.096 ;
      RECT 0.492 1466.400 249.528 1466.496 ;
      RECT 0.492 1468.800 249.528 1468.896 ;
      RECT 0.492 1471.200 249.528 1471.296 ;
      RECT 0.492 1473.600 249.528 1473.696 ;
      RECT 0.492 1476.000 249.528 1476.096 ;
      RECT 0.492 1478.400 249.528 1478.496 ;
      RECT 0.492 1480.800 249.528 1480.896 ;
      RECT 0.492 1483.200 249.528 1483.296 ;
      RECT 0.492 1485.600 249.528 1485.696 ;
      RECT 0.492 1488.000 249.528 1488.096 ;
      RECT 0.492 1490.400 249.528 1490.496 ;
      RECT 0.492 1492.800 249.528 1492.896 ;
      RECT 0.492 1495.200 249.528 1495.296 ;
      RECT 0.492 1497.600 249.528 1497.696 ;
      RECT 0.492 1500.000 249.528 1500.096 ;
      RECT 0.492 1502.400 249.528 1502.496 ;
      RECT 0.492 1504.800 249.528 1504.896 ;
      RECT 0.492 1507.200 249.528 1507.296 ;
      RECT 0.492 1509.600 249.528 1509.696 ;
      RECT 0.492 1512.000 249.528 1512.096 ;
      RECT 0.492 1514.400 249.528 1514.496 ;
      RECT 0.492 1516.800 249.528 1516.896 ;
      RECT 0.492 1519.200 249.528 1519.296 ;
      RECT 0.492 1521.600 249.528 1521.696 ;
      RECT 0.492 1524.000 249.528 1524.096 ;
      RECT 0.492 1526.400 249.528 1526.496 ;
      RECT 0.492 1528.800 249.528 1528.896 ;
      RECT 0.492 1531.200 249.528 1531.296 ;
      RECT 0.492 1533.600 249.528 1533.696 ;
      RECT 0.492 1536.000 249.528 1536.096 ;
      RECT 0.492 1538.400 249.528 1538.496 ;
      RECT 0.492 1540.800 249.528 1540.896 ;
      RECT 0.492 1543.200 249.528 1543.296 ;
      RECT 0.492 1545.600 249.528 1545.696 ;
      RECT 0.492 1548.000 249.528 1548.096 ;
      RECT 0.492 1550.400 249.528 1550.496 ;
      RECT 0.492 1552.800 249.528 1552.896 ;
      RECT 0.492 1555.200 249.528 1555.296 ;
      RECT 0.492 1557.600 249.528 1557.696 ;
      RECT 0.492 1560.000 249.528 1560.096 ;
      RECT 0.492 1562.400 249.528 1562.496 ;
      RECT 0.492 1564.800 249.528 1564.896 ;
      RECT 0.492 1567.200 249.528 1567.296 ;
      RECT 0.492 1569.600 249.528 1569.696 ;
      RECT 0.492 1572.000 249.528 1572.096 ;
      RECT 0.492 1574.400 249.528 1574.496 ;
      RECT 0.492 1576.800 249.528 1576.896 ;
      RECT 0.492 1579.200 249.528 1579.296 ;
      RECT 0.492 1581.600 249.528 1581.696 ;
      RECT 0.492 1584.000 249.528 1584.096 ;
      RECT 0.492 1586.400 249.528 1586.496 ;
      RECT 0.492 1588.800 249.528 1588.896 ;
      RECT 0.492 1591.200 249.528 1591.296 ;
      RECT 0.492 1593.600 249.528 1593.696 ;
      RECT 0.492 1596.000 249.528 1596.096 ;
      RECT 0.492 1598.400 249.528 1598.496 ;
      RECT 0.492 1600.800 249.528 1600.896 ;
      RECT 0.492 1603.200 249.528 1603.296 ;
      RECT 0.492 1605.600 249.528 1605.696 ;
      RECT 0.492 1608.000 249.528 1608.096 ;
      RECT 0.492 1610.400 249.528 1610.496 ;
      RECT 0.492 1612.800 249.528 1612.896 ;
      RECT 0.492 1615.200 249.528 1615.296 ;
      RECT 0.492 1617.600 249.528 1617.696 ;
      RECT 0.492 1620.000 249.528 1620.096 ;
      RECT 0.492 1622.400 249.528 1622.496 ;
      RECT 0.492 1624.800 249.528 1624.896 ;
      RECT 0.492 1627.200 249.528 1627.296 ;
      RECT 0.492 1629.600 249.528 1629.696 ;
      RECT 0.492 1632.000 249.528 1632.096 ;
      RECT 0.492 1634.400 249.528 1634.496 ;
      RECT 0.492 1636.800 249.528 1636.896 ;
      RECT 0.492 1639.200 249.528 1639.296 ;
      RECT 0.492 1641.600 249.528 1641.696 ;
      RECT 0.492 1644.000 249.528 1644.096 ;
      RECT 0.492 1646.400 249.528 1646.496 ;
      RECT 0.492 1648.800 249.528 1648.896 ;
      RECT 0.492 1651.200 249.528 1651.296 ;
      RECT 0.492 1653.600 249.528 1653.696 ;
      RECT 0.492 1656.000 249.528 1656.096 ;
      RECT 0.492 1658.400 249.528 1658.496 ;
      RECT 0.492 1660.800 249.528 1660.896 ;
      RECT 0.492 1663.200 249.528 1663.296 ;
      RECT 0.492 1665.600 249.528 1665.696 ;
      RECT 0.492 1668.000 249.528 1668.096 ;
      RECT 0.492 1670.400 249.528 1670.496 ;
      RECT 0.492 1672.800 249.528 1672.896 ;
      RECT 0.492 1675.200 249.528 1675.296 ;
      RECT 0.492 1677.600 249.528 1677.696 ;
      RECT 0.492 1680.000 249.528 1680.096 ;
      RECT 0.492 1682.400 249.528 1682.496 ;
      RECT 0.492 1684.800 249.528 1684.896 ;
      RECT 0.492 1687.200 249.528 1687.296 ;
      RECT 0.492 1689.600 249.528 1689.696 ;
      RECT 0.492 1692.000 249.528 1692.096 ;
      RECT 0.492 1694.400 249.528 1694.496 ;
      RECT 0.492 1696.800 249.528 1696.896 ;
      RECT 0.492 1699.200 249.528 1699.296 ;
      RECT 0.492 1701.600 249.528 1701.696 ;
      RECT 0.492 1704.000 249.528 1704.096 ;
      RECT 0.492 1706.400 249.528 1706.496 ;
      RECT 0.492 1708.800 249.528 1708.896 ;
      RECT 0.492 1711.200 249.528 1711.296 ;
      RECT 0.492 1713.600 249.528 1713.696 ;
      RECT 0.492 1716.000 249.528 1716.096 ;
      RECT 0.492 1718.400 249.528 1718.496 ;
      RECT 0.492 1720.800 249.528 1720.896 ;
      RECT 0.492 1723.200 249.528 1723.296 ;
      RECT 0.492 1725.600 249.528 1725.696 ;
      RECT 0.492 1728.000 249.528 1728.096 ;
      RECT 0.492 1730.400 249.528 1730.496 ;
      RECT 0.492 1732.800 249.528 1732.896 ;
      RECT 0.492 1735.200 249.528 1735.296 ;
      RECT 0.492 1737.600 249.528 1737.696 ;
      RECT 0.492 1740.000 249.528 1740.096 ;
      RECT 0.492 1742.400 249.528 1742.496 ;
      RECT 0.492 1744.800 249.528 1744.896 ;
      RECT 0.492 1747.200 249.528 1747.296 ;
      RECT 0.492 1749.600 249.528 1749.696 ;
      RECT 0.492 1752.000 249.528 1752.096 ;
      RECT 0.492 1754.400 249.528 1754.496 ;
      RECT 0.492 1756.800 249.528 1756.896 ;
      RECT 0.492 1759.200 249.528 1759.296 ;
      RECT 0.492 1761.600 249.528 1761.696 ;
      RECT 0.492 1764.000 249.528 1764.096 ;
      RECT 0.492 1766.400 249.528 1766.496 ;
      RECT 0.492 1768.800 249.528 1768.896 ;
      RECT 0.492 1771.200 249.528 1771.296 ;
      RECT 0.492 1773.600 249.528 1773.696 ;
      RECT 0.492 1776.000 249.528 1776.096 ;
      RECT 0.492 1778.400 249.528 1778.496 ;
      RECT 0.492 1780.800 249.528 1780.896 ;
      RECT 0.492 1783.200 249.528 1783.296 ;
      RECT 0.492 1785.600 249.528 1785.696 ;
      RECT 0.492 1788.000 249.528 1788.096 ;
      RECT 0.492 1790.400 249.528 1790.496 ;
      RECT 0.492 1792.800 249.528 1792.896 ;
      RECT 0.492 1795.200 249.528 1795.296 ;
      RECT 0.492 1797.600 249.528 1797.696 ;
      RECT 0.492 1800.000 249.528 1800.096 ;
      RECT 0.492 1802.400 249.528 1802.496 ;
      RECT 0.492 1804.800 249.528 1804.896 ;
      RECT 0.492 1807.200 249.528 1807.296 ;
      RECT 0.492 1809.600 249.528 1809.696 ;
      RECT 0.492 1812.000 249.528 1812.096 ;
      RECT 0.492 1814.400 249.528 1814.496 ;
      RECT 0.492 1816.800 249.528 1816.896 ;
      RECT 0.492 1819.200 249.528 1819.296 ;
      RECT 0.492 1821.600 249.528 1821.696 ;
      RECT 0.492 1824.000 249.528 1824.096 ;
      RECT 0.492 1826.400 249.528 1826.496 ;
      RECT 0.492 1828.800 249.528 1828.896 ;
      RECT 0.492 1831.200 249.528 1831.296 ;
      RECT 0.492 1833.600 249.528 1833.696 ;
      RECT 0.492 1836.000 249.528 1836.096 ;
      RECT 0.492 1838.400 249.528 1838.496 ;
      RECT 0.492 1840.800 249.528 1840.896 ;
      RECT 0.492 1843.200 249.528 1843.296 ;
      RECT 0.492 1845.600 249.528 1845.696 ;
      RECT 0.492 1848.000 249.528 1848.096 ;
      RECT 0.492 1850.400 249.528 1850.496 ;
      RECT 0.492 1852.800 249.528 1852.896 ;
      RECT 0.492 1855.200 249.528 1855.296 ;
      RECT 0.492 1857.600 249.528 1857.696 ;
      RECT 0.492 1860.000 249.528 1860.096 ;
      RECT 0.492 1862.400 249.528 1862.496 ;
      RECT 0.492 1864.800 249.528 1864.896 ;
      RECT 0.492 1867.200 249.528 1867.296 ;
      RECT 0.492 1869.600 249.528 1869.696 ;
      RECT 0.492 1872.000 249.528 1872.096 ;
      RECT 0.492 1874.400 249.528 1874.496 ;
      RECT 0.492 1876.800 249.528 1876.896 ;
      RECT 0.492 1879.200 249.528 1879.296 ;
      RECT 0.492 1881.600 249.528 1881.696 ;
      RECT 0.492 1884.000 249.528 1884.096 ;
      RECT 0.492 1886.400 249.528 1886.496 ;
      RECT 0.492 1888.800 249.528 1888.896 ;
      RECT 0.492 1891.200 249.528 1891.296 ;
      RECT 0.492 1893.600 249.528 1893.696 ;
      RECT 0.492 1896.000 249.528 1896.096 ;
      RECT 0.492 1898.400 249.528 1898.496 ;
      RECT 0.492 1900.800 249.528 1900.896 ;
      RECT 0.492 1903.200 249.528 1903.296 ;
      RECT 0.492 1905.600 249.528 1905.696 ;
      RECT 0.492 1908.000 249.528 1908.096 ;
      RECT 0.492 1910.400 249.528 1910.496 ;
      RECT 0.492 1912.800 249.528 1912.896 ;
      RECT 0.492 1915.200 249.528 1915.296 ;
      RECT 0.492 1917.600 249.528 1917.696 ;
      RECT 0.492 1920.000 249.528 1920.096 ;
      RECT 0.492 1922.400 249.528 1922.496 ;
      RECT 0.492 1924.800 249.528 1924.896 ;
      RECT 0.492 1927.200 249.528 1927.296 ;
      RECT 0.492 1929.600 249.528 1929.696 ;
      RECT 0.492 1932.000 249.528 1932.096 ;
      RECT 0.492 1934.400 249.528 1934.496 ;
      RECT 0.492 1936.800 249.528 1936.896 ;
      RECT 0.492 1939.200 249.528 1939.296 ;
      RECT 0.492 1941.600 249.528 1941.696 ;
      RECT 0.492 1944.000 249.528 1944.096 ;
      RECT 0.492 1946.400 249.528 1946.496 ;
      RECT 0.492 1948.800 249.528 1948.896 ;
      RECT 0.492 1951.200 249.528 1951.296 ;
      RECT 0.492 1953.600 249.528 1953.696 ;
      RECT 0.492 1956.000 249.528 1956.096 ;
      RECT 0.492 1958.400 249.528 1958.496 ;
      RECT 0.492 1960.800 249.528 1960.896 ;
      RECT 0.492 1963.200 249.528 1963.296 ;
      RECT 0.492 1965.600 249.528 1965.696 ;
      RECT 0.492 1968.000 249.528 1968.096 ;
      RECT 0.492 1970.400 249.528 1970.496 ;
      RECT 0.492 1972.800 249.528 1972.896 ;
      RECT 0.492 1975.200 249.528 1975.296 ;
      RECT 0.492 1977.600 249.528 1977.696 ;
      RECT 0.492 1980.000 249.528 1980.096 ;
      RECT 0.492 1982.400 249.528 1982.496 ;
      RECT 0.492 1984.800 249.528 1984.896 ;
      RECT 0.492 1987.200 249.528 1987.296 ;
      RECT 0.492 1989.600 249.528 1989.696 ;
      RECT 0.492 1992.000 249.528 1992.096 ;
      RECT 0.492 1994.400 249.528 1994.496 ;
      RECT 0.492 1996.800 249.528 1996.896 ;
      RECT 0.492 1999.200 249.528 1999.296 ;
      RECT 0.492 2001.600 249.528 2001.696 ;
      RECT 0.492 2004.000 249.528 2004.096 ;
      RECT 0.492 2006.400 249.528 2006.496 ;
      RECT 0.492 2008.800 249.528 2008.896 ;
      RECT 0.492 2011.200 249.528 2011.296 ;
      RECT 0.492 2013.600 249.528 2013.696 ;
      RECT 0.492 2016.000 249.528 2016.096 ;
      RECT 0.492 2018.400 249.528 2018.496 ;
      RECT 0.492 2020.800 249.528 2020.896 ;
      RECT 0.492 2023.200 249.528 2023.296 ;
      RECT 0.492 2025.600 249.528 2025.696 ;
      RECT 0.492 2028.000 249.528 2028.096 ;
      RECT 0.492 2030.400 249.528 2030.496 ;
      RECT 0.492 2032.800 249.528 2032.896 ;
      RECT 0.492 2035.200 249.528 2035.296 ;
      RECT 0.492 2037.600 249.528 2037.696 ;
      RECT 0.492 2040.000 249.528 2040.096 ;
      RECT 0.492 2042.400 249.528 2042.496 ;
      RECT 0.492 2044.800 249.528 2044.896 ;
      RECT 0.492 2047.200 249.528 2047.296 ;
      RECT 0.492 2049.600 249.528 2049.696 ;
      RECT 0.492 2052.000 249.528 2052.096 ;
      RECT 0.492 2054.400 249.528 2054.496 ;
      RECT 0.492 2056.800 249.528 2056.896 ;
      RECT 0.492 2059.200 249.528 2059.296 ;
      RECT 0.492 2061.600 249.528 2061.696 ;
      RECT 0.492 2064.000 249.528 2064.096 ;
      RECT 0.492 2066.400 249.528 2066.496 ;
      RECT 0.492 2068.800 249.528 2068.896 ;
      RECT 0.492 2071.200 249.528 2071.296 ;
      RECT 0.492 2073.600 249.528 2073.696 ;
      RECT 0.492 2076.000 249.528 2076.096 ;
      RECT 0.492 2078.400 249.528 2078.496 ;
      RECT 0.492 2080.800 249.528 2080.896 ;
      RECT 0.492 2083.200 249.528 2083.296 ;
      RECT 0.492 2085.600 249.528 2085.696 ;
      RECT 0.492 2088.000 249.528 2088.096 ;
      RECT 0.492 2090.400 249.528 2090.496 ;
      RECT 0.492 2092.800 249.528 2092.896 ;
      RECT 0.492 2095.200 249.528 2095.296 ;
      RECT 0.492 2097.600 249.528 2097.696 ;
      RECT 0.492 2100.000 249.528 2100.096 ;
      RECT 0.492 2102.400 249.528 2102.496 ;
      RECT 0.492 2104.800 249.528 2104.896 ;
      RECT 0.492 2107.200 249.528 2107.296 ;
      RECT 0.492 2109.600 249.528 2109.696 ;
      RECT 0.492 2112.000 249.528 2112.096 ;
      RECT 0.492 2114.400 249.528 2114.496 ;
      RECT 0.492 2116.800 249.528 2116.896 ;
      RECT 0.492 2119.200 249.528 2119.296 ;
      RECT 0.492 2121.600 249.528 2121.696 ;
      RECT 0.492 2124.000 249.528 2124.096 ;
      RECT 0.492 2126.400 249.528 2126.496 ;
      RECT 0.492 2128.800 249.528 2128.896 ;
      RECT 0.492 2131.200 249.528 2131.296 ;
      RECT 0.492 2133.600 249.528 2133.696 ;
      RECT 0.492 2136.000 249.528 2136.096 ;
      RECT 0.492 2138.400 249.528 2138.496 ;
      RECT 0.492 2140.800 249.528 2140.896 ;
      RECT 0.492 2143.200 249.528 2143.296 ;
      RECT 0.492 2145.600 249.528 2145.696 ;
      RECT 0.492 2148.000 249.528 2148.096 ;
      RECT 0.492 2150.400 249.528 2150.496 ;
      RECT 0.492 2152.800 249.528 2152.896 ;
      RECT 0.492 2155.200 249.528 2155.296 ;
      RECT 0.492 2157.600 249.528 2157.696 ;
      RECT 0.492 2160.000 249.528 2160.096 ;
      RECT 0.492 2162.400 249.528 2162.496 ;
      RECT 0.492 2164.800 249.528 2164.896 ;
      RECT 0.492 2167.200 249.528 2167.296 ;
      RECT 0.492 2169.600 249.528 2169.696 ;
      RECT 0.492 2172.000 249.528 2172.096 ;
      RECT 0.492 2174.400 249.528 2174.496 ;
      RECT 0.492 2176.800 249.528 2176.896 ;
      RECT 0.492 2179.200 249.528 2179.296 ;
      RECT 0.492 2181.600 249.528 2181.696 ;
      RECT 0.492 2184.000 249.528 2184.096 ;
      RECT 0.492 2186.400 249.528 2186.496 ;
      RECT 0.492 2188.800 249.528 2188.896 ;
      RECT 0.492 2191.200 249.528 2191.296 ;
      RECT 0.492 2193.600 249.528 2193.696 ;
      RECT 0.492 2196.000 249.528 2196.096 ;
      RECT 0.492 2198.400 249.528 2198.496 ;
      RECT 0.492 2200.800 249.528 2200.896 ;
      RECT 0.492 2203.200 249.528 2203.296 ;
      RECT 0.492 2205.600 249.528 2205.696 ;
      RECT 0.492 2208.000 249.528 2208.096 ;
      RECT 0.492 2210.400 249.528 2210.496 ;
      RECT 0.492 2212.800 249.528 2212.896 ;
      RECT 0.492 2215.200 249.528 2215.296 ;
      RECT 0.492 2217.600 249.528 2217.696 ;
      RECT 0.492 2220.000 249.528 2220.096 ;
      RECT 0.492 2222.400 249.528 2222.496 ;
      RECT 0.492 2224.800 249.528 2224.896 ;
      RECT 0.492 2227.200 249.528 2227.296 ;
      RECT 0.492 2229.600 249.528 2229.696 ;
      RECT 0.492 2232.000 249.528 2232.096 ;
      RECT 0.492 2234.400 249.528 2234.496 ;
      RECT 0.492 2236.800 249.528 2236.896 ;
      RECT 0.492 2239.200 249.528 2239.296 ;
      RECT 0.492 2241.600 249.528 2241.696 ;
      RECT 0.492 2244.000 249.528 2244.096 ;
      RECT 0.492 2246.400 249.528 2246.496 ;
      RECT 0.492 2248.800 249.528 2248.896 ;
    END
  END VDD
  OBS
    LAYER M1 ;
    RECT 0 0 250.020 2250.180 ;
    LAYER M2 ;
    RECT 0 0 250.020 2250.180 ;
    LAYER M3 ;
    RECT 0 0 250.020 2250.180 ;
    LAYER M4 ;
    RECT 0 0 250.020 2250.180 ;
  END
END ot_pdie_serdes

END LIBRARY
